VERSION 5.8 ;
BUSBITCHARS "[]" ;
DIVIDERCHAR "/" ;
UNITS
    DATABASE MICRONS 1000 ;
END UNITS

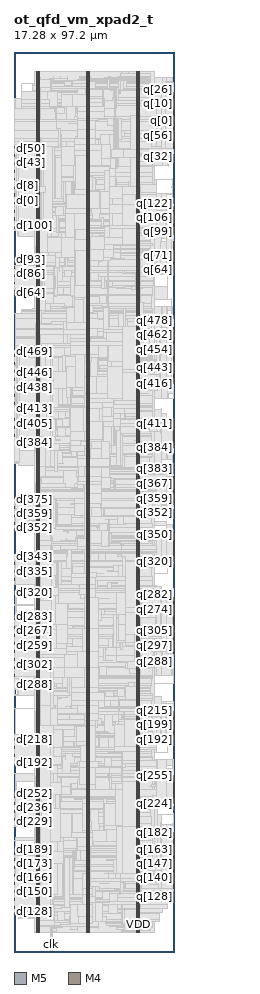
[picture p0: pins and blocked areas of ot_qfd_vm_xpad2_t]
MACRO ot_qfd_vm_xpad2_t
  FOREIGN ot_qfd_vm_xpad2_t 0 0 ;
  CLASS BLOCK ;
  SIZE 17.28 BY 97.2 ;
  PIN clk
    DIRECTION INPUT ;
    USE SIGNAL ;
    PORT
      LAYER M5 ;
        RECT  3.984 0 4.008 0.084 ;
    END
  END clk
  PIN d[0]
    DIRECTION INPUT ;
    USE SIGNAL ;
    PORT
      LAYER M4 ;
        RECT  0 81.168 0.084 81.192 ;
    END
  END d[0]
  PIN d[100]
    DIRECTION INPUT ;
    USE SIGNAL ;
    PORT
      LAYER M4 ;
        RECT  0 78.48 0.084 78.504 ;
    END
  END d[100]
  PIN d[101]
    DIRECTION INPUT ;
    USE SIGNAL ;
    PORT
      LAYER M4 ;
        RECT  0 78.576 0.084 78.6 ;
    END
  END d[101]
  PIN d[102]
    DIRECTION INPUT ;
    USE SIGNAL ;
    PORT
      LAYER M4 ;
        RECT  0 78.672 0.084 78.696 ;
    END
  END d[102]
  PIN d[103]
    DIRECTION INPUT ;
    USE SIGNAL ;
    PORT
      LAYER M4 ;
        RECT  0 78.768 0.084 78.792 ;
    END
  END d[103]
  PIN d[104]
    DIRECTION INPUT ;
    USE SIGNAL ;
    PORT
      LAYER M4 ;
        RECT  0 78.864 0.084 78.888 ;
    END
  END d[104]
  PIN d[105]
    DIRECTION INPUT ;
    USE SIGNAL ;
    PORT
      LAYER M4 ;
        RECT  0 78.96 0.084 78.984 ;
    END
  END d[105]
  PIN d[106]
    DIRECTION INPUT ;
    USE SIGNAL ;
    PORT
      LAYER M4 ;
        RECT  0 79.056 0.084 79.08 ;
    END
  END d[106]
  PIN d[107]
    DIRECTION INPUT ;
    USE SIGNAL ;
    PORT
      LAYER M4 ;
        RECT  0 79.152 0.084 79.176 ;
    END
  END d[107]
  PIN d[108]
    DIRECTION INPUT ;
    USE SIGNAL ;
    PORT
      LAYER M4 ;
        RECT  0 79.248 0.084 79.272 ;
    END
  END d[108]
  PIN d[109]
    DIRECTION INPUT ;
    USE SIGNAL ;
    PORT
      LAYER M4 ;
        RECT  0 79.344 0.084 79.368 ;
    END
  END d[109]
  PIN d[10]
    DIRECTION INPUT ;
    USE SIGNAL ;
    PORT
      LAYER M4 ;
        RECT  0 82.128 0.084 82.152 ;
    END
  END d[10]
  PIN d[110]
    DIRECTION INPUT ;
    USE SIGNAL ;
    PORT
      LAYER M4 ;
        RECT  0 79.44 0.084 79.464 ;
    END
  END d[110]
  PIN d[111]
    DIRECTION INPUT ;
    USE SIGNAL ;
    PORT
      LAYER M4 ;
        RECT  0 79.536 0.084 79.56 ;
    END
  END d[111]
  PIN d[112]
    DIRECTION INPUT ;
    USE SIGNAL ;
    PORT
      LAYER M4 ;
        RECT  0 79.632 0.084 79.656 ;
    END
  END d[112]
  PIN d[113]
    DIRECTION INPUT ;
    USE SIGNAL ;
    PORT
      LAYER M4 ;
        RECT  0 79.728 0.084 79.752 ;
    END
  END d[113]
  PIN d[114]
    DIRECTION INPUT ;
    USE SIGNAL ;
    PORT
      LAYER M4 ;
        RECT  0 79.824 0.084 79.848 ;
    END
  END d[114]
  PIN d[115]
    DIRECTION INPUT ;
    USE SIGNAL ;
    PORT
      LAYER M4 ;
        RECT  0 79.92 0.084 79.944 ;
    END
  END d[115]
  PIN d[116]
    DIRECTION INPUT ;
    USE SIGNAL ;
    PORT
      LAYER M4 ;
        RECT  0 80.016 0.084 80.04 ;
    END
  END d[116]
  PIN d[117]
    DIRECTION INPUT ;
    USE SIGNAL ;
    PORT
      LAYER M4 ;
        RECT  0 80.112 0.084 80.136 ;
    END
  END d[117]
  PIN d[118]
    DIRECTION INPUT ;
    USE SIGNAL ;
    PORT
      LAYER M4 ;
        RECT  0 80.208 0.084 80.232 ;
    END
  END d[118]
  PIN d[119]
    DIRECTION INPUT ;
    USE SIGNAL ;
    PORT
      LAYER M4 ;
        RECT  0 80.304 0.084 80.328 ;
    END
  END d[119]
  PIN d[11]
    DIRECTION INPUT ;
    USE SIGNAL ;
    PORT
      LAYER M4 ;
        RECT  0 82.224 0.084 82.248 ;
    END
  END d[11]
  PIN d[120]
    DIRECTION INPUT ;
    USE SIGNAL ;
    PORT
      LAYER M4 ;
        RECT  0 80.4 0.084 80.424 ;
    END
  END d[120]
  PIN d[121]
    DIRECTION INPUT ;
    USE SIGNAL ;
    PORT
      LAYER M4 ;
        RECT  0 80.496 0.084 80.52 ;
    END
  END d[121]
  PIN d[122]
    DIRECTION INPUT ;
    USE SIGNAL ;
    PORT
      LAYER M4 ;
        RECT  0 80.592 0.084 80.616 ;
    END
  END d[122]
  PIN d[123]
    DIRECTION INPUT ;
    USE SIGNAL ;
    PORT
      LAYER M4 ;
        RECT  0 80.688 0.084 80.712 ;
    END
  END d[123]
  PIN d[124]
    DIRECTION INPUT ;
    USE SIGNAL ;
    PORT
      LAYER M4 ;
        RECT  0 80.784 0.084 80.808 ;
    END
  END d[124]
  PIN d[125]
    DIRECTION INPUT ;
    USE SIGNAL ;
    PORT
      LAYER M4 ;
        RECT  0 80.88 0.084 80.904 ;
    END
  END d[125]
  PIN d[126]
    DIRECTION INPUT ;
    USE SIGNAL ;
    PORT
      LAYER M4 ;
        RECT  0 80.976 0.084 81 ;
    END
  END d[126]
  PIN d[127]
    DIRECTION INPUT ;
    USE SIGNAL ;
    PORT
      LAYER M4 ;
        RECT  0 81.072 0.084 81.096 ;
    END
  END d[127]
  PIN d[128]
    DIRECTION INPUT ;
    USE SIGNAL ;
    PORT
      LAYER M4 ;
        RECT  0 4.368 0.084 4.392 ;
    END
  END d[128]
  PIN d[129]
    DIRECTION INPUT ;
    USE SIGNAL ;
    PORT
      LAYER M4 ;
        RECT  0 4.464 0.084 4.488 ;
    END
  END d[129]
  PIN d[12]
    DIRECTION INPUT ;
    USE SIGNAL ;
    PORT
      LAYER M4 ;
        RECT  0 82.32 0.084 82.344 ;
    END
  END d[12]
  PIN d[130]
    DIRECTION INPUT ;
    USE SIGNAL ;
    PORT
      LAYER M4 ;
        RECT  0 4.56 0.084 4.584 ;
    END
  END d[130]
  PIN d[131]
    DIRECTION INPUT ;
    USE SIGNAL ;
    PORT
      LAYER M4 ;
        RECT  0 4.656 0.084 4.68 ;
    END
  END d[131]
  PIN d[132]
    DIRECTION INPUT ;
    USE SIGNAL ;
    PORT
      LAYER M4 ;
        RECT  0 4.752 0.084 4.776 ;
    END
  END d[132]
  PIN d[133]
    DIRECTION INPUT ;
    USE SIGNAL ;
    PORT
      LAYER M4 ;
        RECT  0 4.848 0.084 4.872 ;
    END
  END d[133]
  PIN d[134]
    DIRECTION INPUT ;
    USE SIGNAL ;
    PORT
      LAYER M4 ;
        RECT  0 4.944 0.084 4.968 ;
    END
  END d[134]
  PIN d[135]
    DIRECTION INPUT ;
    USE SIGNAL ;
    PORT
      LAYER M4 ;
        RECT  0 5.04 0.084 5.064 ;
    END
  END d[135]
  PIN d[136]
    DIRECTION INPUT ;
    USE SIGNAL ;
    PORT
      LAYER M4 ;
        RECT  0 5.136 0.084 5.16 ;
    END
  END d[136]
  PIN d[137]
    DIRECTION INPUT ;
    USE SIGNAL ;
    PORT
      LAYER M4 ;
        RECT  0 5.232 0.084 5.256 ;
    END
  END d[137]
  PIN d[138]
    DIRECTION INPUT ;
    USE SIGNAL ;
    PORT
      LAYER M4 ;
        RECT  0 5.328 0.084 5.352 ;
    END
  END d[138]
  PIN d[139]
    DIRECTION INPUT ;
    USE SIGNAL ;
    PORT
      LAYER M4 ;
        RECT  0 5.424 0.084 5.448 ;
    END
  END d[139]
  PIN d[13]
    DIRECTION INPUT ;
    USE SIGNAL ;
    PORT
      LAYER M4 ;
        RECT  0 82.416 0.084 82.44 ;
    END
  END d[13]
  PIN d[140]
    DIRECTION INPUT ;
    USE SIGNAL ;
    PORT
      LAYER M4 ;
        RECT  0 5.52 0.084 5.544 ;
    END
  END d[140]
  PIN d[141]
    DIRECTION INPUT ;
    USE SIGNAL ;
    PORT
      LAYER M4 ;
        RECT  0 5.616 0.084 5.64 ;
    END
  END d[141]
  PIN d[142]
    DIRECTION INPUT ;
    USE SIGNAL ;
    PORT
      LAYER M4 ;
        RECT  0 5.712 0.084 5.736 ;
    END
  END d[142]
  PIN d[143]
    DIRECTION INPUT ;
    USE SIGNAL ;
    PORT
      LAYER M4 ;
        RECT  0 5.808 0.084 5.832 ;
    END
  END d[143]
  PIN d[144]
    DIRECTION INPUT ;
    USE SIGNAL ;
    PORT
      LAYER M4 ;
        RECT  0 5.904 0.084 5.928 ;
    END
  END d[144]
  PIN d[145]
    DIRECTION INPUT ;
    USE SIGNAL ;
    PORT
      LAYER M4 ;
        RECT  0 6 0.084 6.024 ;
    END
  END d[145]
  PIN d[146]
    DIRECTION INPUT ;
    USE SIGNAL ;
    PORT
      LAYER M4 ;
        RECT  0 6.096 0.084 6.12 ;
    END
  END d[146]
  PIN d[147]
    DIRECTION INPUT ;
    USE SIGNAL ;
    PORT
      LAYER M4 ;
        RECT  0 6.192 0.084 6.216 ;
    END
  END d[147]
  PIN d[148]
    DIRECTION INPUT ;
    USE SIGNAL ;
    PORT
      LAYER M4 ;
        RECT  0 6.288 0.084 6.312 ;
    END
  END d[148]
  PIN d[149]
    DIRECTION INPUT ;
    USE SIGNAL ;
    PORT
      LAYER M4 ;
        RECT  0 6.384 0.084 6.408 ;
    END
  END d[149]
  PIN d[14]
    DIRECTION INPUT ;
    USE SIGNAL ;
    PORT
      LAYER M4 ;
        RECT  0 82.512 0.084 82.536 ;
    END
  END d[14]
  PIN d[150]
    DIRECTION INPUT ;
    USE SIGNAL ;
    PORT
      LAYER M4 ;
        RECT  0 6.48 0.084 6.504 ;
    END
  END d[150]
  PIN d[151]
    DIRECTION INPUT ;
    USE SIGNAL ;
    PORT
      LAYER M4 ;
        RECT  0 6.576 0.084 6.6 ;
    END
  END d[151]
  PIN d[152]
    DIRECTION INPUT ;
    USE SIGNAL ;
    PORT
      LAYER M4 ;
        RECT  0 6.672 0.084 6.696 ;
    END
  END d[152]
  PIN d[153]
    DIRECTION INPUT ;
    USE SIGNAL ;
    PORT
      LAYER M4 ;
        RECT  0 6.768 0.084 6.792 ;
    END
  END d[153]
  PIN d[154]
    DIRECTION INPUT ;
    USE SIGNAL ;
    PORT
      LAYER M4 ;
        RECT  0 6.864 0.084 6.888 ;
    END
  END d[154]
  PIN d[155]
    DIRECTION INPUT ;
    USE SIGNAL ;
    PORT
      LAYER M4 ;
        RECT  0 6.96 0.084 6.984 ;
    END
  END d[155]
  PIN d[156]
    DIRECTION INPUT ;
    USE SIGNAL ;
    PORT
      LAYER M4 ;
        RECT  0 7.056 0.084 7.08 ;
    END
  END d[156]
  PIN d[157]
    DIRECTION INPUT ;
    USE SIGNAL ;
    PORT
      LAYER M4 ;
        RECT  0 7.152 0.084 7.176 ;
    END
  END d[157]
  PIN d[158]
    DIRECTION INPUT ;
    USE SIGNAL ;
    PORT
      LAYER M4 ;
        RECT  0 7.248 0.084 7.272 ;
    END
  END d[158]
  PIN d[159]
    DIRECTION INPUT ;
    USE SIGNAL ;
    PORT
      LAYER M4 ;
        RECT  0 7.344 0.084 7.368 ;
    END
  END d[159]
  PIN d[15]
    DIRECTION INPUT ;
    USE SIGNAL ;
    PORT
      LAYER M4 ;
        RECT  0 82.608 0.084 82.632 ;
    END
  END d[15]
  PIN d[160]
    DIRECTION INPUT ;
    USE SIGNAL ;
    PORT
      LAYER M4 ;
        RECT  0 7.44 0.084 7.464 ;
    END
  END d[160]
  PIN d[161]
    DIRECTION INPUT ;
    USE SIGNAL ;
    PORT
      LAYER M4 ;
        RECT  0 7.536 0.084 7.56 ;
    END
  END d[161]
  PIN d[162]
    DIRECTION INPUT ;
    USE SIGNAL ;
    PORT
      LAYER M4 ;
        RECT  0 7.632 0.084 7.656 ;
    END
  END d[162]
  PIN d[163]
    DIRECTION INPUT ;
    USE SIGNAL ;
    PORT
      LAYER M4 ;
        RECT  0 7.728 0.084 7.752 ;
    END
  END d[163]
  PIN d[164]
    DIRECTION INPUT ;
    USE SIGNAL ;
    PORT
      LAYER M4 ;
        RECT  0 7.824 0.084 7.848 ;
    END
  END d[164]
  PIN d[165]
    DIRECTION INPUT ;
    USE SIGNAL ;
    PORT
      LAYER M4 ;
        RECT  0 7.92 0.084 7.944 ;
    END
  END d[165]
  PIN d[166]
    DIRECTION INPUT ;
    USE SIGNAL ;
    PORT
      LAYER M4 ;
        RECT  0 8.016 0.084 8.04 ;
    END
  END d[166]
  PIN d[167]
    DIRECTION INPUT ;
    USE SIGNAL ;
    PORT
      LAYER M4 ;
        RECT  0 8.112 0.084 8.136 ;
    END
  END d[167]
  PIN d[168]
    DIRECTION INPUT ;
    USE SIGNAL ;
    PORT
      LAYER M4 ;
        RECT  0 8.208 0.084 8.232 ;
    END
  END d[168]
  PIN d[169]
    DIRECTION INPUT ;
    USE SIGNAL ;
    PORT
      LAYER M4 ;
        RECT  0 8.304 0.084 8.328 ;
    END
  END d[169]
  PIN d[16]
    DIRECTION INPUT ;
    USE SIGNAL ;
    PORT
      LAYER M4 ;
        RECT  0 82.704 0.084 82.728 ;
    END
  END d[16]
  PIN d[170]
    DIRECTION INPUT ;
    USE SIGNAL ;
    PORT
      LAYER M4 ;
        RECT  0 8.4 0.084 8.424 ;
    END
  END d[170]
  PIN d[171]
    DIRECTION INPUT ;
    USE SIGNAL ;
    PORT
      LAYER M4 ;
        RECT  0 8.496 0.084 8.52 ;
    END
  END d[171]
  PIN d[172]
    DIRECTION INPUT ;
    USE SIGNAL ;
    PORT
      LAYER M4 ;
        RECT  0 8.592 0.084 8.616 ;
    END
  END d[172]
  PIN d[173]
    DIRECTION INPUT ;
    USE SIGNAL ;
    PORT
      LAYER M4 ;
        RECT  0 8.688 0.084 8.712 ;
    END
  END d[173]
  PIN d[174]
    DIRECTION INPUT ;
    USE SIGNAL ;
    PORT
      LAYER M4 ;
        RECT  0 8.784 0.084 8.808 ;
    END
  END d[174]
  PIN d[175]
    DIRECTION INPUT ;
    USE SIGNAL ;
    PORT
      LAYER M4 ;
        RECT  0 8.88 0.084 8.904 ;
    END
  END d[175]
  PIN d[176]
    DIRECTION INPUT ;
    USE SIGNAL ;
    PORT
      LAYER M4 ;
        RECT  0 8.976 0.084 9 ;
    END
  END d[176]
  PIN d[177]
    DIRECTION INPUT ;
    USE SIGNAL ;
    PORT
      LAYER M4 ;
        RECT  0 9.072 0.084 9.096 ;
    END
  END d[177]
  PIN d[178]
    DIRECTION INPUT ;
    USE SIGNAL ;
    PORT
      LAYER M4 ;
        RECT  0 9.168 0.084 9.192 ;
    END
  END d[178]
  PIN d[179]
    DIRECTION INPUT ;
    USE SIGNAL ;
    PORT
      LAYER M4 ;
        RECT  0 9.264 0.084 9.288 ;
    END
  END d[179]
  PIN d[17]
    DIRECTION INPUT ;
    USE SIGNAL ;
    PORT
      LAYER M4 ;
        RECT  0 82.8 0.084 82.824 ;
    END
  END d[17]
  PIN d[180]
    DIRECTION INPUT ;
    USE SIGNAL ;
    PORT
      LAYER M4 ;
        RECT  0 9.36 0.084 9.384 ;
    END
  END d[180]
  PIN d[181]
    DIRECTION INPUT ;
    USE SIGNAL ;
    PORT
      LAYER M4 ;
        RECT  0 9.456 0.084 9.48 ;
    END
  END d[181]
  PIN d[182]
    DIRECTION INPUT ;
    USE SIGNAL ;
    PORT
      LAYER M4 ;
        RECT  0 9.552 0.084 9.576 ;
    END
  END d[182]
  PIN d[183]
    DIRECTION INPUT ;
    USE SIGNAL ;
    PORT
      LAYER M4 ;
        RECT  0 9.648 0.084 9.672 ;
    END
  END d[183]
  PIN d[184]
    DIRECTION INPUT ;
    USE SIGNAL ;
    PORT
      LAYER M4 ;
        RECT  0 9.744 0.084 9.768 ;
    END
  END d[184]
  PIN d[185]
    DIRECTION INPUT ;
    USE SIGNAL ;
    PORT
      LAYER M4 ;
        RECT  0 9.84 0.084 9.864 ;
    END
  END d[185]
  PIN d[186]
    DIRECTION INPUT ;
    USE SIGNAL ;
    PORT
      LAYER M4 ;
        RECT  0 9.936 0.084 9.96 ;
    END
  END d[186]
  PIN d[187]
    DIRECTION INPUT ;
    USE SIGNAL ;
    PORT
      LAYER M4 ;
        RECT  0 10.032 0.084 10.056 ;
    END
  END d[187]
  PIN d[188]
    DIRECTION INPUT ;
    USE SIGNAL ;
    PORT
      LAYER M4 ;
        RECT  0 10.128 0.084 10.152 ;
    END
  END d[188]
  PIN d[189]
    DIRECTION INPUT ;
    USE SIGNAL ;
    PORT
      LAYER M4 ;
        RECT  0 10.224 0.084 10.248 ;
    END
  END d[189]
  PIN d[18]
    DIRECTION INPUT ;
    USE SIGNAL ;
    PORT
      LAYER M4 ;
        RECT  0 82.896 0.084 82.92 ;
    END
  END d[18]
  PIN d[190]
    DIRECTION INPUT ;
    USE SIGNAL ;
    PORT
      LAYER M4 ;
        RECT  0 10.32 0.084 10.344 ;
    END
  END d[190]
  PIN d[191]
    DIRECTION INPUT ;
    USE SIGNAL ;
    PORT
      LAYER M4 ;
        RECT  0 10.416 0.084 10.44 ;
    END
  END d[191]
  PIN d[192]
    DIRECTION INPUT ;
    USE SIGNAL ;
    PORT
      LAYER M4 ;
        RECT  0 20.496 0.084 20.52 ;
    END
  END d[192]
  PIN d[193]
    DIRECTION INPUT ;
    USE SIGNAL ;
    PORT
      LAYER M4 ;
        RECT  0 20.592 0.084 20.616 ;
    END
  END d[193]
  PIN d[194]
    DIRECTION INPUT ;
    USE SIGNAL ;
    PORT
      LAYER M4 ;
        RECT  0 20.688 0.084 20.712 ;
    END
  END d[194]
  PIN d[195]
    DIRECTION INPUT ;
    USE SIGNAL ;
    PORT
      LAYER M4 ;
        RECT  0 20.784 0.084 20.808 ;
    END
  END d[195]
  PIN d[196]
    DIRECTION INPUT ;
    USE SIGNAL ;
    PORT
      LAYER M4 ;
        RECT  0 20.88 0.084 20.904 ;
    END
  END d[196]
  PIN d[197]
    DIRECTION INPUT ;
    USE SIGNAL ;
    PORT
      LAYER M4 ;
        RECT  0 20.976 0.084 21 ;
    END
  END d[197]
  PIN d[198]
    DIRECTION INPUT ;
    USE SIGNAL ;
    PORT
      LAYER M4 ;
        RECT  0 21.072 0.084 21.096 ;
    END
  END d[198]
  PIN d[199]
    DIRECTION INPUT ;
    USE SIGNAL ;
    PORT
      LAYER M4 ;
        RECT  0 21.168 0.084 21.192 ;
    END
  END d[199]
  PIN d[19]
    DIRECTION INPUT ;
    USE SIGNAL ;
    PORT
      LAYER M4 ;
        RECT  0 82.992 0.084 83.016 ;
    END
  END d[19]
  PIN d[1]
    DIRECTION INPUT ;
    USE SIGNAL ;
    PORT
      LAYER M4 ;
        RECT  0 81.264 0.084 81.288 ;
    END
  END d[1]
  PIN d[200]
    DIRECTION INPUT ;
    USE SIGNAL ;
    PORT
      LAYER M4 ;
        RECT  0 21.264 0.084 21.288 ;
    END
  END d[200]
  PIN d[201]
    DIRECTION INPUT ;
    USE SIGNAL ;
    PORT
      LAYER M4 ;
        RECT  0 21.36 0.084 21.384 ;
    END
  END d[201]
  PIN d[202]
    DIRECTION INPUT ;
    USE SIGNAL ;
    PORT
      LAYER M4 ;
        RECT  0 21.456 0.084 21.48 ;
    END
  END d[202]
  PIN d[203]
    DIRECTION INPUT ;
    USE SIGNAL ;
    PORT
      LAYER M4 ;
        RECT  0 21.552 0.084 21.576 ;
    END
  END d[203]
  PIN d[204]
    DIRECTION INPUT ;
    USE SIGNAL ;
    PORT
      LAYER M4 ;
        RECT  0 21.648 0.084 21.672 ;
    END
  END d[204]
  PIN d[205]
    DIRECTION INPUT ;
    USE SIGNAL ;
    PORT
      LAYER M4 ;
        RECT  0 21.744 0.084 21.768 ;
    END
  END d[205]
  PIN d[206]
    DIRECTION INPUT ;
    USE SIGNAL ;
    PORT
      LAYER M4 ;
        RECT  0 21.84 0.084 21.864 ;
    END
  END d[206]
  PIN d[207]
    DIRECTION INPUT ;
    USE SIGNAL ;
    PORT
      LAYER M4 ;
        RECT  0 21.936 0.084 21.96 ;
    END
  END d[207]
  PIN d[208]
    DIRECTION INPUT ;
    USE SIGNAL ;
    PORT
      LAYER M4 ;
        RECT  0 22.032 0.084 22.056 ;
    END
  END d[208]
  PIN d[209]
    DIRECTION INPUT ;
    USE SIGNAL ;
    PORT
      LAYER M4 ;
        RECT  0 22.128 0.084 22.152 ;
    END
  END d[209]
  PIN d[20]
    DIRECTION INPUT ;
    USE SIGNAL ;
    PORT
      LAYER M4 ;
        RECT  0 83.088 0.084 83.112 ;
    END
  END d[20]
  PIN d[210]
    DIRECTION INPUT ;
    USE SIGNAL ;
    PORT
      LAYER M4 ;
        RECT  0 22.224 0.084 22.248 ;
    END
  END d[210]
  PIN d[211]
    DIRECTION INPUT ;
    USE SIGNAL ;
    PORT
      LAYER M4 ;
        RECT  0 22.32 0.084 22.344 ;
    END
  END d[211]
  PIN d[212]
    DIRECTION INPUT ;
    USE SIGNAL ;
    PORT
      LAYER M4 ;
        RECT  0 22.416 0.084 22.44 ;
    END
  END d[212]
  PIN d[213]
    DIRECTION INPUT ;
    USE SIGNAL ;
    PORT
      LAYER M4 ;
        RECT  0 22.512 0.084 22.536 ;
    END
  END d[213]
  PIN d[214]
    DIRECTION INPUT ;
    USE SIGNAL ;
    PORT
      LAYER M4 ;
        RECT  0 22.608 0.084 22.632 ;
    END
  END d[214]
  PIN d[215]
    DIRECTION INPUT ;
    USE SIGNAL ;
    PORT
      LAYER M4 ;
        RECT  0 22.704 0.084 22.728 ;
    END
  END d[215]
  PIN d[216]
    DIRECTION INPUT ;
    USE SIGNAL ;
    PORT
      LAYER M4 ;
        RECT  0 22.8 0.084 22.824 ;
    END
  END d[216]
  PIN d[217]
    DIRECTION INPUT ;
    USE SIGNAL ;
    PORT
      LAYER M4 ;
        RECT  0 22.896 0.084 22.92 ;
    END
  END d[217]
  PIN d[218]
    DIRECTION INPUT ;
    USE SIGNAL ;
    PORT
      LAYER M4 ;
        RECT  0 22.992 0.084 23.016 ;
    END
  END d[218]
  PIN d[219]
    DIRECTION INPUT ;
    USE SIGNAL ;
    PORT
      LAYER M4 ;
        RECT  0 23.088 0.084 23.112 ;
    END
  END d[219]
  PIN d[21]
    DIRECTION INPUT ;
    USE SIGNAL ;
    PORT
      LAYER M4 ;
        RECT  0 83.184 0.084 83.208 ;
    END
  END d[21]
  PIN d[220]
    DIRECTION INPUT ;
    USE SIGNAL ;
    PORT
      LAYER M4 ;
        RECT  0 23.184 0.084 23.208 ;
    END
  END d[220]
  PIN d[221]
    DIRECTION INPUT ;
    USE SIGNAL ;
    PORT
      LAYER M4 ;
        RECT  0 23.28 0.084 23.304 ;
    END
  END d[221]
  PIN d[222]
    DIRECTION INPUT ;
    USE SIGNAL ;
    PORT
      LAYER M4 ;
        RECT  0 23.376 0.084 23.4 ;
    END
  END d[222]
  PIN d[223]
    DIRECTION INPUT ;
    USE SIGNAL ;
    PORT
      LAYER M4 ;
        RECT  0 23.472 0.084 23.496 ;
    END
  END d[223]
  PIN d[224]
    DIRECTION INPUT ;
    USE SIGNAL ;
    PORT
      LAYER M4 ;
        RECT  0 13.584 0.084 13.608 ;
    END
  END d[224]
  PIN d[225]
    DIRECTION INPUT ;
    USE SIGNAL ;
    PORT
      LAYER M4 ;
        RECT  0 13.68 0.084 13.704 ;
    END
  END d[225]
  PIN d[226]
    DIRECTION INPUT ;
    USE SIGNAL ;
    PORT
      LAYER M4 ;
        RECT  0 13.776 0.084 13.8 ;
    END
  END d[226]
  PIN d[227]
    DIRECTION INPUT ;
    USE SIGNAL ;
    PORT
      LAYER M4 ;
        RECT  0 13.872 0.084 13.896 ;
    END
  END d[227]
  PIN d[228]
    DIRECTION INPUT ;
    USE SIGNAL ;
    PORT
      LAYER M4 ;
        RECT  0 13.968 0.084 13.992 ;
    END
  END d[228]
  PIN d[229]
    DIRECTION INPUT ;
    USE SIGNAL ;
    PORT
      LAYER M4 ;
        RECT  0 14.064 0.084 14.088 ;
    END
  END d[229]
  PIN d[22]
    DIRECTION INPUT ;
    USE SIGNAL ;
    PORT
      LAYER M4 ;
        RECT  0 83.28 0.084 83.304 ;
    END
  END d[22]
  PIN d[230]
    DIRECTION INPUT ;
    USE SIGNAL ;
    PORT
      LAYER M4 ;
        RECT  0 14.16 0.084 14.184 ;
    END
  END d[230]
  PIN d[231]
    DIRECTION INPUT ;
    USE SIGNAL ;
    PORT
      LAYER M4 ;
        RECT  0 14.256 0.084 14.28 ;
    END
  END d[231]
  PIN d[232]
    DIRECTION INPUT ;
    USE SIGNAL ;
    PORT
      LAYER M4 ;
        RECT  0 14.352 0.084 14.376 ;
    END
  END d[232]
  PIN d[233]
    DIRECTION INPUT ;
    USE SIGNAL ;
    PORT
      LAYER M4 ;
        RECT  0 14.448 0.084 14.472 ;
    END
  END d[233]
  PIN d[234]
    DIRECTION INPUT ;
    USE SIGNAL ;
    PORT
      LAYER M4 ;
        RECT  0 14.544 0.084 14.568 ;
    END
  END d[234]
  PIN d[235]
    DIRECTION INPUT ;
    USE SIGNAL ;
    PORT
      LAYER M4 ;
        RECT  0 14.64 0.084 14.664 ;
    END
  END d[235]
  PIN d[236]
    DIRECTION INPUT ;
    USE SIGNAL ;
    PORT
      LAYER M4 ;
        RECT  0 14.736 0.084 14.76 ;
    END
  END d[236]
  PIN d[237]
    DIRECTION INPUT ;
    USE SIGNAL ;
    PORT
      LAYER M4 ;
        RECT  0 14.832 0.084 14.856 ;
    END
  END d[237]
  PIN d[238]
    DIRECTION INPUT ;
    USE SIGNAL ;
    PORT
      LAYER M4 ;
        RECT  0 14.928 0.084 14.952 ;
    END
  END d[238]
  PIN d[239]
    DIRECTION INPUT ;
    USE SIGNAL ;
    PORT
      LAYER M4 ;
        RECT  0 15.024 0.084 15.048 ;
    END
  END d[239]
  PIN d[23]
    DIRECTION INPUT ;
    USE SIGNAL ;
    PORT
      LAYER M4 ;
        RECT  0 83.376 0.084 83.4 ;
    END
  END d[23]
  PIN d[240]
    DIRECTION INPUT ;
    USE SIGNAL ;
    PORT
      LAYER M4 ;
        RECT  0 15.12 0.084 15.144 ;
    END
  END d[240]
  PIN d[241]
    DIRECTION INPUT ;
    USE SIGNAL ;
    PORT
      LAYER M4 ;
        RECT  0 15.216 0.084 15.24 ;
    END
  END d[241]
  PIN d[242]
    DIRECTION INPUT ;
    USE SIGNAL ;
    PORT
      LAYER M4 ;
        RECT  0 15.312 0.084 15.336 ;
    END
  END d[242]
  PIN d[243]
    DIRECTION INPUT ;
    USE SIGNAL ;
    PORT
      LAYER M4 ;
        RECT  0 15.408 0.084 15.432 ;
    END
  END d[243]
  PIN d[244]
    DIRECTION INPUT ;
    USE SIGNAL ;
    PORT
      LAYER M4 ;
        RECT  0 15.504 0.084 15.528 ;
    END
  END d[244]
  PIN d[245]
    DIRECTION INPUT ;
    USE SIGNAL ;
    PORT
      LAYER M4 ;
        RECT  0 15.6 0.084 15.624 ;
    END
  END d[245]
  PIN d[246]
    DIRECTION INPUT ;
    USE SIGNAL ;
    PORT
      LAYER M4 ;
        RECT  0 15.696 0.084 15.72 ;
    END
  END d[246]
  PIN d[247]
    DIRECTION INPUT ;
    USE SIGNAL ;
    PORT
      LAYER M4 ;
        RECT  0 15.792 0.084 15.816 ;
    END
  END d[247]
  PIN d[248]
    DIRECTION INPUT ;
    USE SIGNAL ;
    PORT
      LAYER M4 ;
        RECT  0 15.888 0.084 15.912 ;
    END
  END d[248]
  PIN d[249]
    DIRECTION INPUT ;
    USE SIGNAL ;
    PORT
      LAYER M4 ;
        RECT  0 15.984 0.084 16.008 ;
    END
  END d[249]
  PIN d[24]
    DIRECTION INPUT ;
    USE SIGNAL ;
    PORT
      LAYER M4 ;
        RECT  0 83.472 0.084 83.496 ;
    END
  END d[24]
  PIN d[250]
    DIRECTION INPUT ;
    USE SIGNAL ;
    PORT
      LAYER M4 ;
        RECT  0 16.08 0.084 16.104 ;
    END
  END d[250]
  PIN d[251]
    DIRECTION INPUT ;
    USE SIGNAL ;
    PORT
      LAYER M4 ;
        RECT  0 16.176 0.084 16.2 ;
    END
  END d[251]
  PIN d[252]
    DIRECTION INPUT ;
    USE SIGNAL ;
    PORT
      LAYER M4 ;
        RECT  0 16.272 0.084 16.296 ;
    END
  END d[252]
  PIN d[253]
    DIRECTION INPUT ;
    USE SIGNAL ;
    PORT
      LAYER M4 ;
        RECT  0 16.368 0.084 16.392 ;
    END
  END d[253]
  PIN d[254]
    DIRECTION INPUT ;
    USE SIGNAL ;
    PORT
      LAYER M4 ;
        RECT  0 16.464 0.084 16.488 ;
    END
  END d[254]
  PIN d[255]
    DIRECTION INPUT ;
    USE SIGNAL ;
    PORT
      LAYER M4 ;
        RECT  0 16.56 0.084 16.584 ;
    END
  END d[255]
  PIN d[256]
    DIRECTION INPUT ;
    USE SIGNAL ;
    PORT
      LAYER M4 ;
        RECT  0 32.784 0.084 32.808 ;
    END
  END d[256]
  PIN d[257]
    DIRECTION INPUT ;
    USE SIGNAL ;
    PORT
      LAYER M4 ;
        RECT  0 32.88 0.084 32.904 ;
    END
  END d[257]
  PIN d[258]
    DIRECTION INPUT ;
    USE SIGNAL ;
    PORT
      LAYER M4 ;
        RECT  0 32.976 0.084 33 ;
    END
  END d[258]
  PIN d[259]
    DIRECTION INPUT ;
    USE SIGNAL ;
    PORT
      LAYER M4 ;
        RECT  0 33.072 0.084 33.096 ;
    END
  END d[259]
  PIN d[25]
    DIRECTION INPUT ;
    USE SIGNAL ;
    PORT
      LAYER M4 ;
        RECT  0 83.568 0.084 83.592 ;
    END
  END d[25]
  PIN d[260]
    DIRECTION INPUT ;
    USE SIGNAL ;
    PORT
      LAYER M4 ;
        RECT  0 33.168 0.084 33.192 ;
    END
  END d[260]
  PIN d[261]
    DIRECTION INPUT ;
    USE SIGNAL ;
    PORT
      LAYER M4 ;
        RECT  0 33.264 0.084 33.288 ;
    END
  END d[261]
  PIN d[262]
    DIRECTION INPUT ;
    USE SIGNAL ;
    PORT
      LAYER M4 ;
        RECT  0 33.36 0.084 33.384 ;
    END
  END d[262]
  PIN d[263]
    DIRECTION INPUT ;
    USE SIGNAL ;
    PORT
      LAYER M4 ;
        RECT  0 33.456 0.084 33.48 ;
    END
  END d[263]
  PIN d[264]
    DIRECTION INPUT ;
    USE SIGNAL ;
    PORT
      LAYER M4 ;
        RECT  0 33.552 0.084 33.576 ;
    END
  END d[264]
  PIN d[265]
    DIRECTION INPUT ;
    USE SIGNAL ;
    PORT
      LAYER M4 ;
        RECT  0 33.648 0.084 33.672 ;
    END
  END d[265]
  PIN d[266]
    DIRECTION INPUT ;
    USE SIGNAL ;
    PORT
      LAYER M4 ;
        RECT  0 33.744 0.084 33.768 ;
    END
  END d[266]
  PIN d[267]
    DIRECTION INPUT ;
    USE SIGNAL ;
    PORT
      LAYER M4 ;
        RECT  0 33.84 0.084 33.864 ;
    END
  END d[267]
  PIN d[268]
    DIRECTION INPUT ;
    USE SIGNAL ;
    PORT
      LAYER M4 ;
        RECT  0 33.936 0.084 33.96 ;
    END
  END d[268]
  PIN d[269]
    DIRECTION INPUT ;
    USE SIGNAL ;
    PORT
      LAYER M4 ;
        RECT  0 34.032 0.084 34.056 ;
    END
  END d[269]
  PIN d[26]
    DIRECTION INPUT ;
    USE SIGNAL ;
    PORT
      LAYER M4 ;
        RECT  0 83.664 0.084 83.688 ;
    END
  END d[26]
  PIN d[270]
    DIRECTION INPUT ;
    USE SIGNAL ;
    PORT
      LAYER M4 ;
        RECT  0 34.128 0.084 34.152 ;
    END
  END d[270]
  PIN d[271]
    DIRECTION INPUT ;
    USE SIGNAL ;
    PORT
      LAYER M4 ;
        RECT  0 34.224 0.084 34.248 ;
    END
  END d[271]
  PIN d[272]
    DIRECTION INPUT ;
    USE SIGNAL ;
    PORT
      LAYER M4 ;
        RECT  0 34.32 0.084 34.344 ;
    END
  END d[272]
  PIN d[273]
    DIRECTION INPUT ;
    USE SIGNAL ;
    PORT
      LAYER M4 ;
        RECT  0 34.416 0.084 34.44 ;
    END
  END d[273]
  PIN d[274]
    DIRECTION INPUT ;
    USE SIGNAL ;
    PORT
      LAYER M4 ;
        RECT  0 34.512 0.084 34.536 ;
    END
  END d[274]
  PIN d[275]
    DIRECTION INPUT ;
    USE SIGNAL ;
    PORT
      LAYER M4 ;
        RECT  0 34.608 0.084 34.632 ;
    END
  END d[275]
  PIN d[276]
    DIRECTION INPUT ;
    USE SIGNAL ;
    PORT
      LAYER M4 ;
        RECT  0 34.704 0.084 34.728 ;
    END
  END d[276]
  PIN d[277]
    DIRECTION INPUT ;
    USE SIGNAL ;
    PORT
      LAYER M4 ;
        RECT  0 34.8 0.084 34.824 ;
    END
  END d[277]
  PIN d[278]
    DIRECTION INPUT ;
    USE SIGNAL ;
    PORT
      LAYER M4 ;
        RECT  0 34.896 0.084 34.92 ;
    END
  END d[278]
  PIN d[279]
    DIRECTION INPUT ;
    USE SIGNAL ;
    PORT
      LAYER M4 ;
        RECT  0 34.992 0.084 35.016 ;
    END
  END d[279]
  PIN d[27]
    DIRECTION INPUT ;
    USE SIGNAL ;
    PORT
      LAYER M4 ;
        RECT  0 83.76 0.084 83.784 ;
    END
  END d[27]
  PIN d[280]
    DIRECTION INPUT ;
    USE SIGNAL ;
    PORT
      LAYER M4 ;
        RECT  0 35.088 0.084 35.112 ;
    END
  END d[280]
  PIN d[281]
    DIRECTION INPUT ;
    USE SIGNAL ;
    PORT
      LAYER M4 ;
        RECT  0 35.184 0.084 35.208 ;
    END
  END d[281]
  PIN d[282]
    DIRECTION INPUT ;
    USE SIGNAL ;
    PORT
      LAYER M4 ;
        RECT  0 35.28 0.084 35.304 ;
    END
  END d[282]
  PIN d[283]
    DIRECTION INPUT ;
    USE SIGNAL ;
    PORT
      LAYER M4 ;
        RECT  0 35.376 0.084 35.4 ;
    END
  END d[283]
  PIN d[284]
    DIRECTION INPUT ;
    USE SIGNAL ;
    PORT
      LAYER M4 ;
        RECT  0 35.472 0.084 35.496 ;
    END
  END d[284]
  PIN d[285]
    DIRECTION INPUT ;
    USE SIGNAL ;
    PORT
      LAYER M4 ;
        RECT  0 35.568 0.084 35.592 ;
    END
  END d[285]
  PIN d[286]
    DIRECTION INPUT ;
    USE SIGNAL ;
    PORT
      LAYER M4 ;
        RECT  0 35.664 0.084 35.688 ;
    END
  END d[286]
  PIN d[287]
    DIRECTION INPUT ;
    USE SIGNAL ;
    PORT
      LAYER M4 ;
        RECT  0 35.76 0.084 35.784 ;
    END
  END d[287]
  PIN d[288]
    DIRECTION INPUT ;
    USE SIGNAL ;
    PORT
      LAYER M4 ;
        RECT  0 29.712 0.084 29.736 ;
    END
  END d[288]
  PIN d[289]
    DIRECTION INPUT ;
    USE SIGNAL ;
    PORT
      LAYER M4 ;
        RECT  0 29.808 0.084 29.832 ;
    END
  END d[289]
  PIN d[28]
    DIRECTION INPUT ;
    USE SIGNAL ;
    PORT
      LAYER M4 ;
        RECT  0 83.856 0.084 83.88 ;
    END
  END d[28]
  PIN d[290]
    DIRECTION INPUT ;
    USE SIGNAL ;
    PORT
      LAYER M4 ;
        RECT  0 29.904 0.084 29.928 ;
    END
  END d[290]
  PIN d[291]
    DIRECTION INPUT ;
    USE SIGNAL ;
    PORT
      LAYER M4 ;
        RECT  0 30 0.084 30.024 ;
    END
  END d[291]
  PIN d[292]
    DIRECTION INPUT ;
    USE SIGNAL ;
    PORT
      LAYER M4 ;
        RECT  0 30.096 0.084 30.12 ;
    END
  END d[292]
  PIN d[293]
    DIRECTION INPUT ;
    USE SIGNAL ;
    PORT
      LAYER M4 ;
        RECT  0 30.192 0.084 30.216 ;
    END
  END d[293]
  PIN d[294]
    DIRECTION INPUT ;
    USE SIGNAL ;
    PORT
      LAYER M4 ;
        RECT  0 30.288 0.084 30.312 ;
    END
  END d[294]
  PIN d[295]
    DIRECTION INPUT ;
    USE SIGNAL ;
    PORT
      LAYER M4 ;
        RECT  0 30.384 0.084 30.408 ;
    END
  END d[295]
  PIN d[296]
    DIRECTION INPUT ;
    USE SIGNAL ;
    PORT
      LAYER M4 ;
        RECT  0 30.48 0.084 30.504 ;
    END
  END d[296]
  PIN d[297]
    DIRECTION INPUT ;
    USE SIGNAL ;
    PORT
      LAYER M4 ;
        RECT  0 30.576 0.084 30.6 ;
    END
  END d[297]
  PIN d[298]
    DIRECTION INPUT ;
    USE SIGNAL ;
    PORT
      LAYER M4 ;
        RECT  0 30.672 0.084 30.696 ;
    END
  END d[298]
  PIN d[299]
    DIRECTION INPUT ;
    USE SIGNAL ;
    PORT
      LAYER M4 ;
        RECT  0 30.768 0.084 30.792 ;
    END
  END d[299]
  PIN d[29]
    DIRECTION INPUT ;
    USE SIGNAL ;
    PORT
      LAYER M4 ;
        RECT  0 83.952 0.084 83.976 ;
    END
  END d[29]
  PIN d[2]
    DIRECTION INPUT ;
    USE SIGNAL ;
    PORT
      LAYER M4 ;
        RECT  0 81.36 0.084 81.384 ;
    END
  END d[2]
  PIN d[300]
    DIRECTION INPUT ;
    USE SIGNAL ;
    PORT
      LAYER M4 ;
        RECT  0 30.864 0.084 30.888 ;
    END
  END d[300]
  PIN d[301]
    DIRECTION INPUT ;
    USE SIGNAL ;
    PORT
      LAYER M4 ;
        RECT  0 30.96 0.084 30.984 ;
    END
  END d[301]
  PIN d[302]
    DIRECTION INPUT ;
    USE SIGNAL ;
    PORT
      LAYER M4 ;
        RECT  0 31.056 0.084 31.08 ;
    END
  END d[302]
  PIN d[303]
    DIRECTION INPUT ;
    USE SIGNAL ;
    PORT
      LAYER M4 ;
        RECT  0 31.152 0.084 31.176 ;
    END
  END d[303]
  PIN d[304]
    DIRECTION INPUT ;
    USE SIGNAL ;
    PORT
      LAYER M4 ;
        RECT  0 31.248 0.084 31.272 ;
    END
  END d[304]
  PIN d[305]
    DIRECTION INPUT ;
    USE SIGNAL ;
    PORT
      LAYER M4 ;
        RECT  0 31.344 0.084 31.368 ;
    END
  END d[305]
  PIN d[306]
    DIRECTION INPUT ;
    USE SIGNAL ;
    PORT
      LAYER M4 ;
        RECT  0 31.44 0.084 31.464 ;
    END
  END d[306]
  PIN d[307]
    DIRECTION INPUT ;
    USE SIGNAL ;
    PORT
      LAYER M4 ;
        RECT  0 31.536 0.084 31.56 ;
    END
  END d[307]
  PIN d[308]
    DIRECTION INPUT ;
    USE SIGNAL ;
    PORT
      LAYER M4 ;
        RECT  0 31.632 0.084 31.656 ;
    END
  END d[308]
  PIN d[309]
    DIRECTION INPUT ;
    USE SIGNAL ;
    PORT
      LAYER M4 ;
        RECT  0 31.728 0.084 31.752 ;
    END
  END d[309]
  PIN d[30]
    DIRECTION INPUT ;
    USE SIGNAL ;
    PORT
      LAYER M4 ;
        RECT  0 84.048 0.084 84.072 ;
    END
  END d[30]
  PIN d[310]
    DIRECTION INPUT ;
    USE SIGNAL ;
    PORT
      LAYER M4 ;
        RECT  0 31.824 0.084 31.848 ;
    END
  END d[310]
  PIN d[311]
    DIRECTION INPUT ;
    USE SIGNAL ;
    PORT
      LAYER M4 ;
        RECT  0 31.92 0.084 31.944 ;
    END
  END d[311]
  PIN d[312]
    DIRECTION INPUT ;
    USE SIGNAL ;
    PORT
      LAYER M4 ;
        RECT  0 32.016 0.084 32.04 ;
    END
  END d[312]
  PIN d[313]
    DIRECTION INPUT ;
    USE SIGNAL ;
    PORT
      LAYER M4 ;
        RECT  0 32.112 0.084 32.136 ;
    END
  END d[313]
  PIN d[314]
    DIRECTION INPUT ;
    USE SIGNAL ;
    PORT
      LAYER M4 ;
        RECT  0 32.208 0.084 32.232 ;
    END
  END d[314]
  PIN d[315]
    DIRECTION INPUT ;
    USE SIGNAL ;
    PORT
      LAYER M4 ;
        RECT  0 32.304 0.084 32.328 ;
    END
  END d[315]
  PIN d[316]
    DIRECTION INPUT ;
    USE SIGNAL ;
    PORT
      LAYER M4 ;
        RECT  0 32.4 0.084 32.424 ;
    END
  END d[316]
  PIN d[317]
    DIRECTION INPUT ;
    USE SIGNAL ;
    PORT
      LAYER M4 ;
        RECT  0 32.496 0.084 32.52 ;
    END
  END d[317]
  PIN d[318]
    DIRECTION INPUT ;
    USE SIGNAL ;
    PORT
      LAYER M4 ;
        RECT  0 32.592 0.084 32.616 ;
    END
  END d[318]
  PIN d[319]
    DIRECTION INPUT ;
    USE SIGNAL ;
    PORT
      LAYER M4 ;
        RECT  0 32.688 0.084 32.712 ;
    END
  END d[319]
  PIN d[31]
    DIRECTION INPUT ;
    USE SIGNAL ;
    PORT
      LAYER M4 ;
        RECT  0 84.144 0.084 84.168 ;
    END
  END d[31]
  PIN d[320]
    DIRECTION INPUT ;
    USE SIGNAL ;
    PORT
      LAYER M4 ;
        RECT  0 39.696 0.084 39.72 ;
    END
  END d[320]
  PIN d[321]
    DIRECTION INPUT ;
    USE SIGNAL ;
    PORT
      LAYER M4 ;
        RECT  0 39.792 0.084 39.816 ;
    END
  END d[321]
  PIN d[322]
    DIRECTION INPUT ;
    USE SIGNAL ;
    PORT
      LAYER M4 ;
        RECT  0 39.888 0.084 39.912 ;
    END
  END d[322]
  PIN d[323]
    DIRECTION INPUT ;
    USE SIGNAL ;
    PORT
      LAYER M4 ;
        RECT  0 39.984 0.084 40.008 ;
    END
  END d[323]
  PIN d[324]
    DIRECTION INPUT ;
    USE SIGNAL ;
    PORT
      LAYER M4 ;
        RECT  0 40.08 0.084 40.104 ;
    END
  END d[324]
  PIN d[325]
    DIRECTION INPUT ;
    USE SIGNAL ;
    PORT
      LAYER M4 ;
        RECT  0 40.176 0.084 40.2 ;
    END
  END d[325]
  PIN d[326]
    DIRECTION INPUT ;
    USE SIGNAL ;
    PORT
      LAYER M4 ;
        RECT  0 40.272 0.084 40.296 ;
    END
  END d[326]
  PIN d[327]
    DIRECTION INPUT ;
    USE SIGNAL ;
    PORT
      LAYER M4 ;
        RECT  0 40.368 0.084 40.392 ;
    END
  END d[327]
  PIN d[328]
    DIRECTION INPUT ;
    USE SIGNAL ;
    PORT
      LAYER M4 ;
        RECT  0 40.464 0.084 40.488 ;
    END
  END d[328]
  PIN d[329]
    DIRECTION INPUT ;
    USE SIGNAL ;
    PORT
      LAYER M4 ;
        RECT  0 40.56 0.084 40.584 ;
    END
  END d[329]
  PIN d[32]
    DIRECTION INPUT ;
    USE SIGNAL ;
    PORT
      LAYER M4 ;
        RECT  0 84.24 0.084 84.264 ;
    END
  END d[32]
  PIN d[330]
    DIRECTION INPUT ;
    USE SIGNAL ;
    PORT
      LAYER M4 ;
        RECT  0 40.656 0.084 40.68 ;
    END
  END d[330]
  PIN d[331]
    DIRECTION INPUT ;
    USE SIGNAL ;
    PORT
      LAYER M4 ;
        RECT  0 40.752 0.084 40.776 ;
    END
  END d[331]
  PIN d[332]
    DIRECTION INPUT ;
    USE SIGNAL ;
    PORT
      LAYER M4 ;
        RECT  0 40.848 0.084 40.872 ;
    END
  END d[332]
  PIN d[333]
    DIRECTION INPUT ;
    USE SIGNAL ;
    PORT
      LAYER M4 ;
        RECT  0 40.944 0.084 40.968 ;
    END
  END d[333]
  PIN d[334]
    DIRECTION INPUT ;
    USE SIGNAL ;
    PORT
      LAYER M4 ;
        RECT  0 41.04 0.084 41.064 ;
    END
  END d[334]
  PIN d[335]
    DIRECTION INPUT ;
    USE SIGNAL ;
    PORT
      LAYER M4 ;
        RECT  0 41.136 0.084 41.16 ;
    END
  END d[335]
  PIN d[336]
    DIRECTION INPUT ;
    USE SIGNAL ;
    PORT
      LAYER M4 ;
        RECT  0 41.232 0.084 41.256 ;
    END
  END d[336]
  PIN d[337]
    DIRECTION INPUT ;
    USE SIGNAL ;
    PORT
      LAYER M4 ;
        RECT  0 41.328 0.084 41.352 ;
    END
  END d[337]
  PIN d[338]
    DIRECTION INPUT ;
    USE SIGNAL ;
    PORT
      LAYER M4 ;
        RECT  0 41.424 0.084 41.448 ;
    END
  END d[338]
  PIN d[339]
    DIRECTION INPUT ;
    USE SIGNAL ;
    PORT
      LAYER M4 ;
        RECT  0 41.52 0.084 41.544 ;
    END
  END d[339]
  PIN d[33]
    DIRECTION INPUT ;
    USE SIGNAL ;
    PORT
      LAYER M4 ;
        RECT  0 84.336 0.084 84.36 ;
    END
  END d[33]
  PIN d[340]
    DIRECTION INPUT ;
    USE SIGNAL ;
    PORT
      LAYER M4 ;
        RECT  0 41.616 0.084 41.64 ;
    END
  END d[340]
  PIN d[341]
    DIRECTION INPUT ;
    USE SIGNAL ;
    PORT
      LAYER M4 ;
        RECT  0 41.712 0.084 41.736 ;
    END
  END d[341]
  PIN d[342]
    DIRECTION INPUT ;
    USE SIGNAL ;
    PORT
      LAYER M4 ;
        RECT  0 41.808 0.084 41.832 ;
    END
  END d[342]
  PIN d[343]
    DIRECTION INPUT ;
    USE SIGNAL ;
    PORT
      LAYER M4 ;
        RECT  0 41.904 0.084 41.928 ;
    END
  END d[343]
  PIN d[344]
    DIRECTION INPUT ;
    USE SIGNAL ;
    PORT
      LAYER M4 ;
        RECT  0 42 0.084 42.024 ;
    END
  END d[344]
  PIN d[345]
    DIRECTION INPUT ;
    USE SIGNAL ;
    PORT
      LAYER M4 ;
        RECT  0 42.096 0.084 42.12 ;
    END
  END d[345]
  PIN d[346]
    DIRECTION INPUT ;
    USE SIGNAL ;
    PORT
      LAYER M4 ;
        RECT  0 42.192 0.084 42.216 ;
    END
  END d[346]
  PIN d[347]
    DIRECTION INPUT ;
    USE SIGNAL ;
    PORT
      LAYER M4 ;
        RECT  0 42.288 0.084 42.312 ;
    END
  END d[347]
  PIN d[348]
    DIRECTION INPUT ;
    USE SIGNAL ;
    PORT
      LAYER M4 ;
        RECT  0 42.384 0.084 42.408 ;
    END
  END d[348]
  PIN d[349]
    DIRECTION INPUT ;
    USE SIGNAL ;
    PORT
      LAYER M4 ;
        RECT  0 42.48 0.084 42.504 ;
    END
  END d[349]
  PIN d[34]
    DIRECTION INPUT ;
    USE SIGNAL ;
    PORT
      LAYER M4 ;
        RECT  0 84.432 0.084 84.456 ;
    END
  END d[34]
  PIN d[350]
    DIRECTION INPUT ;
    USE SIGNAL ;
    PORT
      LAYER M4 ;
        RECT  0 42.576 0.084 42.6 ;
    END
  END d[350]
  PIN d[351]
    DIRECTION INPUT ;
    USE SIGNAL ;
    PORT
      LAYER M4 ;
        RECT  0 42.672 0.084 42.696 ;
    END
  END d[351]
  PIN d[352]
    DIRECTION INPUT ;
    USE SIGNAL ;
    PORT
      LAYER M4 ;
        RECT  0 45.84 0.084 45.864 ;
    END
  END d[352]
  PIN d[353]
    DIRECTION INPUT ;
    USE SIGNAL ;
    PORT
      LAYER M4 ;
        RECT  0 45.936 0.084 45.96 ;
    END
  END d[353]
  PIN d[354]
    DIRECTION INPUT ;
    USE SIGNAL ;
    PORT
      LAYER M4 ;
        RECT  0 46.032 0.084 46.056 ;
    END
  END d[354]
  PIN d[355]
    DIRECTION INPUT ;
    USE SIGNAL ;
    PORT
      LAYER M4 ;
        RECT  0 46.128 0.084 46.152 ;
    END
  END d[355]
  PIN d[356]
    DIRECTION INPUT ;
    USE SIGNAL ;
    PORT
      LAYER M4 ;
        RECT  0 46.224 0.084 46.248 ;
    END
  END d[356]
  PIN d[357]
    DIRECTION INPUT ;
    USE SIGNAL ;
    PORT
      LAYER M4 ;
        RECT  0 46.32 0.084 46.344 ;
    END
  END d[357]
  PIN d[358]
    DIRECTION INPUT ;
    USE SIGNAL ;
    PORT
      LAYER M4 ;
        RECT  0 46.416 0.084 46.44 ;
    END
  END d[358]
  PIN d[359]
    DIRECTION INPUT ;
    USE SIGNAL ;
    PORT
      LAYER M4 ;
        RECT  0 46.512 0.084 46.536 ;
    END
  END d[359]
  PIN d[35]
    DIRECTION INPUT ;
    USE SIGNAL ;
    PORT
      LAYER M4 ;
        RECT  0 84.528 0.084 84.552 ;
    END
  END d[35]
  PIN d[360]
    DIRECTION INPUT ;
    USE SIGNAL ;
    PORT
      LAYER M4 ;
        RECT  0 46.608 0.084 46.632 ;
    END
  END d[360]
  PIN d[361]
    DIRECTION INPUT ;
    USE SIGNAL ;
    PORT
      LAYER M4 ;
        RECT  0 46.704 0.084 46.728 ;
    END
  END d[361]
  PIN d[362]
    DIRECTION INPUT ;
    USE SIGNAL ;
    PORT
      LAYER M4 ;
        RECT  0 46.8 0.084 46.824 ;
    END
  END d[362]
  PIN d[363]
    DIRECTION INPUT ;
    USE SIGNAL ;
    PORT
      LAYER M4 ;
        RECT  0 46.896 0.084 46.92 ;
    END
  END d[363]
  PIN d[364]
    DIRECTION INPUT ;
    USE SIGNAL ;
    PORT
      LAYER M4 ;
        RECT  0 46.992 0.084 47.016 ;
    END
  END d[364]
  PIN d[365]
    DIRECTION INPUT ;
    USE SIGNAL ;
    PORT
      LAYER M4 ;
        RECT  0 47.088 0.084 47.112 ;
    END
  END d[365]
  PIN d[366]
    DIRECTION INPUT ;
    USE SIGNAL ;
    PORT
      LAYER M4 ;
        RECT  0 47.184 0.084 47.208 ;
    END
  END d[366]
  PIN d[367]
    DIRECTION INPUT ;
    USE SIGNAL ;
    PORT
      LAYER M4 ;
        RECT  0 47.28 0.084 47.304 ;
    END
  END d[367]
  PIN d[368]
    DIRECTION INPUT ;
    USE SIGNAL ;
    PORT
      LAYER M4 ;
        RECT  0 47.376 0.084 47.4 ;
    END
  END d[368]
  PIN d[369]
    DIRECTION INPUT ;
    USE SIGNAL ;
    PORT
      LAYER M4 ;
        RECT  0 47.472 0.084 47.496 ;
    END
  END d[369]
  PIN d[36]
    DIRECTION INPUT ;
    USE SIGNAL ;
    PORT
      LAYER M4 ;
        RECT  0 84.624 0.084 84.648 ;
    END
  END d[36]
  PIN d[370]
    DIRECTION INPUT ;
    USE SIGNAL ;
    PORT
      LAYER M4 ;
        RECT  0 47.568 0.084 47.592 ;
    END
  END d[370]
  PIN d[371]
    DIRECTION INPUT ;
    USE SIGNAL ;
    PORT
      LAYER M4 ;
        RECT  0 47.664 0.084 47.688 ;
    END
  END d[371]
  PIN d[372]
    DIRECTION INPUT ;
    USE SIGNAL ;
    PORT
      LAYER M4 ;
        RECT  0 47.76 0.084 47.784 ;
    END
  END d[372]
  PIN d[373]
    DIRECTION INPUT ;
    USE SIGNAL ;
    PORT
      LAYER M4 ;
        RECT  0 47.856 0.084 47.88 ;
    END
  END d[373]
  PIN d[374]
    DIRECTION INPUT ;
    USE SIGNAL ;
    PORT
      LAYER M4 ;
        RECT  0 47.952 0.084 47.976 ;
    END
  END d[374]
  PIN d[375]
    DIRECTION INPUT ;
    USE SIGNAL ;
    PORT
      LAYER M4 ;
        RECT  0 48.048 0.084 48.072 ;
    END
  END d[375]
  PIN d[376]
    DIRECTION INPUT ;
    USE SIGNAL ;
    PORT
      LAYER M4 ;
        RECT  0 48.144 0.084 48.168 ;
    END
  END d[376]
  PIN d[377]
    DIRECTION INPUT ;
    USE SIGNAL ;
    PORT
      LAYER M4 ;
        RECT  0 48.24 0.084 48.264 ;
    END
  END d[377]
  PIN d[378]
    DIRECTION INPUT ;
    USE SIGNAL ;
    PORT
      LAYER M4 ;
        RECT  0 48.336 0.084 48.36 ;
    END
  END d[378]
  PIN d[379]
    DIRECTION INPUT ;
    USE SIGNAL ;
    PORT
      LAYER M4 ;
        RECT  0 48.432 0.084 48.456 ;
    END
  END d[379]
  PIN d[37]
    DIRECTION INPUT ;
    USE SIGNAL ;
    PORT
      LAYER M4 ;
        RECT  0 84.72 0.084 84.744 ;
    END
  END d[37]
  PIN d[380]
    DIRECTION INPUT ;
    USE SIGNAL ;
    PORT
      LAYER M4 ;
        RECT  0 48.528 0.084 48.552 ;
    END
  END d[380]
  PIN d[381]
    DIRECTION INPUT ;
    USE SIGNAL ;
    PORT
      LAYER M4 ;
        RECT  0 48.624 0.084 48.648 ;
    END
  END d[381]
  PIN d[382]
    DIRECTION INPUT ;
    USE SIGNAL ;
    PORT
      LAYER M4 ;
        RECT  0 48.72 0.084 48.744 ;
    END
  END d[382]
  PIN d[383]
    DIRECTION INPUT ;
    USE SIGNAL ;
    PORT
      LAYER M4 ;
        RECT  0 48.816 0.084 48.84 ;
    END
  END d[383]
  PIN d[384]
    DIRECTION INPUT ;
    USE SIGNAL ;
    PORT
      LAYER M4 ;
        RECT  0 55.056 0.084 55.08 ;
    END
  END d[384]
  PIN d[385]
    DIRECTION INPUT ;
    USE SIGNAL ;
    PORT
      LAYER M4 ;
        RECT  0 55.152 0.084 55.176 ;
    END
  END d[385]
  PIN d[386]
    DIRECTION INPUT ;
    USE SIGNAL ;
    PORT
      LAYER M4 ;
        RECT  0 55.248 0.084 55.272 ;
    END
  END d[386]
  PIN d[387]
    DIRECTION INPUT ;
    USE SIGNAL ;
    PORT
      LAYER M4 ;
        RECT  0 55.344 0.084 55.368 ;
    END
  END d[387]
  PIN d[388]
    DIRECTION INPUT ;
    USE SIGNAL ;
    PORT
      LAYER M4 ;
        RECT  0 55.44 0.084 55.464 ;
    END
  END d[388]
  PIN d[389]
    DIRECTION INPUT ;
    USE SIGNAL ;
    PORT
      LAYER M4 ;
        RECT  0 55.536 0.084 55.56 ;
    END
  END d[389]
  PIN d[38]
    DIRECTION INPUT ;
    USE SIGNAL ;
    PORT
      LAYER M4 ;
        RECT  0 84.816 0.084 84.84 ;
    END
  END d[38]
  PIN d[390]
    DIRECTION INPUT ;
    USE SIGNAL ;
    PORT
      LAYER M4 ;
        RECT  0 55.632 0.084 55.656 ;
    END
  END d[390]
  PIN d[391]
    DIRECTION INPUT ;
    USE SIGNAL ;
    PORT
      LAYER M4 ;
        RECT  0 55.728 0.084 55.752 ;
    END
  END d[391]
  PIN d[392]
    DIRECTION INPUT ;
    USE SIGNAL ;
    PORT
      LAYER M4 ;
        RECT  0 55.824 0.084 55.848 ;
    END
  END d[392]
  PIN d[393]
    DIRECTION INPUT ;
    USE SIGNAL ;
    PORT
      LAYER M4 ;
        RECT  0 55.92 0.084 55.944 ;
    END
  END d[393]
  PIN d[394]
    DIRECTION INPUT ;
    USE SIGNAL ;
    PORT
      LAYER M4 ;
        RECT  0 56.016 0.084 56.04 ;
    END
  END d[394]
  PIN d[395]
    DIRECTION INPUT ;
    USE SIGNAL ;
    PORT
      LAYER M4 ;
        RECT  0 56.112 0.084 56.136 ;
    END
  END d[395]
  PIN d[396]
    DIRECTION INPUT ;
    USE SIGNAL ;
    PORT
      LAYER M4 ;
        RECT  0 56.208 0.084 56.232 ;
    END
  END d[396]
  PIN d[397]
    DIRECTION INPUT ;
    USE SIGNAL ;
    PORT
      LAYER M4 ;
        RECT  0 56.304 0.084 56.328 ;
    END
  END d[397]
  PIN d[398]
    DIRECTION INPUT ;
    USE SIGNAL ;
    PORT
      LAYER M4 ;
        RECT  0 56.4 0.084 56.424 ;
    END
  END d[398]
  PIN d[399]
    DIRECTION INPUT ;
    USE SIGNAL ;
    PORT
      LAYER M4 ;
        RECT  0 56.496 0.084 56.52 ;
    END
  END d[399]
  PIN d[39]
    DIRECTION INPUT ;
    USE SIGNAL ;
    PORT
      LAYER M4 ;
        RECT  0 84.912 0.084 84.936 ;
    END
  END d[39]
  PIN d[3]
    DIRECTION INPUT ;
    USE SIGNAL ;
    PORT
      LAYER M4 ;
        RECT  0 81.456 0.084 81.48 ;
    END
  END d[3]
  PIN d[400]
    DIRECTION INPUT ;
    USE SIGNAL ;
    PORT
      LAYER M4 ;
        RECT  0 56.592 0.084 56.616 ;
    END
  END d[400]
  PIN d[401]
    DIRECTION INPUT ;
    USE SIGNAL ;
    PORT
      LAYER M4 ;
        RECT  0 56.688 0.084 56.712 ;
    END
  END d[401]
  PIN d[402]
    DIRECTION INPUT ;
    USE SIGNAL ;
    PORT
      LAYER M4 ;
        RECT  0 56.784 0.084 56.808 ;
    END
  END d[402]
  PIN d[403]
    DIRECTION INPUT ;
    USE SIGNAL ;
    PORT
      LAYER M4 ;
        RECT  0 56.88 0.084 56.904 ;
    END
  END d[403]
  PIN d[404]
    DIRECTION INPUT ;
    USE SIGNAL ;
    PORT
      LAYER M4 ;
        RECT  0 56.976 0.084 57 ;
    END
  END d[404]
  PIN d[405]
    DIRECTION INPUT ;
    USE SIGNAL ;
    PORT
      LAYER M4 ;
        RECT  0 57.072 0.084 57.096 ;
    END
  END d[405]
  PIN d[406]
    DIRECTION INPUT ;
    USE SIGNAL ;
    PORT
      LAYER M4 ;
        RECT  0 57.168 0.084 57.192 ;
    END
  END d[406]
  PIN d[407]
    DIRECTION INPUT ;
    USE SIGNAL ;
    PORT
      LAYER M4 ;
        RECT  0 57.264 0.084 57.288 ;
    END
  END d[407]
  PIN d[408]
    DIRECTION INPUT ;
    USE SIGNAL ;
    PORT
      LAYER M4 ;
        RECT  0 57.36 0.084 57.384 ;
    END
  END d[408]
  PIN d[409]
    DIRECTION INPUT ;
    USE SIGNAL ;
    PORT
      LAYER M4 ;
        RECT  0 57.456 0.084 57.48 ;
    END
  END d[409]
  PIN d[40]
    DIRECTION INPUT ;
    USE SIGNAL ;
    PORT
      LAYER M4 ;
        RECT  0 85.008 0.084 85.032 ;
    END
  END d[40]
  PIN d[410]
    DIRECTION INPUT ;
    USE SIGNAL ;
    PORT
      LAYER M4 ;
        RECT  0 57.552 0.084 57.576 ;
    END
  END d[410]
  PIN d[411]
    DIRECTION INPUT ;
    USE SIGNAL ;
    PORT
      LAYER M4 ;
        RECT  0 57.648 0.084 57.672 ;
    END
  END d[411]
  PIN d[412]
    DIRECTION INPUT ;
    USE SIGNAL ;
    PORT
      LAYER M4 ;
        RECT  0 57.744 0.084 57.768 ;
    END
  END d[412]
  PIN d[413]
    DIRECTION INPUT ;
    USE SIGNAL ;
    PORT
      LAYER M4 ;
        RECT  0 57.84 0.084 57.864 ;
    END
  END d[413]
  PIN d[414]
    DIRECTION INPUT ;
    USE SIGNAL ;
    PORT
      LAYER M4 ;
        RECT  0 57.936 0.084 57.96 ;
    END
  END d[414]
  PIN d[415]
    DIRECTION INPUT ;
    USE SIGNAL ;
    PORT
      LAYER M4 ;
        RECT  0 58.032 0.084 58.056 ;
    END
  END d[415]
  PIN d[416]
    DIRECTION INPUT ;
    USE SIGNAL ;
    PORT
      LAYER M4 ;
        RECT  0 58.896 0.084 58.92 ;
    END
  END d[416]
  PIN d[417]
    DIRECTION INPUT ;
    USE SIGNAL ;
    PORT
      LAYER M4 ;
        RECT  0 58.992 0.084 59.016 ;
    END
  END d[417]
  PIN d[418]
    DIRECTION INPUT ;
    USE SIGNAL ;
    PORT
      LAYER M4 ;
        RECT  0 59.088 0.084 59.112 ;
    END
  END d[418]
  PIN d[419]
    DIRECTION INPUT ;
    USE SIGNAL ;
    PORT
      LAYER M4 ;
        RECT  0 59.184 0.084 59.208 ;
    END
  END d[419]
  PIN d[41]
    DIRECTION INPUT ;
    USE SIGNAL ;
    PORT
      LAYER M4 ;
        RECT  0 85.104 0.084 85.128 ;
    END
  END d[41]
  PIN d[420]
    DIRECTION INPUT ;
    USE SIGNAL ;
    PORT
      LAYER M4 ;
        RECT  0 59.28 0.084 59.304 ;
    END
  END d[420]
  PIN d[421]
    DIRECTION INPUT ;
    USE SIGNAL ;
    PORT
      LAYER M4 ;
        RECT  0 59.376 0.084 59.4 ;
    END
  END d[421]
  PIN d[422]
    DIRECTION INPUT ;
    USE SIGNAL ;
    PORT
      LAYER M4 ;
        RECT  0 59.472 0.084 59.496 ;
    END
  END d[422]
  PIN d[423]
    DIRECTION INPUT ;
    USE SIGNAL ;
    PORT
      LAYER M4 ;
        RECT  0 59.568 0.084 59.592 ;
    END
  END d[423]
  PIN d[424]
    DIRECTION INPUT ;
    USE SIGNAL ;
    PORT
      LAYER M4 ;
        RECT  0 59.664 0.084 59.688 ;
    END
  END d[424]
  PIN d[425]
    DIRECTION INPUT ;
    USE SIGNAL ;
    PORT
      LAYER M4 ;
        RECT  0 59.76 0.084 59.784 ;
    END
  END d[425]
  PIN d[426]
    DIRECTION INPUT ;
    USE SIGNAL ;
    PORT
      LAYER M4 ;
        RECT  0 59.856 0.084 59.88 ;
    END
  END d[426]
  PIN d[427]
    DIRECTION INPUT ;
    USE SIGNAL ;
    PORT
      LAYER M4 ;
        RECT  0 59.952 0.084 59.976 ;
    END
  END d[427]
  PIN d[428]
    DIRECTION INPUT ;
    USE SIGNAL ;
    PORT
      LAYER M4 ;
        RECT  0 60.048 0.084 60.072 ;
    END
  END d[428]
  PIN d[429]
    DIRECTION INPUT ;
    USE SIGNAL ;
    PORT
      LAYER M4 ;
        RECT  0 60.144 0.084 60.168 ;
    END
  END d[429]
  PIN d[42]
    DIRECTION INPUT ;
    USE SIGNAL ;
    PORT
      LAYER M4 ;
        RECT  0 85.2 0.084 85.224 ;
    END
  END d[42]
  PIN d[430]
    DIRECTION INPUT ;
    USE SIGNAL ;
    PORT
      LAYER M4 ;
        RECT  0 60.24 0.084 60.264 ;
    END
  END d[430]
  PIN d[431]
    DIRECTION INPUT ;
    USE SIGNAL ;
    PORT
      LAYER M4 ;
        RECT  0 60.336 0.084 60.36 ;
    END
  END d[431]
  PIN d[432]
    DIRECTION INPUT ;
    USE SIGNAL ;
    PORT
      LAYER M4 ;
        RECT  0 60.432 0.084 60.456 ;
    END
  END d[432]
  PIN d[433]
    DIRECTION INPUT ;
    USE SIGNAL ;
    PORT
      LAYER M4 ;
        RECT  0 60.528 0.084 60.552 ;
    END
  END d[433]
  PIN d[434]
    DIRECTION INPUT ;
    USE SIGNAL ;
    PORT
      LAYER M4 ;
        RECT  0 60.624 0.084 60.648 ;
    END
  END d[434]
  PIN d[435]
    DIRECTION INPUT ;
    USE SIGNAL ;
    PORT
      LAYER M4 ;
        RECT  0 60.72 0.084 60.744 ;
    END
  END d[435]
  PIN d[436]
    DIRECTION INPUT ;
    USE SIGNAL ;
    PORT
      LAYER M4 ;
        RECT  0 60.816 0.084 60.84 ;
    END
  END d[436]
  PIN d[437]
    DIRECTION INPUT ;
    USE SIGNAL ;
    PORT
      LAYER M4 ;
        RECT  0 60.912 0.084 60.936 ;
    END
  END d[437]
  PIN d[438]
    DIRECTION INPUT ;
    USE SIGNAL ;
    PORT
      LAYER M4 ;
        RECT  0 61.008 0.084 61.032 ;
    END
  END d[438]
  PIN d[439]
    DIRECTION INPUT ;
    USE SIGNAL ;
    PORT
      LAYER M4 ;
        RECT  0 61.104 0.084 61.128 ;
    END
  END d[439]
  PIN d[43]
    DIRECTION INPUT ;
    USE SIGNAL ;
    PORT
      LAYER M4 ;
        RECT  0 85.296 0.084 85.32 ;
    END
  END d[43]
  PIN d[440]
    DIRECTION INPUT ;
    USE SIGNAL ;
    PORT
      LAYER M4 ;
        RECT  0 61.2 0.084 61.224 ;
    END
  END d[440]
  PIN d[441]
    DIRECTION INPUT ;
    USE SIGNAL ;
    PORT
      LAYER M4 ;
        RECT  0 61.296 0.084 61.32 ;
    END
  END d[441]
  PIN d[442]
    DIRECTION INPUT ;
    USE SIGNAL ;
    PORT
      LAYER M4 ;
        RECT  0 61.392 0.084 61.416 ;
    END
  END d[442]
  PIN d[443]
    DIRECTION INPUT ;
    USE SIGNAL ;
    PORT
      LAYER M4 ;
        RECT  0 61.488 0.084 61.512 ;
    END
  END d[443]
  PIN d[444]
    DIRECTION INPUT ;
    USE SIGNAL ;
    PORT
      LAYER M4 ;
        RECT  0 61.584 0.084 61.608 ;
    END
  END d[444]
  PIN d[445]
    DIRECTION INPUT ;
    USE SIGNAL ;
    PORT
      LAYER M4 ;
        RECT  0 61.68 0.084 61.704 ;
    END
  END d[445]
  PIN d[446]
    DIRECTION INPUT ;
    USE SIGNAL ;
    PORT
      LAYER M4 ;
        RECT  0 61.776 0.084 61.8 ;
    END
  END d[446]
  PIN d[447]
    DIRECTION INPUT ;
    USE SIGNAL ;
    PORT
      LAYER M4 ;
        RECT  0 61.872 0.084 61.896 ;
    END
  END d[447]
  PIN d[448]
    DIRECTION INPUT ;
    USE SIGNAL ;
    PORT
      LAYER M4 ;
        RECT  0 61.968 0.084 61.992 ;
    END
  END d[448]
  PIN d[449]
    DIRECTION INPUT ;
    USE SIGNAL ;
    PORT
      LAYER M4 ;
        RECT  0 62.064 0.084 62.088 ;
    END
  END d[449]
  PIN d[44]
    DIRECTION INPUT ;
    USE SIGNAL ;
    PORT
      LAYER M4 ;
        RECT  0 85.392 0.084 85.416 ;
    END
  END d[44]
  PIN d[450]
    DIRECTION INPUT ;
    USE SIGNAL ;
    PORT
      LAYER M4 ;
        RECT  0 62.16 0.084 62.184 ;
    END
  END d[450]
  PIN d[451]
    DIRECTION INPUT ;
    USE SIGNAL ;
    PORT
      LAYER M4 ;
        RECT  0 62.256 0.084 62.28 ;
    END
  END d[451]
  PIN d[452]
    DIRECTION INPUT ;
    USE SIGNAL ;
    PORT
      LAYER M4 ;
        RECT  0 62.352 0.084 62.376 ;
    END
  END d[452]
  PIN d[453]
    DIRECTION INPUT ;
    USE SIGNAL ;
    PORT
      LAYER M4 ;
        RECT  0 62.448 0.084 62.472 ;
    END
  END d[453]
  PIN d[454]
    DIRECTION INPUT ;
    USE SIGNAL ;
    PORT
      LAYER M4 ;
        RECT  0 62.544 0.084 62.568 ;
    END
  END d[454]
  PIN d[455]
    DIRECTION INPUT ;
    USE SIGNAL ;
    PORT
      LAYER M4 ;
        RECT  0 62.64 0.084 62.664 ;
    END
  END d[455]
  PIN d[456]
    DIRECTION INPUT ;
    USE SIGNAL ;
    PORT
      LAYER M4 ;
        RECT  0 62.736 0.084 62.76 ;
    END
  END d[456]
  PIN d[457]
    DIRECTION INPUT ;
    USE SIGNAL ;
    PORT
      LAYER M4 ;
        RECT  0 62.832 0.084 62.856 ;
    END
  END d[457]
  PIN d[458]
    DIRECTION INPUT ;
    USE SIGNAL ;
    PORT
      LAYER M4 ;
        RECT  0 62.928 0.084 62.952 ;
    END
  END d[458]
  PIN d[459]
    DIRECTION INPUT ;
    USE SIGNAL ;
    PORT
      LAYER M4 ;
        RECT  0 63.024 0.084 63.048 ;
    END
  END d[459]
  PIN d[45]
    DIRECTION INPUT ;
    USE SIGNAL ;
    PORT
      LAYER M4 ;
        RECT  0 85.488 0.084 85.512 ;
    END
  END d[45]
  PIN d[460]
    DIRECTION INPUT ;
    USE SIGNAL ;
    PORT
      LAYER M4 ;
        RECT  0 63.12 0.084 63.144 ;
    END
  END d[460]
  PIN d[461]
    DIRECTION INPUT ;
    USE SIGNAL ;
    PORT
      LAYER M4 ;
        RECT  0 63.216 0.084 63.24 ;
    END
  END d[461]
  PIN d[462]
    DIRECTION INPUT ;
    USE SIGNAL ;
    PORT
      LAYER M4 ;
        RECT  0 63.312 0.084 63.336 ;
    END
  END d[462]
  PIN d[463]
    DIRECTION INPUT ;
    USE SIGNAL ;
    PORT
      LAYER M4 ;
        RECT  0 63.408 0.084 63.432 ;
    END
  END d[463]
  PIN d[464]
    DIRECTION INPUT ;
    USE SIGNAL ;
    PORT
      LAYER M4 ;
        RECT  0 63.504 0.084 63.528 ;
    END
  END d[464]
  PIN d[465]
    DIRECTION INPUT ;
    USE SIGNAL ;
    PORT
      LAYER M4 ;
        RECT  0 63.6 0.084 63.624 ;
    END
  END d[465]
  PIN d[466]
    DIRECTION INPUT ;
    USE SIGNAL ;
    PORT
      LAYER M4 ;
        RECT  0 63.696 0.084 63.72 ;
    END
  END d[466]
  PIN d[467]
    DIRECTION INPUT ;
    USE SIGNAL ;
    PORT
      LAYER M4 ;
        RECT  0 63.792 0.084 63.816 ;
    END
  END d[467]
  PIN d[468]
    DIRECTION INPUT ;
    USE SIGNAL ;
    PORT
      LAYER M4 ;
        RECT  0 63.888 0.084 63.912 ;
    END
  END d[468]
  PIN d[469]
    DIRECTION INPUT ;
    USE SIGNAL ;
    PORT
      LAYER M4 ;
        RECT  0 63.984 0.084 64.008 ;
    END
  END d[469]
  PIN d[46]
    DIRECTION INPUT ;
    USE SIGNAL ;
    PORT
      LAYER M4 ;
        RECT  0 85.584 0.084 85.608 ;
    END
  END d[46]
  PIN d[470]
    DIRECTION INPUT ;
    USE SIGNAL ;
    PORT
      LAYER M4 ;
        RECT  0 64.08 0.084 64.104 ;
    END
  END d[470]
  PIN d[471]
    DIRECTION INPUT ;
    USE SIGNAL ;
    PORT
      LAYER M4 ;
        RECT  0 64.176 0.084 64.2 ;
    END
  END d[471]
  PIN d[472]
    DIRECTION INPUT ;
    USE SIGNAL ;
    PORT
      LAYER M4 ;
        RECT  0 64.272 0.084 64.296 ;
    END
  END d[472]
  PIN d[473]
    DIRECTION INPUT ;
    USE SIGNAL ;
    PORT
      LAYER M4 ;
        RECT  0 64.368 0.084 64.392 ;
    END
  END d[473]
  PIN d[474]
    DIRECTION INPUT ;
    USE SIGNAL ;
    PORT
      LAYER M4 ;
        RECT  0 64.464 0.084 64.488 ;
    END
  END d[474]
  PIN d[475]
    DIRECTION INPUT ;
    USE SIGNAL ;
    PORT
      LAYER M4 ;
        RECT  0 64.56 0.084 64.584 ;
    END
  END d[475]
  PIN d[476]
    DIRECTION INPUT ;
    USE SIGNAL ;
    PORT
      LAYER M4 ;
        RECT  0 64.656 0.084 64.68 ;
    END
  END d[476]
  PIN d[477]
    DIRECTION INPUT ;
    USE SIGNAL ;
    PORT
      LAYER M4 ;
        RECT  0 64.752 0.084 64.776 ;
    END
  END d[477]
  PIN d[478]
    DIRECTION INPUT ;
    USE SIGNAL ;
    PORT
      LAYER M4 ;
        RECT  0 64.848 0.084 64.872 ;
    END
  END d[478]
  PIN d[479]
    DIRECTION INPUT ;
    USE SIGNAL ;
    PORT
      LAYER M4 ;
        RECT  0 64.944 0.084 64.968 ;
    END
  END d[479]
  PIN d[47]
    DIRECTION INPUT ;
    USE SIGNAL ;
    PORT
      LAYER M4 ;
        RECT  0 85.68 0.084 85.704 ;
    END
  END d[47]
  PIN d[48]
    DIRECTION INPUT ;
    USE SIGNAL ;
    PORT
      LAYER M4 ;
        RECT  0 85.776 0.084 85.8 ;
    END
  END d[48]
  PIN d[49]
    DIRECTION INPUT ;
    USE SIGNAL ;
    PORT
      LAYER M4 ;
        RECT  0 85.872 0.084 85.896 ;
    END
  END d[49]
  PIN d[4]
    DIRECTION INPUT ;
    USE SIGNAL ;
    PORT
      LAYER M4 ;
        RECT  0 81.552 0.084 81.576 ;
    END
  END d[4]
  PIN d[50]
    DIRECTION INPUT ;
    USE SIGNAL ;
    PORT
      LAYER M4 ;
        RECT  0 85.968 0.084 85.992 ;
    END
  END d[50]
  PIN d[51]
    DIRECTION INPUT ;
    USE SIGNAL ;
    PORT
      LAYER M4 ;
        RECT  0 86.064 0.084 86.088 ;
    END
  END d[51]
  PIN d[52]
    DIRECTION INPUT ;
    USE SIGNAL ;
    PORT
      LAYER M4 ;
        RECT  0 86.16 0.084 86.184 ;
    END
  END d[52]
  PIN d[53]
    DIRECTION INPUT ;
    USE SIGNAL ;
    PORT
      LAYER M4 ;
        RECT  0 86.256 0.084 86.28 ;
    END
  END d[53]
  PIN d[54]
    DIRECTION INPUT ;
    USE SIGNAL ;
    PORT
      LAYER M4 ;
        RECT  0 86.352 0.084 86.376 ;
    END
  END d[54]
  PIN d[55]
    DIRECTION INPUT ;
    USE SIGNAL ;
    PORT
      LAYER M4 ;
        RECT  0 86.448 0.084 86.472 ;
    END
  END d[55]
  PIN d[56]
    DIRECTION INPUT ;
    USE SIGNAL ;
    PORT
      LAYER M4 ;
        RECT  0 86.544 0.084 86.568 ;
    END
  END d[56]
  PIN d[57]
    DIRECTION INPUT ;
    USE SIGNAL ;
    PORT
      LAYER M4 ;
        RECT  0 86.64 0.084 86.664 ;
    END
  END d[57]
  PIN d[58]
    DIRECTION INPUT ;
    USE SIGNAL ;
    PORT
      LAYER M4 ;
        RECT  0 86.736 0.084 86.76 ;
    END
  END d[58]
  PIN d[59]
    DIRECTION INPUT ;
    USE SIGNAL ;
    PORT
      LAYER M4 ;
        RECT  0 86.832 0.084 86.856 ;
    END
  END d[59]
  PIN d[5]
    DIRECTION INPUT ;
    USE SIGNAL ;
    PORT
      LAYER M4 ;
        RECT  0 81.648 0.084 81.672 ;
    END
  END d[5]
  PIN d[60]
    DIRECTION INPUT ;
    USE SIGNAL ;
    PORT
      LAYER M4 ;
        RECT  0 86.928 0.084 86.952 ;
    END
  END d[60]
  PIN d[61]
    DIRECTION INPUT ;
    USE SIGNAL ;
    PORT
      LAYER M4 ;
        RECT  0 87.024 0.084 87.048 ;
    END
  END d[61]
  PIN d[62]
    DIRECTION INPUT ;
    USE SIGNAL ;
    PORT
      LAYER M4 ;
        RECT  0 87.12 0.084 87.144 ;
    END
  END d[62]
  PIN d[63]
    DIRECTION INPUT ;
    USE SIGNAL ;
    PORT
      LAYER M4 ;
        RECT  0 87.216 0.084 87.24 ;
    END
  END d[63]
  PIN d[64]
    DIRECTION INPUT ;
    USE SIGNAL ;
    PORT
      LAYER M4 ;
        RECT  0 71.184 0.084 71.208 ;
    END
  END d[64]
  PIN d[65]
    DIRECTION INPUT ;
    USE SIGNAL ;
    PORT
      LAYER M4 ;
        RECT  0 71.28 0.084 71.304 ;
    END
  END d[65]
  PIN d[66]
    DIRECTION INPUT ;
    USE SIGNAL ;
    PORT
      LAYER M4 ;
        RECT  0 71.376 0.084 71.4 ;
    END
  END d[66]
  PIN d[67]
    DIRECTION INPUT ;
    USE SIGNAL ;
    PORT
      LAYER M4 ;
        RECT  0 71.472 0.084 71.496 ;
    END
  END d[67]
  PIN d[68]
    DIRECTION INPUT ;
    USE SIGNAL ;
    PORT
      LAYER M4 ;
        RECT  0 71.568 0.084 71.592 ;
    END
  END d[68]
  PIN d[69]
    DIRECTION INPUT ;
    USE SIGNAL ;
    PORT
      LAYER M4 ;
        RECT  0 71.664 0.084 71.688 ;
    END
  END d[69]
  PIN d[6]
    DIRECTION INPUT ;
    USE SIGNAL ;
    PORT
      LAYER M4 ;
        RECT  0 81.744 0.084 81.768 ;
    END
  END d[6]
  PIN d[70]
    DIRECTION INPUT ;
    USE SIGNAL ;
    PORT
      LAYER M4 ;
        RECT  0 71.76 0.084 71.784 ;
    END
  END d[70]
  PIN d[71]
    DIRECTION INPUT ;
    USE SIGNAL ;
    PORT
      LAYER M4 ;
        RECT  0 71.856 0.084 71.88 ;
    END
  END d[71]
  PIN d[72]
    DIRECTION INPUT ;
    USE SIGNAL ;
    PORT
      LAYER M4 ;
        RECT  0 71.952 0.084 71.976 ;
    END
  END d[72]
  PIN d[73]
    DIRECTION INPUT ;
    USE SIGNAL ;
    PORT
      LAYER M4 ;
        RECT  0 72.048 0.084 72.072 ;
    END
  END d[73]
  PIN d[74]
    DIRECTION INPUT ;
    USE SIGNAL ;
    PORT
      LAYER M4 ;
        RECT  0 72.144 0.084 72.168 ;
    END
  END d[74]
  PIN d[75]
    DIRECTION INPUT ;
    USE SIGNAL ;
    PORT
      LAYER M4 ;
        RECT  0 72.24 0.084 72.264 ;
    END
  END d[75]
  PIN d[76]
    DIRECTION INPUT ;
    USE SIGNAL ;
    PORT
      LAYER M4 ;
        RECT  0 72.336 0.084 72.36 ;
    END
  END d[76]
  PIN d[77]
    DIRECTION INPUT ;
    USE SIGNAL ;
    PORT
      LAYER M4 ;
        RECT  0 72.432 0.084 72.456 ;
    END
  END d[77]
  PIN d[78]
    DIRECTION INPUT ;
    USE SIGNAL ;
    PORT
      LAYER M4 ;
        RECT  0 72.528 0.084 72.552 ;
    END
  END d[78]
  PIN d[79]
    DIRECTION INPUT ;
    USE SIGNAL ;
    PORT
      LAYER M4 ;
        RECT  0 72.624 0.084 72.648 ;
    END
  END d[79]
  PIN d[7]
    DIRECTION INPUT ;
    USE SIGNAL ;
    PORT
      LAYER M4 ;
        RECT  0 81.84 0.084 81.864 ;
    END
  END d[7]
  PIN d[80]
    DIRECTION INPUT ;
    USE SIGNAL ;
    PORT
      LAYER M4 ;
        RECT  0 72.72 0.084 72.744 ;
    END
  END d[80]
  PIN d[81]
    DIRECTION INPUT ;
    USE SIGNAL ;
    PORT
      LAYER M4 ;
        RECT  0 72.816 0.084 72.84 ;
    END
  END d[81]
  PIN d[82]
    DIRECTION INPUT ;
    USE SIGNAL ;
    PORT
      LAYER M4 ;
        RECT  0 72.912 0.084 72.936 ;
    END
  END d[82]
  PIN d[83]
    DIRECTION INPUT ;
    USE SIGNAL ;
    PORT
      LAYER M4 ;
        RECT  0 73.008 0.084 73.032 ;
    END
  END d[83]
  PIN d[84]
    DIRECTION INPUT ;
    USE SIGNAL ;
    PORT
      LAYER M4 ;
        RECT  0 73.104 0.084 73.128 ;
    END
  END d[84]
  PIN d[85]
    DIRECTION INPUT ;
    USE SIGNAL ;
    PORT
      LAYER M4 ;
        RECT  0 73.2 0.084 73.224 ;
    END
  END d[85]
  PIN d[86]
    DIRECTION INPUT ;
    USE SIGNAL ;
    PORT
      LAYER M4 ;
        RECT  0 73.296 0.084 73.32 ;
    END
  END d[86]
  PIN d[87]
    DIRECTION INPUT ;
    USE SIGNAL ;
    PORT
      LAYER M4 ;
        RECT  0 73.392 0.084 73.416 ;
    END
  END d[87]
  PIN d[88]
    DIRECTION INPUT ;
    USE SIGNAL ;
    PORT
      LAYER M4 ;
        RECT  0 73.488 0.084 73.512 ;
    END
  END d[88]
  PIN d[89]
    DIRECTION INPUT ;
    USE SIGNAL ;
    PORT
      LAYER M4 ;
        RECT  0 73.584 0.084 73.608 ;
    END
  END d[89]
  PIN d[8]
    DIRECTION INPUT ;
    USE SIGNAL ;
    PORT
      LAYER M4 ;
        RECT  0 81.936 0.084 81.96 ;
    END
  END d[8]
  PIN d[90]
    DIRECTION INPUT ;
    USE SIGNAL ;
    PORT
      LAYER M4 ;
        RECT  0 73.68 0.084 73.704 ;
    END
  END d[90]
  PIN d[91]
    DIRECTION INPUT ;
    USE SIGNAL ;
    PORT
      LAYER M4 ;
        RECT  0 73.776 0.084 73.8 ;
    END
  END d[91]
  PIN d[92]
    DIRECTION INPUT ;
    USE SIGNAL ;
    PORT
      LAYER M4 ;
        RECT  0 73.872 0.084 73.896 ;
    END
  END d[92]
  PIN d[93]
    DIRECTION INPUT ;
    USE SIGNAL ;
    PORT
      LAYER M4 ;
        RECT  0 73.968 0.084 73.992 ;
    END
  END d[93]
  PIN d[94]
    DIRECTION INPUT ;
    USE SIGNAL ;
    PORT
      LAYER M4 ;
        RECT  0 74.064 0.084 74.088 ;
    END
  END d[94]
  PIN d[95]
    DIRECTION INPUT ;
    USE SIGNAL ;
    PORT
      LAYER M4 ;
        RECT  0 74.16 0.084 74.184 ;
    END
  END d[95]
  PIN d[96]
    DIRECTION INPUT ;
    USE SIGNAL ;
    PORT
      LAYER M4 ;
        RECT  0 78.096 0.084 78.12 ;
    END
  END d[96]
  PIN d[97]
    DIRECTION INPUT ;
    USE SIGNAL ;
    PORT
      LAYER M4 ;
        RECT  0 78.192 0.084 78.216 ;
    END
  END d[97]
  PIN d[98]
    DIRECTION INPUT ;
    USE SIGNAL ;
    PORT
      LAYER M4 ;
        RECT  0 78.288 0.084 78.312 ;
    END
  END d[98]
  PIN d[99]
    DIRECTION INPUT ;
    USE SIGNAL ;
    PORT
      LAYER M4 ;
        RECT  0 78.384 0.084 78.408 ;
    END
  END d[99]
  PIN d[9]
    DIRECTION INPUT ;
    USE SIGNAL ;
    PORT
      LAYER M4 ;
        RECT  0 82.032 0.084 82.056 ;
    END
  END d[9]
  PIN me_e
    DIRECTION INPUT ;
    USE SIGNAL ;
    PORT
      LAYER M5 ;
        RECT  4.08 0 4.104 0.084 ;
    END
  END me_e
  PIN q[0]
    DIRECTION OUTPUT ;
    USE SIGNAL ;
    PORT
      LAYER M4 ;
        RECT  17.196 89.808 17.28 89.832 ;
    END
  END q[0]
  PIN q[100]
    DIRECTION OUTPUT ;
    USE SIGNAL ;
    PORT
      LAYER M4 ;
        RECT  17.196 77.904 17.28 77.928 ;
    END
  END q[100]
  PIN q[101]
    DIRECTION OUTPUT ;
    USE SIGNAL ;
    PORT
      LAYER M4 ;
        RECT  17.196 78 17.28 78.024 ;
    END
  END q[101]
  PIN q[102]
    DIRECTION OUTPUT ;
    USE SIGNAL ;
    PORT
      LAYER M4 ;
        RECT  17.196 78.096 17.28 78.12 ;
    END
  END q[102]
  PIN q[103]
    DIRECTION OUTPUT ;
    USE SIGNAL ;
    PORT
      LAYER M4 ;
        RECT  17.196 78.192 17.28 78.216 ;
    END
  END q[103]
  PIN q[104]
    DIRECTION OUTPUT ;
    USE SIGNAL ;
    PORT
      LAYER M4 ;
        RECT  17.196 78.288 17.28 78.312 ;
    END
  END q[104]
  PIN q[105]
    DIRECTION OUTPUT ;
    USE SIGNAL ;
    PORT
      LAYER M4 ;
        RECT  17.196 78.384 17.28 78.408 ;
    END
  END q[105]
  PIN q[106]
    DIRECTION OUTPUT ;
    USE SIGNAL ;
    PORT
      LAYER M4 ;
        RECT  17.196 78.48 17.28 78.504 ;
    END
  END q[106]
  PIN q[107]
    DIRECTION OUTPUT ;
    USE SIGNAL ;
    PORT
      LAYER M4 ;
        RECT  17.196 78.576 17.28 78.6 ;
    END
  END q[107]
  PIN q[108]
    DIRECTION OUTPUT ;
    USE SIGNAL ;
    PORT
      LAYER M4 ;
        RECT  17.196 78.672 17.28 78.696 ;
    END
  END q[108]
  PIN q[109]
    DIRECTION OUTPUT ;
    USE SIGNAL ;
    PORT
      LAYER M4 ;
        RECT  17.196 78.768 17.28 78.792 ;
    END
  END q[109]
  PIN q[10]
    DIRECTION OUTPUT ;
    USE SIGNAL ;
    PORT
      LAYER M4 ;
        RECT  17.196 90.768 17.28 90.792 ;
    END
  END q[10]
  PIN q[110]
    DIRECTION OUTPUT ;
    USE SIGNAL ;
    PORT
      LAYER M4 ;
        RECT  17.196 78.864 17.28 78.888 ;
    END
  END q[110]
  PIN q[111]
    DIRECTION OUTPUT ;
    USE SIGNAL ;
    PORT
      LAYER M4 ;
        RECT  17.196 78.96 17.28 78.984 ;
    END
  END q[111]
  PIN q[112]
    DIRECTION OUTPUT ;
    USE SIGNAL ;
    PORT
      LAYER M4 ;
        RECT  17.196 79.056 17.28 79.08 ;
    END
  END q[112]
  PIN q[113]
    DIRECTION OUTPUT ;
    USE SIGNAL ;
    PORT
      LAYER M4 ;
        RECT  17.196 79.152 17.28 79.176 ;
    END
  END q[113]
  PIN q[114]
    DIRECTION OUTPUT ;
    USE SIGNAL ;
    PORT
      LAYER M4 ;
        RECT  17.196 79.248 17.28 79.272 ;
    END
  END q[114]
  PIN q[115]
    DIRECTION OUTPUT ;
    USE SIGNAL ;
    PORT
      LAYER M4 ;
        RECT  17.196 79.344 17.28 79.368 ;
    END
  END q[115]
  PIN q[116]
    DIRECTION OUTPUT ;
    USE SIGNAL ;
    PORT
      LAYER M4 ;
        RECT  17.196 79.44 17.28 79.464 ;
    END
  END q[116]
  PIN q[117]
    DIRECTION OUTPUT ;
    USE SIGNAL ;
    PORT
      LAYER M4 ;
        RECT  17.196 79.536 17.28 79.56 ;
    END
  END q[117]
  PIN q[118]
    DIRECTION OUTPUT ;
    USE SIGNAL ;
    PORT
      LAYER M4 ;
        RECT  17.196 79.632 17.28 79.656 ;
    END
  END q[118]
  PIN q[119]
    DIRECTION OUTPUT ;
    USE SIGNAL ;
    PORT
      LAYER M4 ;
        RECT  17.196 79.728 17.28 79.752 ;
    END
  END q[119]
  PIN q[11]
    DIRECTION OUTPUT ;
    USE SIGNAL ;
    PORT
      LAYER M4 ;
        RECT  17.196 90.864 17.28 90.888 ;
    END
  END q[11]
  PIN q[120]
    DIRECTION OUTPUT ;
    USE SIGNAL ;
    PORT
      LAYER M4 ;
        RECT  17.196 79.824 17.28 79.848 ;
    END
  END q[120]
  PIN q[121]
    DIRECTION OUTPUT ;
    USE SIGNAL ;
    PORT
      LAYER M4 ;
        RECT  17.196 79.92 17.28 79.944 ;
    END
  END q[121]
  PIN q[122]
    DIRECTION OUTPUT ;
    USE SIGNAL ;
    PORT
      LAYER M4 ;
        RECT  17.196 80.016 17.28 80.04 ;
    END
  END q[122]
  PIN q[123]
    DIRECTION OUTPUT ;
    USE SIGNAL ;
    PORT
      LAYER M4 ;
        RECT  17.196 80.112 17.28 80.136 ;
    END
  END q[123]
  PIN q[124]
    DIRECTION OUTPUT ;
    USE SIGNAL ;
    PORT
      LAYER M4 ;
        RECT  17.196 80.208 17.28 80.232 ;
    END
  END q[124]
  PIN q[125]
    DIRECTION OUTPUT ;
    USE SIGNAL ;
    PORT
      LAYER M4 ;
        RECT  17.196 80.304 17.28 80.328 ;
    END
  END q[125]
  PIN q[126]
    DIRECTION OUTPUT ;
    USE SIGNAL ;
    PORT
      LAYER M4 ;
        RECT  17.196 80.4 17.28 80.424 ;
    END
  END q[126]
  PIN q[127]
    DIRECTION OUTPUT ;
    USE SIGNAL ;
    PORT
      LAYER M4 ;
        RECT  17.196 80.496 17.28 80.52 ;
    END
  END q[127]
  PIN q[128]
    DIRECTION OUTPUT ;
    USE SIGNAL ;
    PORT
      LAYER M4 ;
        RECT  17.196 6.864 17.28 6.888 ;
    END
  END q[128]
  PIN q[129]
    DIRECTION OUTPUT ;
    USE SIGNAL ;
    PORT
      LAYER M4 ;
        RECT  17.196 6.96 17.28 6.984 ;
    END
  END q[129]
  PIN q[12]
    DIRECTION OUTPUT ;
    USE SIGNAL ;
    PORT
      LAYER M4 ;
        RECT  17.196 90.96 17.28 90.984 ;
    END
  END q[12]
  PIN q[130]
    DIRECTION OUTPUT ;
    USE SIGNAL ;
    PORT
      LAYER M4 ;
        RECT  17.196 7.056 17.28 7.08 ;
    END
  END q[130]
  PIN q[131]
    DIRECTION OUTPUT ;
    USE SIGNAL ;
    PORT
      LAYER M4 ;
        RECT  17.196 7.152 17.28 7.176 ;
    END
  END q[131]
  PIN q[132]
    DIRECTION OUTPUT ;
    USE SIGNAL ;
    PORT
      LAYER M4 ;
        RECT  17.196 7.248 17.28 7.272 ;
    END
  END q[132]
  PIN q[133]
    DIRECTION OUTPUT ;
    USE SIGNAL ;
    PORT
      LAYER M4 ;
        RECT  17.196 7.344 17.28 7.368 ;
    END
  END q[133]
  PIN q[134]
    DIRECTION OUTPUT ;
    USE SIGNAL ;
    PORT
      LAYER M4 ;
        RECT  17.196 7.44 17.28 7.464 ;
    END
  END q[134]
  PIN q[135]
    DIRECTION OUTPUT ;
    USE SIGNAL ;
    PORT
      LAYER M4 ;
        RECT  17.196 7.536 17.28 7.56 ;
    END
  END q[135]
  PIN q[136]
    DIRECTION OUTPUT ;
    USE SIGNAL ;
    PORT
      LAYER M4 ;
        RECT  17.196 7.632 17.28 7.656 ;
    END
  END q[136]
  PIN q[137]
    DIRECTION OUTPUT ;
    USE SIGNAL ;
    PORT
      LAYER M4 ;
        RECT  17.196 7.728 17.28 7.752 ;
    END
  END q[137]
  PIN q[138]
    DIRECTION OUTPUT ;
    USE SIGNAL ;
    PORT
      LAYER M4 ;
        RECT  17.196 7.824 17.28 7.848 ;
    END
  END q[138]
  PIN q[139]
    DIRECTION OUTPUT ;
    USE SIGNAL ;
    PORT
      LAYER M4 ;
        RECT  17.196 7.92 17.28 7.944 ;
    END
  END q[139]
  PIN q[13]
    DIRECTION OUTPUT ;
    USE SIGNAL ;
    PORT
      LAYER M4 ;
        RECT  17.196 91.056 17.28 91.08 ;
    END
  END q[13]
  PIN q[140]
    DIRECTION OUTPUT ;
    USE SIGNAL ;
    PORT
      LAYER M4 ;
        RECT  17.196 8.016 17.28 8.04 ;
    END
  END q[140]
  PIN q[141]
    DIRECTION OUTPUT ;
    USE SIGNAL ;
    PORT
      LAYER M4 ;
        RECT  17.196 8.112 17.28 8.136 ;
    END
  END q[141]
  PIN q[142]
    DIRECTION OUTPUT ;
    USE SIGNAL ;
    PORT
      LAYER M4 ;
        RECT  17.196 8.208 17.28 8.232 ;
    END
  END q[142]
  PIN q[143]
    DIRECTION OUTPUT ;
    USE SIGNAL ;
    PORT
      LAYER M4 ;
        RECT  17.196 8.304 17.28 8.328 ;
    END
  END q[143]
  PIN q[144]
    DIRECTION OUTPUT ;
    USE SIGNAL ;
    PORT
      LAYER M4 ;
        RECT  17.196 8.4 17.28 8.424 ;
    END
  END q[144]
  PIN q[145]
    DIRECTION OUTPUT ;
    USE SIGNAL ;
    PORT
      LAYER M4 ;
        RECT  17.196 8.496 17.28 8.52 ;
    END
  END q[145]
  PIN q[146]
    DIRECTION OUTPUT ;
    USE SIGNAL ;
    PORT
      LAYER M4 ;
        RECT  17.196 8.592 17.28 8.616 ;
    END
  END q[146]
  PIN q[147]
    DIRECTION OUTPUT ;
    USE SIGNAL ;
    PORT
      LAYER M4 ;
        RECT  17.196 8.688 17.28 8.712 ;
    END
  END q[147]
  PIN q[148]
    DIRECTION OUTPUT ;
    USE SIGNAL ;
    PORT
      LAYER M4 ;
        RECT  17.196 8.784 17.28 8.808 ;
    END
  END q[148]
  PIN q[149]
    DIRECTION OUTPUT ;
    USE SIGNAL ;
    PORT
      LAYER M4 ;
        RECT  17.196 8.88 17.28 8.904 ;
    END
  END q[149]
  PIN q[14]
    DIRECTION OUTPUT ;
    USE SIGNAL ;
    PORT
      LAYER M4 ;
        RECT  17.196 91.152 17.28 91.176 ;
    END
  END q[14]
  PIN q[150]
    DIRECTION OUTPUT ;
    USE SIGNAL ;
    PORT
      LAYER M4 ;
        RECT  17.196 8.976 17.28 9 ;
    END
  END q[150]
  PIN q[151]
    DIRECTION OUTPUT ;
    USE SIGNAL ;
    PORT
      LAYER M4 ;
        RECT  17.196 9.072 17.28 9.096 ;
    END
  END q[151]
  PIN q[152]
    DIRECTION OUTPUT ;
    USE SIGNAL ;
    PORT
      LAYER M4 ;
        RECT  17.196 9.168 17.28 9.192 ;
    END
  END q[152]
  PIN q[153]
    DIRECTION OUTPUT ;
    USE SIGNAL ;
    PORT
      LAYER M4 ;
        RECT  17.196 9.264 17.28 9.288 ;
    END
  END q[153]
  PIN q[154]
    DIRECTION OUTPUT ;
    USE SIGNAL ;
    PORT
      LAYER M4 ;
        RECT  17.196 9.36 17.28 9.384 ;
    END
  END q[154]
  PIN q[155]
    DIRECTION OUTPUT ;
    USE SIGNAL ;
    PORT
      LAYER M4 ;
        RECT  17.196 9.456 17.28 9.48 ;
    END
  END q[155]
  PIN q[156]
    DIRECTION OUTPUT ;
    USE SIGNAL ;
    PORT
      LAYER M4 ;
        RECT  17.196 9.552 17.28 9.576 ;
    END
  END q[156]
  PIN q[157]
    DIRECTION OUTPUT ;
    USE SIGNAL ;
    PORT
      LAYER M4 ;
        RECT  17.196 9.648 17.28 9.672 ;
    END
  END q[157]
  PIN q[158]
    DIRECTION OUTPUT ;
    USE SIGNAL ;
    PORT
      LAYER M4 ;
        RECT  17.196 9.744 17.28 9.768 ;
    END
  END q[158]
  PIN q[159]
    DIRECTION OUTPUT ;
    USE SIGNAL ;
    PORT
      LAYER M4 ;
        RECT  17.196 9.84 17.28 9.864 ;
    END
  END q[159]
  PIN q[15]
    DIRECTION OUTPUT ;
    USE SIGNAL ;
    PORT
      LAYER M4 ;
        RECT  17.196 91.248 17.28 91.272 ;
    END
  END q[15]
  PIN q[160]
    DIRECTION OUTPUT ;
    USE SIGNAL ;
    PORT
      LAYER M4 ;
        RECT  17.196 9.936 17.28 9.96 ;
    END
  END q[160]
  PIN q[161]
    DIRECTION OUTPUT ;
    USE SIGNAL ;
    PORT
      LAYER M4 ;
        RECT  17.196 10.032 17.28 10.056 ;
    END
  END q[161]
  PIN q[162]
    DIRECTION OUTPUT ;
    USE SIGNAL ;
    PORT
      LAYER M4 ;
        RECT  17.196 10.128 17.28 10.152 ;
    END
  END q[162]
  PIN q[163]
    DIRECTION OUTPUT ;
    USE SIGNAL ;
    PORT
      LAYER M4 ;
        RECT  17.196 10.224 17.28 10.248 ;
    END
  END q[163]
  PIN q[164]
    DIRECTION OUTPUT ;
    USE SIGNAL ;
    PORT
      LAYER M4 ;
        RECT  17.196 10.32 17.28 10.344 ;
    END
  END q[164]
  PIN q[165]
    DIRECTION OUTPUT ;
    USE SIGNAL ;
    PORT
      LAYER M4 ;
        RECT  17.196 10.416 17.28 10.44 ;
    END
  END q[165]
  PIN q[166]
    DIRECTION OUTPUT ;
    USE SIGNAL ;
    PORT
      LAYER M4 ;
        RECT  17.196 10.512 17.28 10.536 ;
    END
  END q[166]
  PIN q[167]
    DIRECTION OUTPUT ;
    USE SIGNAL ;
    PORT
      LAYER M4 ;
        RECT  17.196 10.608 17.28 10.632 ;
    END
  END q[167]
  PIN q[168]
    DIRECTION OUTPUT ;
    USE SIGNAL ;
    PORT
      LAYER M4 ;
        RECT  17.196 10.704 17.28 10.728 ;
    END
  END q[168]
  PIN q[169]
    DIRECTION OUTPUT ;
    USE SIGNAL ;
    PORT
      LAYER M4 ;
        RECT  17.196 10.8 17.28 10.824 ;
    END
  END q[169]
  PIN q[16]
    DIRECTION OUTPUT ;
    USE SIGNAL ;
    PORT
      LAYER M4 ;
        RECT  17.196 91.344 17.28 91.368 ;
    END
  END q[16]
  PIN q[170]
    DIRECTION OUTPUT ;
    USE SIGNAL ;
    PORT
      LAYER M4 ;
        RECT  17.196 10.896 17.28 10.92 ;
    END
  END q[170]
  PIN q[171]
    DIRECTION OUTPUT ;
    USE SIGNAL ;
    PORT
      LAYER M4 ;
        RECT  17.196 10.992 17.28 11.016 ;
    END
  END q[171]
  PIN q[172]
    DIRECTION OUTPUT ;
    USE SIGNAL ;
    PORT
      LAYER M4 ;
        RECT  17.196 11.088 17.28 11.112 ;
    END
  END q[172]
  PIN q[173]
    DIRECTION OUTPUT ;
    USE SIGNAL ;
    PORT
      LAYER M4 ;
        RECT  17.196 11.184 17.28 11.208 ;
    END
  END q[173]
  PIN q[174]
    DIRECTION OUTPUT ;
    USE SIGNAL ;
    PORT
      LAYER M4 ;
        RECT  17.196 11.28 17.28 11.304 ;
    END
  END q[174]
  PIN q[175]
    DIRECTION OUTPUT ;
    USE SIGNAL ;
    PORT
      LAYER M4 ;
        RECT  17.196 11.376 17.28 11.4 ;
    END
  END q[175]
  PIN q[176]
    DIRECTION OUTPUT ;
    USE SIGNAL ;
    PORT
      LAYER M4 ;
        RECT  17.196 11.472 17.28 11.496 ;
    END
  END q[176]
  PIN q[177]
    DIRECTION OUTPUT ;
    USE SIGNAL ;
    PORT
      LAYER M4 ;
        RECT  17.196 11.568 17.28 11.592 ;
    END
  END q[177]
  PIN q[178]
    DIRECTION OUTPUT ;
    USE SIGNAL ;
    PORT
      LAYER M4 ;
        RECT  17.196 11.664 17.28 11.688 ;
    END
  END q[178]
  PIN q[179]
    DIRECTION OUTPUT ;
    USE SIGNAL ;
    PORT
      LAYER M4 ;
        RECT  17.196 11.76 17.28 11.784 ;
    END
  END q[179]
  PIN q[17]
    DIRECTION OUTPUT ;
    USE SIGNAL ;
    PORT
      LAYER M4 ;
        RECT  17.196 91.44 17.28 91.464 ;
    END
  END q[17]
  PIN q[180]
    DIRECTION OUTPUT ;
    USE SIGNAL ;
    PORT
      LAYER M4 ;
        RECT  17.196 11.856 17.28 11.88 ;
    END
  END q[180]
  PIN q[181]
    DIRECTION OUTPUT ;
    USE SIGNAL ;
    PORT
      LAYER M4 ;
        RECT  17.196 11.952 17.28 11.976 ;
    END
  END q[181]
  PIN q[182]
    DIRECTION OUTPUT ;
    USE SIGNAL ;
    PORT
      LAYER M4 ;
        RECT  17.196 12.048 17.28 12.072 ;
    END
  END q[182]
  PIN q[183]
    DIRECTION OUTPUT ;
    USE SIGNAL ;
    PORT
      LAYER M4 ;
        RECT  17.196 12.144 17.28 12.168 ;
    END
  END q[183]
  PIN q[184]
    DIRECTION OUTPUT ;
    USE SIGNAL ;
    PORT
      LAYER M4 ;
        RECT  17.196 12.24 17.28 12.264 ;
    END
  END q[184]
  PIN q[185]
    DIRECTION OUTPUT ;
    USE SIGNAL ;
    PORT
      LAYER M4 ;
        RECT  17.196 12.336 17.28 12.36 ;
    END
  END q[185]
  PIN q[186]
    DIRECTION OUTPUT ;
    USE SIGNAL ;
    PORT
      LAYER M4 ;
        RECT  17.196 12.432 17.28 12.456 ;
    END
  END q[186]
  PIN q[187]
    DIRECTION OUTPUT ;
    USE SIGNAL ;
    PORT
      LAYER M4 ;
        RECT  17.196 12.528 17.28 12.552 ;
    END
  END q[187]
  PIN q[188]
    DIRECTION OUTPUT ;
    USE SIGNAL ;
    PORT
      LAYER M4 ;
        RECT  17.196 12.624 17.28 12.648 ;
    END
  END q[188]
  PIN q[189]
    DIRECTION OUTPUT ;
    USE SIGNAL ;
    PORT
      LAYER M4 ;
        RECT  17.196 12.72 17.28 12.744 ;
    END
  END q[189]
  PIN q[18]
    DIRECTION OUTPUT ;
    USE SIGNAL ;
    PORT
      LAYER M4 ;
        RECT  17.196 91.536 17.28 91.56 ;
    END
  END q[18]
  PIN q[190]
    DIRECTION OUTPUT ;
    USE SIGNAL ;
    PORT
      LAYER M4 ;
        RECT  17.196 12.816 17.28 12.84 ;
    END
  END q[190]
  PIN q[191]
    DIRECTION OUTPUT ;
    USE SIGNAL ;
    PORT
      LAYER M4 ;
        RECT  17.196 12.912 17.28 12.936 ;
    END
  END q[191]
  PIN q[192]
    DIRECTION OUTPUT ;
    USE SIGNAL ;
    PORT
      LAYER M4 ;
        RECT  17.196 22.992 17.28 23.016 ;
    END
  END q[192]
  PIN q[193]
    DIRECTION OUTPUT ;
    USE SIGNAL ;
    PORT
      LAYER M4 ;
        RECT  17.196 23.088 17.28 23.112 ;
    END
  END q[193]
  PIN q[194]
    DIRECTION OUTPUT ;
    USE SIGNAL ;
    PORT
      LAYER M4 ;
        RECT  17.196 23.184 17.28 23.208 ;
    END
  END q[194]
  PIN q[195]
    DIRECTION OUTPUT ;
    USE SIGNAL ;
    PORT
      LAYER M4 ;
        RECT  17.196 23.28 17.28 23.304 ;
    END
  END q[195]
  PIN q[196]
    DIRECTION OUTPUT ;
    USE SIGNAL ;
    PORT
      LAYER M4 ;
        RECT  17.196 23.376 17.28 23.4 ;
    END
  END q[196]
  PIN q[197]
    DIRECTION OUTPUT ;
    USE SIGNAL ;
    PORT
      LAYER M4 ;
        RECT  17.196 23.472 17.28 23.496 ;
    END
  END q[197]
  PIN q[198]
    DIRECTION OUTPUT ;
    USE SIGNAL ;
    PORT
      LAYER M4 ;
        RECT  17.196 23.568 17.28 23.592 ;
    END
  END q[198]
  PIN q[199]
    DIRECTION OUTPUT ;
    USE SIGNAL ;
    PORT
      LAYER M4 ;
        RECT  17.196 23.664 17.28 23.688 ;
    END
  END q[199]
  PIN q[19]
    DIRECTION OUTPUT ;
    USE SIGNAL ;
    PORT
      LAYER M4 ;
        RECT  17.196 91.632 17.28 91.656 ;
    END
  END q[19]
  PIN q[1]
    DIRECTION OUTPUT ;
    USE SIGNAL ;
    PORT
      LAYER M4 ;
        RECT  17.196 89.904 17.28 89.928 ;
    END
  END q[1]
  PIN q[200]
    DIRECTION OUTPUT ;
    USE SIGNAL ;
    PORT
      LAYER M4 ;
        RECT  17.196 23.76 17.28 23.784 ;
    END
  END q[200]
  PIN q[201]
    DIRECTION OUTPUT ;
    USE SIGNAL ;
    PORT
      LAYER M4 ;
        RECT  17.196 23.856 17.28 23.88 ;
    END
  END q[201]
  PIN q[202]
    DIRECTION OUTPUT ;
    USE SIGNAL ;
    PORT
      LAYER M4 ;
        RECT  17.196 23.952 17.28 23.976 ;
    END
  END q[202]
  PIN q[203]
    DIRECTION OUTPUT ;
    USE SIGNAL ;
    PORT
      LAYER M4 ;
        RECT  17.196 24.048 17.28 24.072 ;
    END
  END q[203]
  PIN q[204]
    DIRECTION OUTPUT ;
    USE SIGNAL ;
    PORT
      LAYER M4 ;
        RECT  17.196 24.144 17.28 24.168 ;
    END
  END q[204]
  PIN q[205]
    DIRECTION OUTPUT ;
    USE SIGNAL ;
    PORT
      LAYER M4 ;
        RECT  17.196 24.24 17.28 24.264 ;
    END
  END q[205]
  PIN q[206]
    DIRECTION OUTPUT ;
    USE SIGNAL ;
    PORT
      LAYER M4 ;
        RECT  17.196 24.336 17.28 24.36 ;
    END
  END q[206]
  PIN q[207]
    DIRECTION OUTPUT ;
    USE SIGNAL ;
    PORT
      LAYER M4 ;
        RECT  17.196 24.432 17.28 24.456 ;
    END
  END q[207]
  PIN q[208]
    DIRECTION OUTPUT ;
    USE SIGNAL ;
    PORT
      LAYER M4 ;
        RECT  17.196 24.528 17.28 24.552 ;
    END
  END q[208]
  PIN q[209]
    DIRECTION OUTPUT ;
    USE SIGNAL ;
    PORT
      LAYER M4 ;
        RECT  17.196 24.624 17.28 24.648 ;
    END
  END q[209]
  PIN q[20]
    DIRECTION OUTPUT ;
    USE SIGNAL ;
    PORT
      LAYER M4 ;
        RECT  17.196 91.728 17.28 91.752 ;
    END
  END q[20]
  PIN q[210]
    DIRECTION OUTPUT ;
    USE SIGNAL ;
    PORT
      LAYER M4 ;
        RECT  17.196 24.72 17.28 24.744 ;
    END
  END q[210]
  PIN q[211]
    DIRECTION OUTPUT ;
    USE SIGNAL ;
    PORT
      LAYER M4 ;
        RECT  17.196 24.816 17.28 24.84 ;
    END
  END q[211]
  PIN q[212]
    DIRECTION OUTPUT ;
    USE SIGNAL ;
    PORT
      LAYER M4 ;
        RECT  17.196 24.912 17.28 24.936 ;
    END
  END q[212]
  PIN q[213]
    DIRECTION OUTPUT ;
    USE SIGNAL ;
    PORT
      LAYER M4 ;
        RECT  17.196 25.008 17.28 25.032 ;
    END
  END q[213]
  PIN q[214]
    DIRECTION OUTPUT ;
    USE SIGNAL ;
    PORT
      LAYER M4 ;
        RECT  17.196 25.104 17.28 25.128 ;
    END
  END q[214]
  PIN q[215]
    DIRECTION OUTPUT ;
    USE SIGNAL ;
    PORT
      LAYER M4 ;
        RECT  17.196 25.2 17.28 25.224 ;
    END
  END q[215]
  PIN q[216]
    DIRECTION OUTPUT ;
    USE SIGNAL ;
    PORT
      LAYER M4 ;
        RECT  17.196 25.296 17.28 25.32 ;
    END
  END q[216]
  PIN q[217]
    DIRECTION OUTPUT ;
    USE SIGNAL ;
    PORT
      LAYER M4 ;
        RECT  17.196 25.392 17.28 25.416 ;
    END
  END q[217]
  PIN q[218]
    DIRECTION OUTPUT ;
    USE SIGNAL ;
    PORT
      LAYER M4 ;
        RECT  17.196 25.488 17.28 25.512 ;
    END
  END q[218]
  PIN q[219]
    DIRECTION OUTPUT ;
    USE SIGNAL ;
    PORT
      LAYER M4 ;
        RECT  17.196 25.584 17.28 25.608 ;
    END
  END q[219]
  PIN q[21]
    DIRECTION OUTPUT ;
    USE SIGNAL ;
    PORT
      LAYER M4 ;
        RECT  17.196 91.824 17.28 91.848 ;
    END
  END q[21]
  PIN q[220]
    DIRECTION OUTPUT ;
    USE SIGNAL ;
    PORT
      LAYER M4 ;
        RECT  17.196 25.68 17.28 25.704 ;
    END
  END q[220]
  PIN q[221]
    DIRECTION OUTPUT ;
    USE SIGNAL ;
    PORT
      LAYER M4 ;
        RECT  17.196 25.776 17.28 25.8 ;
    END
  END q[221]
  PIN q[222]
    DIRECTION OUTPUT ;
    USE SIGNAL ;
    PORT
      LAYER M4 ;
        RECT  17.196 25.872 17.28 25.896 ;
    END
  END q[222]
  PIN q[223]
    DIRECTION OUTPUT ;
    USE SIGNAL ;
    PORT
      LAYER M4 ;
        RECT  17.196 25.968 17.28 25.992 ;
    END
  END q[223]
  PIN q[224]
    DIRECTION OUTPUT ;
    USE SIGNAL ;
    PORT
      LAYER M4 ;
        RECT  17.196 16.08 17.28 16.104 ;
    END
  END q[224]
  PIN q[225]
    DIRECTION OUTPUT ;
    USE SIGNAL ;
    PORT
      LAYER M4 ;
        RECT  17.196 16.176 17.28 16.2 ;
    END
  END q[225]
  PIN q[226]
    DIRECTION OUTPUT ;
    USE SIGNAL ;
    PORT
      LAYER M4 ;
        RECT  17.196 16.272 17.28 16.296 ;
    END
  END q[226]
  PIN q[227]
    DIRECTION OUTPUT ;
    USE SIGNAL ;
    PORT
      LAYER M4 ;
        RECT  17.196 16.368 17.28 16.392 ;
    END
  END q[227]
  PIN q[228]
    DIRECTION OUTPUT ;
    USE SIGNAL ;
    PORT
      LAYER M4 ;
        RECT  17.196 16.464 17.28 16.488 ;
    END
  END q[228]
  PIN q[229]
    DIRECTION OUTPUT ;
    USE SIGNAL ;
    PORT
      LAYER M4 ;
        RECT  17.196 16.56 17.28 16.584 ;
    END
  END q[229]
  PIN q[22]
    DIRECTION OUTPUT ;
    USE SIGNAL ;
    PORT
      LAYER M4 ;
        RECT  17.196 91.92 17.28 91.944 ;
    END
  END q[22]
  PIN q[230]
    DIRECTION OUTPUT ;
    USE SIGNAL ;
    PORT
      LAYER M4 ;
        RECT  17.196 16.656 17.28 16.68 ;
    END
  END q[230]
  PIN q[231]
    DIRECTION OUTPUT ;
    USE SIGNAL ;
    PORT
      LAYER M4 ;
        RECT  17.196 16.752 17.28 16.776 ;
    END
  END q[231]
  PIN q[232]
    DIRECTION OUTPUT ;
    USE SIGNAL ;
    PORT
      LAYER M4 ;
        RECT  17.196 16.848 17.28 16.872 ;
    END
  END q[232]
  PIN q[233]
    DIRECTION OUTPUT ;
    USE SIGNAL ;
    PORT
      LAYER M4 ;
        RECT  17.196 16.944 17.28 16.968 ;
    END
  END q[233]
  PIN q[234]
    DIRECTION OUTPUT ;
    USE SIGNAL ;
    PORT
      LAYER M4 ;
        RECT  17.196 17.04 17.28 17.064 ;
    END
  END q[234]
  PIN q[235]
    DIRECTION OUTPUT ;
    USE SIGNAL ;
    PORT
      LAYER M4 ;
        RECT  17.196 17.136 17.28 17.16 ;
    END
  END q[235]
  PIN q[236]
    DIRECTION OUTPUT ;
    USE SIGNAL ;
    PORT
      LAYER M4 ;
        RECT  17.196 17.232 17.28 17.256 ;
    END
  END q[236]
  PIN q[237]
    DIRECTION OUTPUT ;
    USE SIGNAL ;
    PORT
      LAYER M4 ;
        RECT  17.196 17.328 17.28 17.352 ;
    END
  END q[237]
  PIN q[238]
    DIRECTION OUTPUT ;
    USE SIGNAL ;
    PORT
      LAYER M4 ;
        RECT  17.196 17.424 17.28 17.448 ;
    END
  END q[238]
  PIN q[239]
    DIRECTION OUTPUT ;
    USE SIGNAL ;
    PORT
      LAYER M4 ;
        RECT  17.196 17.52 17.28 17.544 ;
    END
  END q[239]
  PIN q[23]
    DIRECTION OUTPUT ;
    USE SIGNAL ;
    PORT
      LAYER M4 ;
        RECT  17.196 92.016 17.28 92.04 ;
    END
  END q[23]
  PIN q[240]
    DIRECTION OUTPUT ;
    USE SIGNAL ;
    PORT
      LAYER M4 ;
        RECT  17.196 17.616 17.28 17.64 ;
    END
  END q[240]
  PIN q[241]
    DIRECTION OUTPUT ;
    USE SIGNAL ;
    PORT
      LAYER M4 ;
        RECT  17.196 17.712 17.28 17.736 ;
    END
  END q[241]
  PIN q[242]
    DIRECTION OUTPUT ;
    USE SIGNAL ;
    PORT
      LAYER M4 ;
        RECT  17.196 17.808 17.28 17.832 ;
    END
  END q[242]
  PIN q[243]
    DIRECTION OUTPUT ;
    USE SIGNAL ;
    PORT
      LAYER M4 ;
        RECT  17.196 17.904 17.28 17.928 ;
    END
  END q[243]
  PIN q[244]
    DIRECTION OUTPUT ;
    USE SIGNAL ;
    PORT
      LAYER M4 ;
        RECT  17.196 18 17.28 18.024 ;
    END
  END q[244]
  PIN q[245]
    DIRECTION OUTPUT ;
    USE SIGNAL ;
    PORT
      LAYER M4 ;
        RECT  17.196 18.096 17.28 18.12 ;
    END
  END q[245]
  PIN q[246]
    DIRECTION OUTPUT ;
    USE SIGNAL ;
    PORT
      LAYER M4 ;
        RECT  17.196 18.192 17.28 18.216 ;
    END
  END q[246]
  PIN q[247]
    DIRECTION OUTPUT ;
    USE SIGNAL ;
    PORT
      LAYER M4 ;
        RECT  17.196 18.288 17.28 18.312 ;
    END
  END q[247]
  PIN q[248]
    DIRECTION OUTPUT ;
    USE SIGNAL ;
    PORT
      LAYER M4 ;
        RECT  17.196 18.384 17.28 18.408 ;
    END
  END q[248]
  PIN q[249]
    DIRECTION OUTPUT ;
    USE SIGNAL ;
    PORT
      LAYER M4 ;
        RECT  17.196 18.48 17.28 18.504 ;
    END
  END q[249]
  PIN q[24]
    DIRECTION OUTPUT ;
    USE SIGNAL ;
    PORT
      LAYER M4 ;
        RECT  17.196 92.112 17.28 92.136 ;
    END
  END q[24]
  PIN q[250]
    DIRECTION OUTPUT ;
    USE SIGNAL ;
    PORT
      LAYER M4 ;
        RECT  17.196 18.576 17.28 18.6 ;
    END
  END q[250]
  PIN q[251]
    DIRECTION OUTPUT ;
    USE SIGNAL ;
    PORT
      LAYER M4 ;
        RECT  17.196 18.672 17.28 18.696 ;
    END
  END q[251]
  PIN q[252]
    DIRECTION OUTPUT ;
    USE SIGNAL ;
    PORT
      LAYER M4 ;
        RECT  17.196 18.768 17.28 18.792 ;
    END
  END q[252]
  PIN q[253]
    DIRECTION OUTPUT ;
    USE SIGNAL ;
    PORT
      LAYER M4 ;
        RECT  17.196 18.864 17.28 18.888 ;
    END
  END q[253]
  PIN q[254]
    DIRECTION OUTPUT ;
    USE SIGNAL ;
    PORT
      LAYER M4 ;
        RECT  17.196 18.96 17.28 18.984 ;
    END
  END q[254]
  PIN q[255]
    DIRECTION OUTPUT ;
    USE SIGNAL ;
    PORT
      LAYER M4 ;
        RECT  17.196 19.056 17.28 19.08 ;
    END
  END q[255]
  PIN q[256]
    DIRECTION OUTPUT ;
    USE SIGNAL ;
    PORT
      LAYER M4 ;
        RECT  17.196 35.28 17.28 35.304 ;
    END
  END q[256]
  PIN q[257]
    DIRECTION OUTPUT ;
    USE SIGNAL ;
    PORT
      LAYER M4 ;
        RECT  17.196 35.376 17.28 35.4 ;
    END
  END q[257]
  PIN q[258]
    DIRECTION OUTPUT ;
    USE SIGNAL ;
    PORT
      LAYER M4 ;
        RECT  17.196 35.472 17.28 35.496 ;
    END
  END q[258]
  PIN q[259]
    DIRECTION OUTPUT ;
    USE SIGNAL ;
    PORT
      LAYER M4 ;
        RECT  17.196 35.568 17.28 35.592 ;
    END
  END q[259]
  PIN q[25]
    DIRECTION OUTPUT ;
    USE SIGNAL ;
    PORT
      LAYER M4 ;
        RECT  17.196 92.208 17.28 92.232 ;
    END
  END q[25]
  PIN q[260]
    DIRECTION OUTPUT ;
    USE SIGNAL ;
    PORT
      LAYER M4 ;
        RECT  17.196 35.664 17.28 35.688 ;
    END
  END q[260]
  PIN q[261]
    DIRECTION OUTPUT ;
    USE SIGNAL ;
    PORT
      LAYER M4 ;
        RECT  17.196 35.76 17.28 35.784 ;
    END
  END q[261]
  PIN q[262]
    DIRECTION OUTPUT ;
    USE SIGNAL ;
    PORT
      LAYER M4 ;
        RECT  17.196 35.856 17.28 35.88 ;
    END
  END q[262]
  PIN q[263]
    DIRECTION OUTPUT ;
    USE SIGNAL ;
    PORT
      LAYER M4 ;
        RECT  17.196 35.952 17.28 35.976 ;
    END
  END q[263]
  PIN q[264]
    DIRECTION OUTPUT ;
    USE SIGNAL ;
    PORT
      LAYER M4 ;
        RECT  17.196 36.048 17.28 36.072 ;
    END
  END q[264]
  PIN q[265]
    DIRECTION OUTPUT ;
    USE SIGNAL ;
    PORT
      LAYER M4 ;
        RECT  17.196 36.144 17.28 36.168 ;
    END
  END q[265]
  PIN q[266]
    DIRECTION OUTPUT ;
    USE SIGNAL ;
    PORT
      LAYER M4 ;
        RECT  17.196 36.24 17.28 36.264 ;
    END
  END q[266]
  PIN q[267]
    DIRECTION OUTPUT ;
    USE SIGNAL ;
    PORT
      LAYER M4 ;
        RECT  17.196 36.336 17.28 36.36 ;
    END
  END q[267]
  PIN q[268]
    DIRECTION OUTPUT ;
    USE SIGNAL ;
    PORT
      LAYER M4 ;
        RECT  17.196 36.432 17.28 36.456 ;
    END
  END q[268]
  PIN q[269]
    DIRECTION OUTPUT ;
    USE SIGNAL ;
    PORT
      LAYER M4 ;
        RECT  17.196 36.528 17.28 36.552 ;
    END
  END q[269]
  PIN q[26]
    DIRECTION OUTPUT ;
    USE SIGNAL ;
    PORT
      LAYER M4 ;
        RECT  17.196 92.304 17.28 92.328 ;
    END
  END q[26]
  PIN q[270]
    DIRECTION OUTPUT ;
    USE SIGNAL ;
    PORT
      LAYER M4 ;
        RECT  17.196 36.624 17.28 36.648 ;
    END
  END q[270]
  PIN q[271]
    DIRECTION OUTPUT ;
    USE SIGNAL ;
    PORT
      LAYER M4 ;
        RECT  17.196 36.72 17.28 36.744 ;
    END
  END q[271]
  PIN q[272]
    DIRECTION OUTPUT ;
    USE SIGNAL ;
    PORT
      LAYER M4 ;
        RECT  17.196 36.816 17.28 36.84 ;
    END
  END q[272]
  PIN q[273]
    DIRECTION OUTPUT ;
    USE SIGNAL ;
    PORT
      LAYER M4 ;
        RECT  17.196 36.912 17.28 36.936 ;
    END
  END q[273]
  PIN q[274]
    DIRECTION OUTPUT ;
    USE SIGNAL ;
    PORT
      LAYER M4 ;
        RECT  17.196 37.008 17.28 37.032 ;
    END
  END q[274]
  PIN q[275]
    DIRECTION OUTPUT ;
    USE SIGNAL ;
    PORT
      LAYER M4 ;
        RECT  17.196 37.104 17.28 37.128 ;
    END
  END q[275]
  PIN q[276]
    DIRECTION OUTPUT ;
    USE SIGNAL ;
    PORT
      LAYER M4 ;
        RECT  17.196 37.2 17.28 37.224 ;
    END
  END q[276]
  PIN q[277]
    DIRECTION OUTPUT ;
    USE SIGNAL ;
    PORT
      LAYER M4 ;
        RECT  17.196 37.296 17.28 37.32 ;
    END
  END q[277]
  PIN q[278]
    DIRECTION OUTPUT ;
    USE SIGNAL ;
    PORT
      LAYER M4 ;
        RECT  17.196 37.392 17.28 37.416 ;
    END
  END q[278]
  PIN q[279]
    DIRECTION OUTPUT ;
    USE SIGNAL ;
    PORT
      LAYER M4 ;
        RECT  17.196 37.488 17.28 37.512 ;
    END
  END q[279]
  PIN q[27]
    DIRECTION OUTPUT ;
    USE SIGNAL ;
    PORT
      LAYER M4 ;
        RECT  17.196 92.4 17.28 92.424 ;
    END
  END q[27]
  PIN q[280]
    DIRECTION OUTPUT ;
    USE SIGNAL ;
    PORT
      LAYER M4 ;
        RECT  17.196 37.584 17.28 37.608 ;
    END
  END q[280]
  PIN q[281]
    DIRECTION OUTPUT ;
    USE SIGNAL ;
    PORT
      LAYER M4 ;
        RECT  17.196 37.68 17.28 37.704 ;
    END
  END q[281]
  PIN q[282]
    DIRECTION OUTPUT ;
    USE SIGNAL ;
    PORT
      LAYER M4 ;
        RECT  17.196 37.776 17.28 37.8 ;
    END
  END q[282]
  PIN q[283]
    DIRECTION OUTPUT ;
    USE SIGNAL ;
    PORT
      LAYER M4 ;
        RECT  17.196 37.872 17.28 37.896 ;
    END
  END q[283]
  PIN q[284]
    DIRECTION OUTPUT ;
    USE SIGNAL ;
    PORT
      LAYER M4 ;
        RECT  17.196 37.968 17.28 37.992 ;
    END
  END q[284]
  PIN q[285]
    DIRECTION OUTPUT ;
    USE SIGNAL ;
    PORT
      LAYER M4 ;
        RECT  17.196 38.064 17.28 38.088 ;
    END
  END q[285]
  PIN q[286]
    DIRECTION OUTPUT ;
    USE SIGNAL ;
    PORT
      LAYER M4 ;
        RECT  17.196 38.16 17.28 38.184 ;
    END
  END q[286]
  PIN q[287]
    DIRECTION OUTPUT ;
    USE SIGNAL ;
    PORT
      LAYER M4 ;
        RECT  17.196 38.256 17.28 38.28 ;
    END
  END q[287]
  PIN q[288]
    DIRECTION OUTPUT ;
    USE SIGNAL ;
    PORT
      LAYER M4 ;
        RECT  17.196 32.208 17.28 32.232 ;
    END
  END q[288]
  PIN q[289]
    DIRECTION OUTPUT ;
    USE SIGNAL ;
    PORT
      LAYER M4 ;
        RECT  17.196 32.304 17.28 32.328 ;
    END
  END q[289]
  PIN q[28]
    DIRECTION OUTPUT ;
    USE SIGNAL ;
    PORT
      LAYER M4 ;
        RECT  17.196 92.496 17.28 92.52 ;
    END
  END q[28]
  PIN q[290]
    DIRECTION OUTPUT ;
    USE SIGNAL ;
    PORT
      LAYER M4 ;
        RECT  17.196 32.4 17.28 32.424 ;
    END
  END q[290]
  PIN q[291]
    DIRECTION OUTPUT ;
    USE SIGNAL ;
    PORT
      LAYER M4 ;
        RECT  17.196 32.496 17.28 32.52 ;
    END
  END q[291]
  PIN q[292]
    DIRECTION OUTPUT ;
    USE SIGNAL ;
    PORT
      LAYER M4 ;
        RECT  17.196 32.592 17.28 32.616 ;
    END
  END q[292]
  PIN q[293]
    DIRECTION OUTPUT ;
    USE SIGNAL ;
    PORT
      LAYER M4 ;
        RECT  17.196 32.688 17.28 32.712 ;
    END
  END q[293]
  PIN q[294]
    DIRECTION OUTPUT ;
    USE SIGNAL ;
    PORT
      LAYER M4 ;
        RECT  17.196 32.784 17.28 32.808 ;
    END
  END q[294]
  PIN q[295]
    DIRECTION OUTPUT ;
    USE SIGNAL ;
    PORT
      LAYER M4 ;
        RECT  17.196 32.88 17.28 32.904 ;
    END
  END q[295]
  PIN q[296]
    DIRECTION OUTPUT ;
    USE SIGNAL ;
    PORT
      LAYER M4 ;
        RECT  17.196 32.976 17.28 33 ;
    END
  END q[296]
  PIN q[297]
    DIRECTION OUTPUT ;
    USE SIGNAL ;
    PORT
      LAYER M4 ;
        RECT  17.196 33.072 17.28 33.096 ;
    END
  END q[297]
  PIN q[298]
    DIRECTION OUTPUT ;
    USE SIGNAL ;
    PORT
      LAYER M4 ;
        RECT  17.196 33.168 17.28 33.192 ;
    END
  END q[298]
  PIN q[299]
    DIRECTION OUTPUT ;
    USE SIGNAL ;
    PORT
      LAYER M4 ;
        RECT  17.196 33.264 17.28 33.288 ;
    END
  END q[299]
  PIN q[29]
    DIRECTION OUTPUT ;
    USE SIGNAL ;
    PORT
      LAYER M4 ;
        RECT  17.196 92.592 17.28 92.616 ;
    END
  END q[29]
  PIN q[2]
    DIRECTION OUTPUT ;
    USE SIGNAL ;
    PORT
      LAYER M4 ;
        RECT  17.196 90 17.28 90.024 ;
    END
  END q[2]
  PIN q[300]
    DIRECTION OUTPUT ;
    USE SIGNAL ;
    PORT
      LAYER M4 ;
        RECT  17.196 33.36 17.28 33.384 ;
    END
  END q[300]
  PIN q[301]
    DIRECTION OUTPUT ;
    USE SIGNAL ;
    PORT
      LAYER M4 ;
        RECT  17.196 33.456 17.28 33.48 ;
    END
  END q[301]
  PIN q[302]
    DIRECTION OUTPUT ;
    USE SIGNAL ;
    PORT
      LAYER M4 ;
        RECT  17.196 33.552 17.28 33.576 ;
    END
  END q[302]
  PIN q[303]
    DIRECTION OUTPUT ;
    USE SIGNAL ;
    PORT
      LAYER M4 ;
        RECT  17.196 33.648 17.28 33.672 ;
    END
  END q[303]
  PIN q[304]
    DIRECTION OUTPUT ;
    USE SIGNAL ;
    PORT
      LAYER M4 ;
        RECT  17.196 33.744 17.28 33.768 ;
    END
  END q[304]
  PIN q[305]
    DIRECTION OUTPUT ;
    USE SIGNAL ;
    PORT
      LAYER M4 ;
        RECT  17.196 33.84 17.28 33.864 ;
    END
  END q[305]
  PIN q[306]
    DIRECTION OUTPUT ;
    USE SIGNAL ;
    PORT
      LAYER M4 ;
        RECT  17.196 33.936 17.28 33.96 ;
    END
  END q[306]
  PIN q[307]
    DIRECTION OUTPUT ;
    USE SIGNAL ;
    PORT
      LAYER M4 ;
        RECT  17.196 34.032 17.28 34.056 ;
    END
  END q[307]
  PIN q[308]
    DIRECTION OUTPUT ;
    USE SIGNAL ;
    PORT
      LAYER M4 ;
        RECT  17.196 34.128 17.28 34.152 ;
    END
  END q[308]
  PIN q[309]
    DIRECTION OUTPUT ;
    USE SIGNAL ;
    PORT
      LAYER M4 ;
        RECT  17.196 34.224 17.28 34.248 ;
    END
  END q[309]
  PIN q[30]
    DIRECTION OUTPUT ;
    USE SIGNAL ;
    PORT
      LAYER M4 ;
        RECT  17.196 92.688 17.28 92.712 ;
    END
  END q[30]
  PIN q[310]
    DIRECTION OUTPUT ;
    USE SIGNAL ;
    PORT
      LAYER M4 ;
        RECT  17.196 34.32 17.28 34.344 ;
    END
  END q[310]
  PIN q[311]
    DIRECTION OUTPUT ;
    USE SIGNAL ;
    PORT
      LAYER M4 ;
        RECT  17.196 34.416 17.28 34.44 ;
    END
  END q[311]
  PIN q[312]
    DIRECTION OUTPUT ;
    USE SIGNAL ;
    PORT
      LAYER M4 ;
        RECT  17.196 34.512 17.28 34.536 ;
    END
  END q[312]
  PIN q[313]
    DIRECTION OUTPUT ;
    USE SIGNAL ;
    PORT
      LAYER M4 ;
        RECT  17.196 34.608 17.28 34.632 ;
    END
  END q[313]
  PIN q[314]
    DIRECTION OUTPUT ;
    USE SIGNAL ;
    PORT
      LAYER M4 ;
        RECT  17.196 34.704 17.28 34.728 ;
    END
  END q[314]
  PIN q[315]
    DIRECTION OUTPUT ;
    USE SIGNAL ;
    PORT
      LAYER M4 ;
        RECT  17.196 34.8 17.28 34.824 ;
    END
  END q[315]
  PIN q[316]
    DIRECTION OUTPUT ;
    USE SIGNAL ;
    PORT
      LAYER M4 ;
        RECT  17.196 34.896 17.28 34.92 ;
    END
  END q[316]
  PIN q[317]
    DIRECTION OUTPUT ;
    USE SIGNAL ;
    PORT
      LAYER M4 ;
        RECT  17.196 34.992 17.28 35.016 ;
    END
  END q[317]
  PIN q[318]
    DIRECTION OUTPUT ;
    USE SIGNAL ;
    PORT
      LAYER M4 ;
        RECT  17.196 35.088 17.28 35.112 ;
    END
  END q[318]
  PIN q[319]
    DIRECTION OUTPUT ;
    USE SIGNAL ;
    PORT
      LAYER M4 ;
        RECT  17.196 35.184 17.28 35.208 ;
    END
  END q[319]
  PIN q[31]
    DIRECTION OUTPUT ;
    USE SIGNAL ;
    PORT
      LAYER M4 ;
        RECT  17.196 92.784 17.28 92.808 ;
    END
  END q[31]
  PIN q[320]
    DIRECTION OUTPUT ;
    USE SIGNAL ;
    PORT
      LAYER M4 ;
        RECT  17.196 42.192 17.28 42.216 ;
    END
  END q[320]
  PIN q[321]
    DIRECTION OUTPUT ;
    USE SIGNAL ;
    PORT
      LAYER M4 ;
        RECT  17.196 42.288 17.28 42.312 ;
    END
  END q[321]
  PIN q[322]
    DIRECTION OUTPUT ;
    USE SIGNAL ;
    PORT
      LAYER M4 ;
        RECT  17.196 42.384 17.28 42.408 ;
    END
  END q[322]
  PIN q[323]
    DIRECTION OUTPUT ;
    USE SIGNAL ;
    PORT
      LAYER M4 ;
        RECT  17.196 42.48 17.28 42.504 ;
    END
  END q[323]
  PIN q[324]
    DIRECTION OUTPUT ;
    USE SIGNAL ;
    PORT
      LAYER M4 ;
        RECT  17.196 42.576 17.28 42.6 ;
    END
  END q[324]
  PIN q[325]
    DIRECTION OUTPUT ;
    USE SIGNAL ;
    PORT
      LAYER M4 ;
        RECT  17.196 42.672 17.28 42.696 ;
    END
  END q[325]
  PIN q[326]
    DIRECTION OUTPUT ;
    USE SIGNAL ;
    PORT
      LAYER M4 ;
        RECT  17.196 42.768 17.28 42.792 ;
    END
  END q[326]
  PIN q[327]
    DIRECTION OUTPUT ;
    USE SIGNAL ;
    PORT
      LAYER M4 ;
        RECT  17.196 42.864 17.28 42.888 ;
    END
  END q[327]
  PIN q[328]
    DIRECTION OUTPUT ;
    USE SIGNAL ;
    PORT
      LAYER M4 ;
        RECT  17.196 42.96 17.28 42.984 ;
    END
  END q[328]
  PIN q[329]
    DIRECTION OUTPUT ;
    USE SIGNAL ;
    PORT
      LAYER M4 ;
        RECT  17.196 43.056 17.28 43.08 ;
    END
  END q[329]
  PIN q[32]
    DIRECTION OUTPUT ;
    USE SIGNAL ;
    PORT
      LAYER M4 ;
        RECT  17.196 86.736 17.28 86.76 ;
    END
  END q[32]
  PIN q[330]
    DIRECTION OUTPUT ;
    USE SIGNAL ;
    PORT
      LAYER M4 ;
        RECT  17.196 43.152 17.28 43.176 ;
    END
  END q[330]
  PIN q[331]
    DIRECTION OUTPUT ;
    USE SIGNAL ;
    PORT
      LAYER M4 ;
        RECT  17.196 43.248 17.28 43.272 ;
    END
  END q[331]
  PIN q[332]
    DIRECTION OUTPUT ;
    USE SIGNAL ;
    PORT
      LAYER M4 ;
        RECT  17.196 43.344 17.28 43.368 ;
    END
  END q[332]
  PIN q[333]
    DIRECTION OUTPUT ;
    USE SIGNAL ;
    PORT
      LAYER M4 ;
        RECT  17.196 43.44 17.28 43.464 ;
    END
  END q[333]
  PIN q[334]
    DIRECTION OUTPUT ;
    USE SIGNAL ;
    PORT
      LAYER M4 ;
        RECT  17.196 43.536 17.28 43.56 ;
    END
  END q[334]
  PIN q[335]
    DIRECTION OUTPUT ;
    USE SIGNAL ;
    PORT
      LAYER M4 ;
        RECT  17.196 43.632 17.28 43.656 ;
    END
  END q[335]
  PIN q[336]
    DIRECTION OUTPUT ;
    USE SIGNAL ;
    PORT
      LAYER M4 ;
        RECT  17.196 43.728 17.28 43.752 ;
    END
  END q[336]
  PIN q[337]
    DIRECTION OUTPUT ;
    USE SIGNAL ;
    PORT
      LAYER M4 ;
        RECT  17.196 43.824 17.28 43.848 ;
    END
  END q[337]
  PIN q[338]
    DIRECTION OUTPUT ;
    USE SIGNAL ;
    PORT
      LAYER M4 ;
        RECT  17.196 43.92 17.28 43.944 ;
    END
  END q[338]
  PIN q[339]
    DIRECTION OUTPUT ;
    USE SIGNAL ;
    PORT
      LAYER M4 ;
        RECT  17.196 44.016 17.28 44.04 ;
    END
  END q[339]
  PIN q[33]
    DIRECTION OUTPUT ;
    USE SIGNAL ;
    PORT
      LAYER M4 ;
        RECT  17.196 86.832 17.28 86.856 ;
    END
  END q[33]
  PIN q[340]
    DIRECTION OUTPUT ;
    USE SIGNAL ;
    PORT
      LAYER M4 ;
        RECT  17.196 44.112 17.28 44.136 ;
    END
  END q[340]
  PIN q[341]
    DIRECTION OUTPUT ;
    USE SIGNAL ;
    PORT
      LAYER M4 ;
        RECT  17.196 44.208 17.28 44.232 ;
    END
  END q[341]
  PIN q[342]
    DIRECTION OUTPUT ;
    USE SIGNAL ;
    PORT
      LAYER M4 ;
        RECT  17.196 44.304 17.28 44.328 ;
    END
  END q[342]
  PIN q[343]
    DIRECTION OUTPUT ;
    USE SIGNAL ;
    PORT
      LAYER M4 ;
        RECT  17.196 44.4 17.28 44.424 ;
    END
  END q[343]
  PIN q[344]
    DIRECTION OUTPUT ;
    USE SIGNAL ;
    PORT
      LAYER M4 ;
        RECT  17.196 44.496 17.28 44.52 ;
    END
  END q[344]
  PIN q[345]
    DIRECTION OUTPUT ;
    USE SIGNAL ;
    PORT
      LAYER M4 ;
        RECT  17.196 44.592 17.28 44.616 ;
    END
  END q[345]
  PIN q[346]
    DIRECTION OUTPUT ;
    USE SIGNAL ;
    PORT
      LAYER M4 ;
        RECT  17.196 44.688 17.28 44.712 ;
    END
  END q[346]
  PIN q[347]
    DIRECTION OUTPUT ;
    USE SIGNAL ;
    PORT
      LAYER M4 ;
        RECT  17.196 44.784 17.28 44.808 ;
    END
  END q[347]
  PIN q[348]
    DIRECTION OUTPUT ;
    USE SIGNAL ;
    PORT
      LAYER M4 ;
        RECT  17.196 44.88 17.28 44.904 ;
    END
  END q[348]
  PIN q[349]
    DIRECTION OUTPUT ;
    USE SIGNAL ;
    PORT
      LAYER M4 ;
        RECT  17.196 44.976 17.28 45 ;
    END
  END q[349]
  PIN q[34]
    DIRECTION OUTPUT ;
    USE SIGNAL ;
    PORT
      LAYER M4 ;
        RECT  17.196 86.928 17.28 86.952 ;
    END
  END q[34]
  PIN q[350]
    DIRECTION OUTPUT ;
    USE SIGNAL ;
    PORT
      LAYER M4 ;
        RECT  17.196 45.072 17.28 45.096 ;
    END
  END q[350]
  PIN q[351]
    DIRECTION OUTPUT ;
    USE SIGNAL ;
    PORT
      LAYER M4 ;
        RECT  17.196 45.168 17.28 45.192 ;
    END
  END q[351]
  PIN q[352]
    DIRECTION OUTPUT ;
    USE SIGNAL ;
    PORT
      LAYER M4 ;
        RECT  17.196 48.336 17.28 48.36 ;
    END
  END q[352]
  PIN q[353]
    DIRECTION OUTPUT ;
    USE SIGNAL ;
    PORT
      LAYER M4 ;
        RECT  17.196 48.432 17.28 48.456 ;
    END
  END q[353]
  PIN q[354]
    DIRECTION OUTPUT ;
    USE SIGNAL ;
    PORT
      LAYER M4 ;
        RECT  17.196 48.528 17.28 48.552 ;
    END
  END q[354]
  PIN q[355]
    DIRECTION OUTPUT ;
    USE SIGNAL ;
    PORT
      LAYER M4 ;
        RECT  17.196 48.624 17.28 48.648 ;
    END
  END q[355]
  PIN q[356]
    DIRECTION OUTPUT ;
    USE SIGNAL ;
    PORT
      LAYER M4 ;
        RECT  17.196 48.72 17.28 48.744 ;
    END
  END q[356]
  PIN q[357]
    DIRECTION OUTPUT ;
    USE SIGNAL ;
    PORT
      LAYER M4 ;
        RECT  17.196 48.816 17.28 48.84 ;
    END
  END q[357]
  PIN q[358]
    DIRECTION OUTPUT ;
    USE SIGNAL ;
    PORT
      LAYER M4 ;
        RECT  17.196 48.912 17.28 48.936 ;
    END
  END q[358]
  PIN q[359]
    DIRECTION OUTPUT ;
    USE SIGNAL ;
    PORT
      LAYER M4 ;
        RECT  17.196 49.008 17.28 49.032 ;
    END
  END q[359]
  PIN q[35]
    DIRECTION OUTPUT ;
    USE SIGNAL ;
    PORT
      LAYER M4 ;
        RECT  17.196 87.024 17.28 87.048 ;
    END
  END q[35]
  PIN q[360]
    DIRECTION OUTPUT ;
    USE SIGNAL ;
    PORT
      LAYER M4 ;
        RECT  17.196 49.104 17.28 49.128 ;
    END
  END q[360]
  PIN q[361]
    DIRECTION OUTPUT ;
    USE SIGNAL ;
    PORT
      LAYER M4 ;
        RECT  17.196 49.2 17.28 49.224 ;
    END
  END q[361]
  PIN q[362]
    DIRECTION OUTPUT ;
    USE SIGNAL ;
    PORT
      LAYER M4 ;
        RECT  17.196 49.296 17.28 49.32 ;
    END
  END q[362]
  PIN q[363]
    DIRECTION OUTPUT ;
    USE SIGNAL ;
    PORT
      LAYER M4 ;
        RECT  17.196 49.392 17.28 49.416 ;
    END
  END q[363]
  PIN q[364]
    DIRECTION OUTPUT ;
    USE SIGNAL ;
    PORT
      LAYER M4 ;
        RECT  17.196 49.488 17.28 49.512 ;
    END
  END q[364]
  PIN q[365]
    DIRECTION OUTPUT ;
    USE SIGNAL ;
    PORT
      LAYER M4 ;
        RECT  17.196 49.584 17.28 49.608 ;
    END
  END q[365]
  PIN q[366]
    DIRECTION OUTPUT ;
    USE SIGNAL ;
    PORT
      LAYER M4 ;
        RECT  17.196 49.68 17.28 49.704 ;
    END
  END q[366]
  PIN q[367]
    DIRECTION OUTPUT ;
    USE SIGNAL ;
    PORT
      LAYER M4 ;
        RECT  17.196 49.776 17.28 49.8 ;
    END
  END q[367]
  PIN q[368]
    DIRECTION OUTPUT ;
    USE SIGNAL ;
    PORT
      LAYER M4 ;
        RECT  17.196 49.872 17.28 49.896 ;
    END
  END q[368]
  PIN q[369]
    DIRECTION OUTPUT ;
    USE SIGNAL ;
    PORT
      LAYER M4 ;
        RECT  17.196 49.968 17.28 49.992 ;
    END
  END q[369]
  PIN q[36]
    DIRECTION OUTPUT ;
    USE SIGNAL ;
    PORT
      LAYER M4 ;
        RECT  17.196 87.12 17.28 87.144 ;
    END
  END q[36]
  PIN q[370]
    DIRECTION OUTPUT ;
    USE SIGNAL ;
    PORT
      LAYER M4 ;
        RECT  17.196 50.064 17.28 50.088 ;
    END
  END q[370]
  PIN q[371]
    DIRECTION OUTPUT ;
    USE SIGNAL ;
    PORT
      LAYER M4 ;
        RECT  17.196 50.16 17.28 50.184 ;
    END
  END q[371]
  PIN q[372]
    DIRECTION OUTPUT ;
    USE SIGNAL ;
    PORT
      LAYER M4 ;
        RECT  17.196 50.256 17.28 50.28 ;
    END
  END q[372]
  PIN q[373]
    DIRECTION OUTPUT ;
    USE SIGNAL ;
    PORT
      LAYER M4 ;
        RECT  17.196 50.352 17.28 50.376 ;
    END
  END q[373]
  PIN q[374]
    DIRECTION OUTPUT ;
    USE SIGNAL ;
    PORT
      LAYER M4 ;
        RECT  17.196 50.448 17.28 50.472 ;
    END
  END q[374]
  PIN q[375]
    DIRECTION OUTPUT ;
    USE SIGNAL ;
    PORT
      LAYER M4 ;
        RECT  17.196 50.544 17.28 50.568 ;
    END
  END q[375]
  PIN q[376]
    DIRECTION OUTPUT ;
    USE SIGNAL ;
    PORT
      LAYER M4 ;
        RECT  17.196 50.64 17.28 50.664 ;
    END
  END q[376]
  PIN q[377]
    DIRECTION OUTPUT ;
    USE SIGNAL ;
    PORT
      LAYER M4 ;
        RECT  17.196 50.736 17.28 50.76 ;
    END
  END q[377]
  PIN q[378]
    DIRECTION OUTPUT ;
    USE SIGNAL ;
    PORT
      LAYER M4 ;
        RECT  17.196 50.832 17.28 50.856 ;
    END
  END q[378]
  PIN q[379]
    DIRECTION OUTPUT ;
    USE SIGNAL ;
    PORT
      LAYER M4 ;
        RECT  17.196 50.928 17.28 50.952 ;
    END
  END q[379]
  PIN q[37]
    DIRECTION OUTPUT ;
    USE SIGNAL ;
    PORT
      LAYER M4 ;
        RECT  17.196 87.216 17.28 87.24 ;
    END
  END q[37]
  PIN q[380]
    DIRECTION OUTPUT ;
    USE SIGNAL ;
    PORT
      LAYER M4 ;
        RECT  17.196 51.024 17.28 51.048 ;
    END
  END q[380]
  PIN q[381]
    DIRECTION OUTPUT ;
    USE SIGNAL ;
    PORT
      LAYER M4 ;
        RECT  17.196 51.12 17.28 51.144 ;
    END
  END q[381]
  PIN q[382]
    DIRECTION OUTPUT ;
    USE SIGNAL ;
    PORT
      LAYER M4 ;
        RECT  17.196 51.216 17.28 51.24 ;
    END
  END q[382]
  PIN q[383]
    DIRECTION OUTPUT ;
    USE SIGNAL ;
    PORT
      LAYER M4 ;
        RECT  17.196 51.312 17.28 51.336 ;
    END
  END q[383]
  PIN q[384]
    DIRECTION OUTPUT ;
    USE SIGNAL ;
    PORT
      LAYER M4 ;
        RECT  17.196 54.48 17.28 54.504 ;
    END
  END q[384]
  PIN q[385]
    DIRECTION OUTPUT ;
    USE SIGNAL ;
    PORT
      LAYER M4 ;
        RECT  17.196 54.576 17.28 54.6 ;
    END
  END q[385]
  PIN q[386]
    DIRECTION OUTPUT ;
    USE SIGNAL ;
    PORT
      LAYER M4 ;
        RECT  17.196 54.672 17.28 54.696 ;
    END
  END q[386]
  PIN q[387]
    DIRECTION OUTPUT ;
    USE SIGNAL ;
    PORT
      LAYER M4 ;
        RECT  17.196 54.768 17.28 54.792 ;
    END
  END q[387]
  PIN q[388]
    DIRECTION OUTPUT ;
    USE SIGNAL ;
    PORT
      LAYER M4 ;
        RECT  17.196 54.864 17.28 54.888 ;
    END
  END q[388]
  PIN q[389]
    DIRECTION OUTPUT ;
    USE SIGNAL ;
    PORT
      LAYER M4 ;
        RECT  17.196 54.96 17.28 54.984 ;
    END
  END q[389]
  PIN q[38]
    DIRECTION OUTPUT ;
    USE SIGNAL ;
    PORT
      LAYER M4 ;
        RECT  17.196 87.312 17.28 87.336 ;
    END
  END q[38]
  PIN q[390]
    DIRECTION OUTPUT ;
    USE SIGNAL ;
    PORT
      LAYER M4 ;
        RECT  17.196 55.056 17.28 55.08 ;
    END
  END q[390]
  PIN q[391]
    DIRECTION OUTPUT ;
    USE SIGNAL ;
    PORT
      LAYER M4 ;
        RECT  17.196 55.152 17.28 55.176 ;
    END
  END q[391]
  PIN q[392]
    DIRECTION OUTPUT ;
    USE SIGNAL ;
    PORT
      LAYER M4 ;
        RECT  17.196 55.248 17.28 55.272 ;
    END
  END q[392]
  PIN q[393]
    DIRECTION OUTPUT ;
    USE SIGNAL ;
    PORT
      LAYER M4 ;
        RECT  17.196 55.344 17.28 55.368 ;
    END
  END q[393]
  PIN q[394]
    DIRECTION OUTPUT ;
    USE SIGNAL ;
    PORT
      LAYER M4 ;
        RECT  17.196 55.44 17.28 55.464 ;
    END
  END q[394]
  PIN q[395]
    DIRECTION OUTPUT ;
    USE SIGNAL ;
    PORT
      LAYER M4 ;
        RECT  17.196 55.536 17.28 55.56 ;
    END
  END q[395]
  PIN q[396]
    DIRECTION OUTPUT ;
    USE SIGNAL ;
    PORT
      LAYER M4 ;
        RECT  17.196 55.632 17.28 55.656 ;
    END
  END q[396]
  PIN q[397]
    DIRECTION OUTPUT ;
    USE SIGNAL ;
    PORT
      LAYER M4 ;
        RECT  17.196 55.728 17.28 55.752 ;
    END
  END q[397]
  PIN q[398]
    DIRECTION OUTPUT ;
    USE SIGNAL ;
    PORT
      LAYER M4 ;
        RECT  17.196 55.824 17.28 55.848 ;
    END
  END q[398]
  PIN q[399]
    DIRECTION OUTPUT ;
    USE SIGNAL ;
    PORT
      LAYER M4 ;
        RECT  17.196 55.92 17.28 55.944 ;
    END
  END q[399]
  PIN q[39]
    DIRECTION OUTPUT ;
    USE SIGNAL ;
    PORT
      LAYER M4 ;
        RECT  17.196 87.408 17.28 87.432 ;
    END
  END q[39]
  PIN q[3]
    DIRECTION OUTPUT ;
    USE SIGNAL ;
    PORT
      LAYER M4 ;
        RECT  17.196 90.096 17.28 90.12 ;
    END
  END q[3]
  PIN q[400]
    DIRECTION OUTPUT ;
    USE SIGNAL ;
    PORT
      LAYER M4 ;
        RECT  17.196 56.016 17.28 56.04 ;
    END
  END q[400]
  PIN q[401]
    DIRECTION OUTPUT ;
    USE SIGNAL ;
    PORT
      LAYER M4 ;
        RECT  17.196 56.112 17.28 56.136 ;
    END
  END q[401]
  PIN q[402]
    DIRECTION OUTPUT ;
    USE SIGNAL ;
    PORT
      LAYER M4 ;
        RECT  17.196 56.208 17.28 56.232 ;
    END
  END q[402]
  PIN q[403]
    DIRECTION OUTPUT ;
    USE SIGNAL ;
    PORT
      LAYER M4 ;
        RECT  17.196 56.304 17.28 56.328 ;
    END
  END q[403]
  PIN q[404]
    DIRECTION OUTPUT ;
    USE SIGNAL ;
    PORT
      LAYER M4 ;
        RECT  17.196 56.4 17.28 56.424 ;
    END
  END q[404]
  PIN q[405]
    DIRECTION OUTPUT ;
    USE SIGNAL ;
    PORT
      LAYER M4 ;
        RECT  17.196 56.496 17.28 56.52 ;
    END
  END q[405]
  PIN q[406]
    DIRECTION OUTPUT ;
    USE SIGNAL ;
    PORT
      LAYER M4 ;
        RECT  17.196 56.592 17.28 56.616 ;
    END
  END q[406]
  PIN q[407]
    DIRECTION OUTPUT ;
    USE SIGNAL ;
    PORT
      LAYER M4 ;
        RECT  17.196 56.688 17.28 56.712 ;
    END
  END q[407]
  PIN q[408]
    DIRECTION OUTPUT ;
    USE SIGNAL ;
    PORT
      LAYER M4 ;
        RECT  17.196 56.784 17.28 56.808 ;
    END
  END q[408]
  PIN q[409]
    DIRECTION OUTPUT ;
    USE SIGNAL ;
    PORT
      LAYER M4 ;
        RECT  17.196 56.88 17.28 56.904 ;
    END
  END q[409]
  PIN q[40]
    DIRECTION OUTPUT ;
    USE SIGNAL ;
    PORT
      LAYER M4 ;
        RECT  17.196 87.504 17.28 87.528 ;
    END
  END q[40]
  PIN q[410]
    DIRECTION OUTPUT ;
    USE SIGNAL ;
    PORT
      LAYER M4 ;
        RECT  17.196 56.976 17.28 57 ;
    END
  END q[410]
  PIN q[411]
    DIRECTION OUTPUT ;
    USE SIGNAL ;
    PORT
      LAYER M4 ;
        RECT  17.196 57.072 17.28 57.096 ;
    END
  END q[411]
  PIN q[412]
    DIRECTION OUTPUT ;
    USE SIGNAL ;
    PORT
      LAYER M4 ;
        RECT  17.196 57.168 17.28 57.192 ;
    END
  END q[412]
  PIN q[413]
    DIRECTION OUTPUT ;
    USE SIGNAL ;
    PORT
      LAYER M4 ;
        RECT  17.196 57.264 17.28 57.288 ;
    END
  END q[413]
  PIN q[414]
    DIRECTION OUTPUT ;
    USE SIGNAL ;
    PORT
      LAYER M4 ;
        RECT  17.196 57.36 17.28 57.384 ;
    END
  END q[414]
  PIN q[415]
    DIRECTION OUTPUT ;
    USE SIGNAL ;
    PORT
      LAYER M4 ;
        RECT  17.196 57.456 17.28 57.48 ;
    END
  END q[415]
  PIN q[416]
    DIRECTION OUTPUT ;
    USE SIGNAL ;
    PORT
      LAYER M4 ;
        RECT  17.196 61.392 17.28 61.416 ;
    END
  END q[416]
  PIN q[417]
    DIRECTION OUTPUT ;
    USE SIGNAL ;
    PORT
      LAYER M4 ;
        RECT  17.196 61.488 17.28 61.512 ;
    END
  END q[417]
  PIN q[418]
    DIRECTION OUTPUT ;
    USE SIGNAL ;
    PORT
      LAYER M4 ;
        RECT  17.196 61.584 17.28 61.608 ;
    END
  END q[418]
  PIN q[419]
    DIRECTION OUTPUT ;
    USE SIGNAL ;
    PORT
      LAYER M4 ;
        RECT  17.196 61.68 17.28 61.704 ;
    END
  END q[419]
  PIN q[41]
    DIRECTION OUTPUT ;
    USE SIGNAL ;
    PORT
      LAYER M4 ;
        RECT  17.196 87.6 17.28 87.624 ;
    END
  END q[41]
  PIN q[420]
    DIRECTION OUTPUT ;
    USE SIGNAL ;
    PORT
      LAYER M4 ;
        RECT  17.196 61.776 17.28 61.8 ;
    END
  END q[420]
  PIN q[421]
    DIRECTION OUTPUT ;
    USE SIGNAL ;
    PORT
      LAYER M4 ;
        RECT  17.196 61.872 17.28 61.896 ;
    END
  END q[421]
  PIN q[422]
    DIRECTION OUTPUT ;
    USE SIGNAL ;
    PORT
      LAYER M4 ;
        RECT  17.196 61.968 17.28 61.992 ;
    END
  END q[422]
  PIN q[423]
    DIRECTION OUTPUT ;
    USE SIGNAL ;
    PORT
      LAYER M4 ;
        RECT  17.196 62.064 17.28 62.088 ;
    END
  END q[423]
  PIN q[424]
    DIRECTION OUTPUT ;
    USE SIGNAL ;
    PORT
      LAYER M4 ;
        RECT  17.196 62.16 17.28 62.184 ;
    END
  END q[424]
  PIN q[425]
    DIRECTION OUTPUT ;
    USE SIGNAL ;
    PORT
      LAYER M4 ;
        RECT  17.196 62.256 17.28 62.28 ;
    END
  END q[425]
  PIN q[426]
    DIRECTION OUTPUT ;
    USE SIGNAL ;
    PORT
      LAYER M4 ;
        RECT  17.196 62.352 17.28 62.376 ;
    END
  END q[426]
  PIN q[427]
    DIRECTION OUTPUT ;
    USE SIGNAL ;
    PORT
      LAYER M4 ;
        RECT  17.196 62.448 17.28 62.472 ;
    END
  END q[427]
  PIN q[428]
    DIRECTION OUTPUT ;
    USE SIGNAL ;
    PORT
      LAYER M4 ;
        RECT  17.196 62.544 17.28 62.568 ;
    END
  END q[428]
  PIN q[429]
    DIRECTION OUTPUT ;
    USE SIGNAL ;
    PORT
      LAYER M4 ;
        RECT  17.196 62.64 17.28 62.664 ;
    END
  END q[429]
  PIN q[42]
    DIRECTION OUTPUT ;
    USE SIGNAL ;
    PORT
      LAYER M4 ;
        RECT  17.196 87.696 17.28 87.72 ;
    END
  END q[42]
  PIN q[430]
    DIRECTION OUTPUT ;
    USE SIGNAL ;
    PORT
      LAYER M4 ;
        RECT  17.196 62.736 17.28 62.76 ;
    END
  END q[430]
  PIN q[431]
    DIRECTION OUTPUT ;
    USE SIGNAL ;
    PORT
      LAYER M4 ;
        RECT  17.196 62.832 17.28 62.856 ;
    END
  END q[431]
  PIN q[432]
    DIRECTION OUTPUT ;
    USE SIGNAL ;
    PORT
      LAYER M4 ;
        RECT  17.196 62.928 17.28 62.952 ;
    END
  END q[432]
  PIN q[433]
    DIRECTION OUTPUT ;
    USE SIGNAL ;
    PORT
      LAYER M4 ;
        RECT  17.196 63.024 17.28 63.048 ;
    END
  END q[433]
  PIN q[434]
    DIRECTION OUTPUT ;
    USE SIGNAL ;
    PORT
      LAYER M4 ;
        RECT  17.196 63.12 17.28 63.144 ;
    END
  END q[434]
  PIN q[435]
    DIRECTION OUTPUT ;
    USE SIGNAL ;
    PORT
      LAYER M4 ;
        RECT  17.196 63.216 17.28 63.24 ;
    END
  END q[435]
  PIN q[436]
    DIRECTION OUTPUT ;
    USE SIGNAL ;
    PORT
      LAYER M4 ;
        RECT  17.196 63.312 17.28 63.336 ;
    END
  END q[436]
  PIN q[437]
    DIRECTION OUTPUT ;
    USE SIGNAL ;
    PORT
      LAYER M4 ;
        RECT  17.196 63.408 17.28 63.432 ;
    END
  END q[437]
  PIN q[438]
    DIRECTION OUTPUT ;
    USE SIGNAL ;
    PORT
      LAYER M4 ;
        RECT  17.196 63.504 17.28 63.528 ;
    END
  END q[438]
  PIN q[439]
    DIRECTION OUTPUT ;
    USE SIGNAL ;
    PORT
      LAYER M4 ;
        RECT  17.196 63.6 17.28 63.624 ;
    END
  END q[439]
  PIN q[43]
    DIRECTION OUTPUT ;
    USE SIGNAL ;
    PORT
      LAYER M4 ;
        RECT  17.196 87.792 17.28 87.816 ;
    END
  END q[43]
  PIN q[440]
    DIRECTION OUTPUT ;
    USE SIGNAL ;
    PORT
      LAYER M4 ;
        RECT  17.196 63.696 17.28 63.72 ;
    END
  END q[440]
  PIN q[441]
    DIRECTION OUTPUT ;
    USE SIGNAL ;
    PORT
      LAYER M4 ;
        RECT  17.196 63.792 17.28 63.816 ;
    END
  END q[441]
  PIN q[442]
    DIRECTION OUTPUT ;
    USE SIGNAL ;
    PORT
      LAYER M4 ;
        RECT  17.196 63.888 17.28 63.912 ;
    END
  END q[442]
  PIN q[443]
    DIRECTION OUTPUT ;
    USE SIGNAL ;
    PORT
      LAYER M4 ;
        RECT  17.196 63.984 17.28 64.008 ;
    END
  END q[443]
  PIN q[444]
    DIRECTION OUTPUT ;
    USE SIGNAL ;
    PORT
      LAYER M4 ;
        RECT  17.196 64.08 17.28 64.104 ;
    END
  END q[444]
  PIN q[445]
    DIRECTION OUTPUT ;
    USE SIGNAL ;
    PORT
      LAYER M4 ;
        RECT  17.196 64.176 17.28 64.2 ;
    END
  END q[445]
  PIN q[446]
    DIRECTION OUTPUT ;
    USE SIGNAL ;
    PORT
      LAYER M4 ;
        RECT  17.196 64.272 17.28 64.296 ;
    END
  END q[446]
  PIN q[447]
    DIRECTION OUTPUT ;
    USE SIGNAL ;
    PORT
      LAYER M4 ;
        RECT  17.196 64.368 17.28 64.392 ;
    END
  END q[447]
  PIN q[448]
    DIRECTION OUTPUT ;
    USE SIGNAL ;
    PORT
      LAYER M4 ;
        RECT  17.196 64.464 17.28 64.488 ;
    END
  END q[448]
  PIN q[449]
    DIRECTION OUTPUT ;
    USE SIGNAL ;
    PORT
      LAYER M4 ;
        RECT  17.196 64.56 17.28 64.584 ;
    END
  END q[449]
  PIN q[44]
    DIRECTION OUTPUT ;
    USE SIGNAL ;
    PORT
      LAYER M4 ;
        RECT  17.196 87.888 17.28 87.912 ;
    END
  END q[44]
  PIN q[450]
    DIRECTION OUTPUT ;
    USE SIGNAL ;
    PORT
      LAYER M4 ;
        RECT  17.196 64.656 17.28 64.68 ;
    END
  END q[450]
  PIN q[451]
    DIRECTION OUTPUT ;
    USE SIGNAL ;
    PORT
      LAYER M4 ;
        RECT  17.196 64.752 17.28 64.776 ;
    END
  END q[451]
  PIN q[452]
    DIRECTION OUTPUT ;
    USE SIGNAL ;
    PORT
      LAYER M4 ;
        RECT  17.196 64.848 17.28 64.872 ;
    END
  END q[452]
  PIN q[453]
    DIRECTION OUTPUT ;
    USE SIGNAL ;
    PORT
      LAYER M4 ;
        RECT  17.196 64.944 17.28 64.968 ;
    END
  END q[453]
  PIN q[454]
    DIRECTION OUTPUT ;
    USE SIGNAL ;
    PORT
      LAYER M4 ;
        RECT  17.196 65.04 17.28 65.064 ;
    END
  END q[454]
  PIN q[455]
    DIRECTION OUTPUT ;
    USE SIGNAL ;
    PORT
      LAYER M4 ;
        RECT  17.196 65.136 17.28 65.16 ;
    END
  END q[455]
  PIN q[456]
    DIRECTION OUTPUT ;
    USE SIGNAL ;
    PORT
      LAYER M4 ;
        RECT  17.196 65.232 17.28 65.256 ;
    END
  END q[456]
  PIN q[457]
    DIRECTION OUTPUT ;
    USE SIGNAL ;
    PORT
      LAYER M4 ;
        RECT  17.196 65.328 17.28 65.352 ;
    END
  END q[457]
  PIN q[458]
    DIRECTION OUTPUT ;
    USE SIGNAL ;
    PORT
      LAYER M4 ;
        RECT  17.196 65.424 17.28 65.448 ;
    END
  END q[458]
  PIN q[459]
    DIRECTION OUTPUT ;
    USE SIGNAL ;
    PORT
      LAYER M4 ;
        RECT  17.196 65.52 17.28 65.544 ;
    END
  END q[459]
  PIN q[45]
    DIRECTION OUTPUT ;
    USE SIGNAL ;
    PORT
      LAYER M4 ;
        RECT  17.196 87.984 17.28 88.008 ;
    END
  END q[45]
  PIN q[460]
    DIRECTION OUTPUT ;
    USE SIGNAL ;
    PORT
      LAYER M4 ;
        RECT  17.196 65.616 17.28 65.64 ;
    END
  END q[460]
  PIN q[461]
    DIRECTION OUTPUT ;
    USE SIGNAL ;
    PORT
      LAYER M4 ;
        RECT  17.196 65.712 17.28 65.736 ;
    END
  END q[461]
  PIN q[462]
    DIRECTION OUTPUT ;
    USE SIGNAL ;
    PORT
      LAYER M4 ;
        RECT  17.196 65.808 17.28 65.832 ;
    END
  END q[462]
  PIN q[463]
    DIRECTION OUTPUT ;
    USE SIGNAL ;
    PORT
      LAYER M4 ;
        RECT  17.196 65.904 17.28 65.928 ;
    END
  END q[463]
  PIN q[464]
    DIRECTION OUTPUT ;
    USE SIGNAL ;
    PORT
      LAYER M4 ;
        RECT  17.196 66 17.28 66.024 ;
    END
  END q[464]
  PIN q[465]
    DIRECTION OUTPUT ;
    USE SIGNAL ;
    PORT
      LAYER M4 ;
        RECT  17.196 66.096 17.28 66.12 ;
    END
  END q[465]
  PIN q[466]
    DIRECTION OUTPUT ;
    USE SIGNAL ;
    PORT
      LAYER M4 ;
        RECT  17.196 66.192 17.28 66.216 ;
    END
  END q[466]
  PIN q[467]
    DIRECTION OUTPUT ;
    USE SIGNAL ;
    PORT
      LAYER M4 ;
        RECT  17.196 66.288 17.28 66.312 ;
    END
  END q[467]
  PIN q[468]
    DIRECTION OUTPUT ;
    USE SIGNAL ;
    PORT
      LAYER M4 ;
        RECT  17.196 66.384 17.28 66.408 ;
    END
  END q[468]
  PIN q[469]
    DIRECTION OUTPUT ;
    USE SIGNAL ;
    PORT
      LAYER M4 ;
        RECT  17.196 66.48 17.28 66.504 ;
    END
  END q[469]
  PIN q[46]
    DIRECTION OUTPUT ;
    USE SIGNAL ;
    PORT
      LAYER M4 ;
        RECT  17.196 88.08 17.28 88.104 ;
    END
  END q[46]
  PIN q[470]
    DIRECTION OUTPUT ;
    USE SIGNAL ;
    PORT
      LAYER M4 ;
        RECT  17.196 66.576 17.28 66.6 ;
    END
  END q[470]
  PIN q[471]
    DIRECTION OUTPUT ;
    USE SIGNAL ;
    PORT
      LAYER M4 ;
        RECT  17.196 66.672 17.28 66.696 ;
    END
  END q[471]
  PIN q[472]
    DIRECTION OUTPUT ;
    USE SIGNAL ;
    PORT
      LAYER M4 ;
        RECT  17.196 66.768 17.28 66.792 ;
    END
  END q[472]
  PIN q[473]
    DIRECTION OUTPUT ;
    USE SIGNAL ;
    PORT
      LAYER M4 ;
        RECT  17.196 66.864 17.28 66.888 ;
    END
  END q[473]
  PIN q[474]
    DIRECTION OUTPUT ;
    USE SIGNAL ;
    PORT
      LAYER M4 ;
        RECT  17.196 66.96 17.28 66.984 ;
    END
  END q[474]
  PIN q[475]
    DIRECTION OUTPUT ;
    USE SIGNAL ;
    PORT
      LAYER M4 ;
        RECT  17.196 67.056 17.28 67.08 ;
    END
  END q[475]
  PIN q[476]
    DIRECTION OUTPUT ;
    USE SIGNAL ;
    PORT
      LAYER M4 ;
        RECT  17.196 67.152 17.28 67.176 ;
    END
  END q[476]
  PIN q[477]
    DIRECTION OUTPUT ;
    USE SIGNAL ;
    PORT
      LAYER M4 ;
        RECT  17.196 67.248 17.28 67.272 ;
    END
  END q[477]
  PIN q[478]
    DIRECTION OUTPUT ;
    USE SIGNAL ;
    PORT
      LAYER M4 ;
        RECT  17.196 67.344 17.28 67.368 ;
    END
  END q[478]
  PIN q[479]
    DIRECTION OUTPUT ;
    USE SIGNAL ;
    PORT
      LAYER M4 ;
        RECT  17.196 67.44 17.28 67.464 ;
    END
  END q[479]
  PIN q[47]
    DIRECTION OUTPUT ;
    USE SIGNAL ;
    PORT
      LAYER M4 ;
        RECT  17.196 88.176 17.28 88.2 ;
    END
  END q[47]
  PIN q[48]
    DIRECTION OUTPUT ;
    USE SIGNAL ;
    PORT
      LAYER M4 ;
        RECT  17.196 88.272 17.28 88.296 ;
    END
  END q[48]
  PIN q[49]
    DIRECTION OUTPUT ;
    USE SIGNAL ;
    PORT
      LAYER M4 ;
        RECT  17.196 88.368 17.28 88.392 ;
    END
  END q[49]
  PIN q[4]
    DIRECTION OUTPUT ;
    USE SIGNAL ;
    PORT
      LAYER M4 ;
        RECT  17.196 90.192 17.28 90.216 ;
    END
  END q[4]
  PIN q[50]
    DIRECTION OUTPUT ;
    USE SIGNAL ;
    PORT
      LAYER M4 ;
        RECT  17.196 88.464 17.28 88.488 ;
    END
  END q[50]
  PIN q[51]
    DIRECTION OUTPUT ;
    USE SIGNAL ;
    PORT
      LAYER M4 ;
        RECT  17.196 88.56 17.28 88.584 ;
    END
  END q[51]
  PIN q[52]
    DIRECTION OUTPUT ;
    USE SIGNAL ;
    PORT
      LAYER M4 ;
        RECT  17.196 88.656 17.28 88.68 ;
    END
  END q[52]
  PIN q[53]
    DIRECTION OUTPUT ;
    USE SIGNAL ;
    PORT
      LAYER M4 ;
        RECT  17.196 88.752 17.28 88.776 ;
    END
  END q[53]
  PIN q[54]
    DIRECTION OUTPUT ;
    USE SIGNAL ;
    PORT
      LAYER M4 ;
        RECT  17.196 88.848 17.28 88.872 ;
    END
  END q[54]
  PIN q[55]
    DIRECTION OUTPUT ;
    USE SIGNAL ;
    PORT
      LAYER M4 ;
        RECT  17.196 88.944 17.28 88.968 ;
    END
  END q[55]
  PIN q[56]
    DIRECTION OUTPUT ;
    USE SIGNAL ;
    PORT
      LAYER M4 ;
        RECT  17.196 89.04 17.28 89.064 ;
    END
  END q[56]
  PIN q[57]
    DIRECTION OUTPUT ;
    USE SIGNAL ;
    PORT
      LAYER M4 ;
        RECT  17.196 89.136 17.28 89.16 ;
    END
  END q[57]
  PIN q[58]
    DIRECTION OUTPUT ;
    USE SIGNAL ;
    PORT
      LAYER M4 ;
        RECT  17.196 89.232 17.28 89.256 ;
    END
  END q[58]
  PIN q[59]
    DIRECTION OUTPUT ;
    USE SIGNAL ;
    PORT
      LAYER M4 ;
        RECT  17.196 89.328 17.28 89.352 ;
    END
  END q[59]
  PIN q[5]
    DIRECTION OUTPUT ;
    USE SIGNAL ;
    PORT
      LAYER M4 ;
        RECT  17.196 90.288 17.28 90.312 ;
    END
  END q[5]
  PIN q[60]
    DIRECTION OUTPUT ;
    USE SIGNAL ;
    PORT
      LAYER M4 ;
        RECT  17.196 89.424 17.28 89.448 ;
    END
  END q[60]
  PIN q[61]
    DIRECTION OUTPUT ;
    USE SIGNAL ;
    PORT
      LAYER M4 ;
        RECT  17.196 89.52 17.28 89.544 ;
    END
  END q[61]
  PIN q[62]
    DIRECTION OUTPUT ;
    USE SIGNAL ;
    PORT
      LAYER M4 ;
        RECT  17.196 89.616 17.28 89.64 ;
    END
  END q[62]
  PIN q[63]
    DIRECTION OUTPUT ;
    USE SIGNAL ;
    PORT
      LAYER M4 ;
        RECT  17.196 89.712 17.28 89.736 ;
    END
  END q[63]
  PIN q[64]
    DIRECTION OUTPUT ;
    USE SIGNAL ;
    PORT
      LAYER M4 ;
        RECT  17.196 73.68 17.28 73.704 ;
    END
  END q[64]
  PIN q[65]
    DIRECTION OUTPUT ;
    USE SIGNAL ;
    PORT
      LAYER M4 ;
        RECT  17.196 73.776 17.28 73.8 ;
    END
  END q[65]
  PIN q[66]
    DIRECTION OUTPUT ;
    USE SIGNAL ;
    PORT
      LAYER M4 ;
        RECT  17.196 73.872 17.28 73.896 ;
    END
  END q[66]
  PIN q[67]
    DIRECTION OUTPUT ;
    USE SIGNAL ;
    PORT
      LAYER M4 ;
        RECT  17.196 73.968 17.28 73.992 ;
    END
  END q[67]
  PIN q[68]
    DIRECTION OUTPUT ;
    USE SIGNAL ;
    PORT
      LAYER M4 ;
        RECT  17.196 74.064 17.28 74.088 ;
    END
  END q[68]
  PIN q[69]
    DIRECTION OUTPUT ;
    USE SIGNAL ;
    PORT
      LAYER M4 ;
        RECT  17.196 74.16 17.28 74.184 ;
    END
  END q[69]
  PIN q[6]
    DIRECTION OUTPUT ;
    USE SIGNAL ;
    PORT
      LAYER M4 ;
        RECT  17.196 90.384 17.28 90.408 ;
    END
  END q[6]
  PIN q[70]
    DIRECTION OUTPUT ;
    USE SIGNAL ;
    PORT
      LAYER M4 ;
        RECT  17.196 74.256 17.28 74.28 ;
    END
  END q[70]
  PIN q[71]
    DIRECTION OUTPUT ;
    USE SIGNAL ;
    PORT
      LAYER M4 ;
        RECT  17.196 74.352 17.28 74.376 ;
    END
  END q[71]
  PIN q[72]
    DIRECTION OUTPUT ;
    USE SIGNAL ;
    PORT
      LAYER M4 ;
        RECT  17.196 74.448 17.28 74.472 ;
    END
  END q[72]
  PIN q[73]
    DIRECTION OUTPUT ;
    USE SIGNAL ;
    PORT
      LAYER M4 ;
        RECT  17.196 74.544 17.28 74.568 ;
    END
  END q[73]
  PIN q[74]
    DIRECTION OUTPUT ;
    USE SIGNAL ;
    PORT
      LAYER M4 ;
        RECT  17.196 74.64 17.28 74.664 ;
    END
  END q[74]
  PIN q[75]
    DIRECTION OUTPUT ;
    USE SIGNAL ;
    PORT
      LAYER M4 ;
        RECT  17.196 74.736 17.28 74.76 ;
    END
  END q[75]
  PIN q[76]
    DIRECTION OUTPUT ;
    USE SIGNAL ;
    PORT
      LAYER M4 ;
        RECT  17.196 74.832 17.28 74.856 ;
    END
  END q[76]
  PIN q[77]
    DIRECTION OUTPUT ;
    USE SIGNAL ;
    PORT
      LAYER M4 ;
        RECT  17.196 74.928 17.28 74.952 ;
    END
  END q[77]
  PIN q[78]
    DIRECTION OUTPUT ;
    USE SIGNAL ;
    PORT
      LAYER M4 ;
        RECT  17.196 75.024 17.28 75.048 ;
    END
  END q[78]
  PIN q[79]
    DIRECTION OUTPUT ;
    USE SIGNAL ;
    PORT
      LAYER M4 ;
        RECT  17.196 75.12 17.28 75.144 ;
    END
  END q[79]
  PIN q[7]
    DIRECTION OUTPUT ;
    USE SIGNAL ;
    PORT
      LAYER M4 ;
        RECT  17.196 90.48 17.28 90.504 ;
    END
  END q[7]
  PIN q[80]
    DIRECTION OUTPUT ;
    USE SIGNAL ;
    PORT
      LAYER M4 ;
        RECT  17.196 75.216 17.28 75.24 ;
    END
  END q[80]
  PIN q[81]
    DIRECTION OUTPUT ;
    USE SIGNAL ;
    PORT
      LAYER M4 ;
        RECT  17.196 75.312 17.28 75.336 ;
    END
  END q[81]
  PIN q[82]
    DIRECTION OUTPUT ;
    USE SIGNAL ;
    PORT
      LAYER M4 ;
        RECT  17.196 75.408 17.28 75.432 ;
    END
  END q[82]
  PIN q[83]
    DIRECTION OUTPUT ;
    USE SIGNAL ;
    PORT
      LAYER M4 ;
        RECT  17.196 75.504 17.28 75.528 ;
    END
  END q[83]
  PIN q[84]
    DIRECTION OUTPUT ;
    USE SIGNAL ;
    PORT
      LAYER M4 ;
        RECT  17.196 75.6 17.28 75.624 ;
    END
  END q[84]
  PIN q[85]
    DIRECTION OUTPUT ;
    USE SIGNAL ;
    PORT
      LAYER M4 ;
        RECT  17.196 75.696 17.28 75.72 ;
    END
  END q[85]
  PIN q[86]
    DIRECTION OUTPUT ;
    USE SIGNAL ;
    PORT
      LAYER M4 ;
        RECT  17.196 75.792 17.28 75.816 ;
    END
  END q[86]
  PIN q[87]
    DIRECTION OUTPUT ;
    USE SIGNAL ;
    PORT
      LAYER M4 ;
        RECT  17.196 75.888 17.28 75.912 ;
    END
  END q[87]
  PIN q[88]
    DIRECTION OUTPUT ;
    USE SIGNAL ;
    PORT
      LAYER M4 ;
        RECT  17.196 75.984 17.28 76.008 ;
    END
  END q[88]
  PIN q[89]
    DIRECTION OUTPUT ;
    USE SIGNAL ;
    PORT
      LAYER M4 ;
        RECT  17.196 76.08 17.28 76.104 ;
    END
  END q[89]
  PIN q[8]
    DIRECTION OUTPUT ;
    USE SIGNAL ;
    PORT
      LAYER M4 ;
        RECT  17.196 90.576 17.28 90.6 ;
    END
  END q[8]
  PIN q[90]
    DIRECTION OUTPUT ;
    USE SIGNAL ;
    PORT
      LAYER M4 ;
        RECT  17.196 76.176 17.28 76.2 ;
    END
  END q[90]
  PIN q[91]
    DIRECTION OUTPUT ;
    USE SIGNAL ;
    PORT
      LAYER M4 ;
        RECT  17.196 76.272 17.28 76.296 ;
    END
  END q[91]
  PIN q[92]
    DIRECTION OUTPUT ;
    USE SIGNAL ;
    PORT
      LAYER M4 ;
        RECT  17.196 76.368 17.28 76.392 ;
    END
  END q[92]
  PIN q[93]
    DIRECTION OUTPUT ;
    USE SIGNAL ;
    PORT
      LAYER M4 ;
        RECT  17.196 76.464 17.28 76.488 ;
    END
  END q[93]
  PIN q[94]
    DIRECTION OUTPUT ;
    USE SIGNAL ;
    PORT
      LAYER M4 ;
        RECT  17.196 76.56 17.28 76.584 ;
    END
  END q[94]
  PIN q[95]
    DIRECTION OUTPUT ;
    USE SIGNAL ;
    PORT
      LAYER M4 ;
        RECT  17.196 76.656 17.28 76.68 ;
    END
  END q[95]
  PIN q[96]
    DIRECTION OUTPUT ;
    USE SIGNAL ;
    PORT
      LAYER M4 ;
        RECT  17.196 77.52 17.28 77.544 ;
    END
  END q[96]
  PIN q[97]
    DIRECTION OUTPUT ;
    USE SIGNAL ;
    PORT
      LAYER M4 ;
        RECT  17.196 77.616 17.28 77.64 ;
    END
  END q[97]
  PIN q[98]
    DIRECTION OUTPUT ;
    USE SIGNAL ;
    PORT
      LAYER M4 ;
        RECT  17.196 77.712 17.28 77.736 ;
    END
  END q[98]
  PIN q[99]
    DIRECTION OUTPUT ;
    USE SIGNAL ;
    PORT
      LAYER M4 ;
        RECT  17.196 77.808 17.28 77.832 ;
    END
  END q[99]
  PIN q[9]
    DIRECTION OUTPUT ;
    USE SIGNAL ;
    PORT
      LAYER M4 ;
        RECT  17.196 90.672 17.28 90.696 ;
    END
  END q[9]
  PIN VSS
    DIRECTION INOUT ;
    USE GROUND ;
    PORT
      LAYER M5 ;
        RECT  13.2 2.137 13.32 95.063 ;
        RECT  7.8 2.137 7.92 95.063 ;
        RECT  2.4 2.137 2.52 95.063 ;
    END
  END VSS
  PIN VDD
    DIRECTION INOUT ;
    USE POWER ;
    PORT
      LAYER M5 ;
        RECT  13.392 2.151 13.512 95.049 ;
        RECT  7.992 2.151 8.112 95.049 ;
        RECT  2.592 2.151 2.712 95.049 ;
    END
  END VDD
  # OT_OBS_CLOSED layer=M5 d_um=1.536 added=174
  OBS
    LAYER RVTN ;
     RECT  2.16 2.16 15.12 2.295 ;
     RECT  2.16 2.565 15.12 2.835 ;
     RECT  2.16 3.105 15.12 3.375 ;
     RECT  2.16 3.645 15.12 3.915 ;
     RECT  2.16 4.185 15.12 4.455 ;
     RECT  2.16 4.725 15.12 4.995 ;
     RECT  2.16 5.265 15.12 5.535 ;
     RECT  2.16 5.805 15.12 6.075 ;
     RECT  2.16 6.345 15.12 6.615 ;
     RECT  2.16 6.885 15.12 7.155 ;
     RECT  2.16 7.425 15.12 7.695 ;
     RECT  2.16 7.965 15.12 8.235 ;
     RECT  2.16 8.505 15.12 8.775 ;
     RECT  2.16 9.045 15.12 9.315 ;
     RECT  2.16 9.585 15.12 9.855 ;
     RECT  2.16 10.125 15.12 10.395 ;
     RECT  2.16 10.665 15.12 10.935 ;
     RECT  2.16 11.205 15.12 11.475 ;
     RECT  2.16 11.745 15.12 12.015 ;
     RECT  2.16 12.285 15.12 12.555 ;
     RECT  2.16 12.825 15.12 13.095 ;
     RECT  2.16 13.365 15.12 13.635 ;
     RECT  2.16 13.905 15.12 14.175 ;
     RECT  2.16 14.445 15.12 14.715 ;
     RECT  2.16 14.985 15.12 15.255 ;
     RECT  2.16 15.525 15.12 15.795 ;
     RECT  2.16 16.065 15.12 16.335 ;
     RECT  2.16 16.605 15.12 16.875 ;
     RECT  2.16 17.145 15.12 17.415 ;
     RECT  2.16 17.685 15.12 17.955 ;
     RECT  2.16 18.225 15.12 18.495 ;
     RECT  2.16 18.765 15.12 19.035 ;
     RECT  2.16 19.305 15.12 19.575 ;
     RECT  2.16 19.845 15.12 20.115 ;
     RECT  2.16 20.385 15.12 20.655 ;
     RECT  2.16 20.925 15.12 21.195 ;
     RECT  2.16 21.465 15.12 21.735 ;
     RECT  2.16 22.005 15.12 22.275 ;
     RECT  2.16 22.545 15.12 22.815 ;
     RECT  2.16 23.085 15.12 23.355 ;
     RECT  2.16 23.625 15.12 23.895 ;
     RECT  2.16 24.165 15.12 24.435 ;
     RECT  2.16 24.705 15.12 24.975 ;
     RECT  2.16 25.245 15.12 25.515 ;
     RECT  2.16 25.785 15.12 26.055 ;
     RECT  2.16 26.325 15.12 26.595 ;
     RECT  2.16 26.865 15.12 27.135 ;
     RECT  2.16 27.405 15.12 27.675 ;
     RECT  2.16 27.945 15.12 28.215 ;
     RECT  2.16 28.485 15.12 28.755 ;
     RECT  2.16 29.025 15.12 29.295 ;
     RECT  2.16 29.565 15.12 29.835 ;
     RECT  2.16 30.105 15.12 30.375 ;
     RECT  2.16 30.645 15.12 30.915 ;
     RECT  2.16 31.185 15.12 31.455 ;
     RECT  2.16 31.725 15.12 31.995 ;
     RECT  2.16 32.265 15.12 32.535 ;
     RECT  2.16 32.805 15.12 33.075 ;
     RECT  2.16 33.345 15.12 33.615 ;
     RECT  2.16 33.885 15.12 34.155 ;
     RECT  2.16 34.425 15.12 34.695 ;
     RECT  2.16 34.965 15.12 35.235 ;
     RECT  2.16 35.505 15.12 35.775 ;
     RECT  2.16 36.045 15.12 36.315 ;
     RECT  2.16 36.585 15.12 36.855 ;
     RECT  2.16 37.125 15.12 37.395 ;
     RECT  2.16 37.665 15.12 37.935 ;
     RECT  2.16 38.205 15.12 38.475 ;
     RECT  2.16 38.745 15.12 39.015 ;
     RECT  2.16 39.285 15.12 39.555 ;
     RECT  2.16 39.825 15.12 40.095 ;
     RECT  2.16 40.365 15.12 40.635 ;
     RECT  2.16 40.905 15.12 41.175 ;
     RECT  2.16 41.445 15.12 41.715 ;
     RECT  2.16 41.985 15.12 42.255 ;
     RECT  2.16 42.525 15.12 42.795 ;
     RECT  2.16 43.065 15.12 43.335 ;
     RECT  2.16 43.605 15.12 43.875 ;
     RECT  2.16 44.145 15.12 44.415 ;
     RECT  2.16 44.685 15.12 44.955 ;
     RECT  2.16 45.225 15.12 45.495 ;
     RECT  2.16 45.765 15.12 46.035 ;
     RECT  2.16 46.305 15.12 46.575 ;
     RECT  2.16 46.845 15.12 47.115 ;
     RECT  2.16 47.385 15.12 47.655 ;
     RECT  2.16 47.925 15.12 48.195 ;
     RECT  2.16 48.465 15.12 48.735 ;
     RECT  2.16 49.005 15.12 49.275 ;
     RECT  2.16 49.545 15.12 49.815 ;
     RECT  2.16 50.085 15.12 50.355 ;
     RECT  2.16 50.625 15.12 50.895 ;
     RECT  2.16 51.165 15.12 51.435 ;
     RECT  2.16 51.705 15.12 51.975 ;
     RECT  2.16 52.245 15.12 52.515 ;
     RECT  2.16 52.785 15.12 53.055 ;
     RECT  2.16 53.325 15.12 53.595 ;
     RECT  2.16 53.865 15.12 54.135 ;
     RECT  2.16 54.405 15.12 54.675 ;
     RECT  2.16 54.945 15.12 55.215 ;
     RECT  2.16 55.485 15.12 55.755 ;
     RECT  2.16 56.025 15.12 56.295 ;
     RECT  2.16 56.565 15.12 56.835 ;
     RECT  2.16 57.105 15.12 57.375 ;
     RECT  2.16 57.645 15.12 57.915 ;
     RECT  2.16 58.185 15.12 58.455 ;
     RECT  2.16 58.725 15.12 58.995 ;
     RECT  2.16 59.265 15.12 59.535 ;
     RECT  2.16 59.805 15.12 60.075 ;
     RECT  2.16 60.345 15.12 60.615 ;
     RECT  2.16 60.885 15.12 61.155 ;
     RECT  2.16 61.425 15.12 61.695 ;
     RECT  2.16 61.965 15.12 62.235 ;
     RECT  2.16 62.505 15.12 62.775 ;
     RECT  2.16 63.045 15.12 63.315 ;
     RECT  2.16 63.585 15.12 63.855 ;
     RECT  2.16 64.125 15.12 64.395 ;
     RECT  2.16 64.665 15.12 64.935 ;
     RECT  2.16 65.205 15.12 65.475 ;
     RECT  2.16 65.745 15.12 66.015 ;
     RECT  2.16 66.285 15.12 66.555 ;
     RECT  2.16 66.825 15.12 67.095 ;
     RECT  2.16 67.365 15.12 67.635 ;
     RECT  2.16 67.905 15.12 68.175 ;
     RECT  2.16 68.445 15.12 68.715 ;
     RECT  2.16 68.985 15.12 69.255 ;
     RECT  2.16 69.525 15.12 69.795 ;
     RECT  2.16 70.065 15.12 70.335 ;
     RECT  2.16 70.605 15.12 70.875 ;
     RECT  2.16 71.145 15.12 71.415 ;
     RECT  2.16 71.685 15.12 71.955 ;
     RECT  2.16 72.225 15.12 72.495 ;
     RECT  2.16 72.765 15.12 73.035 ;
     RECT  2.16 73.305 15.12 73.575 ;
     RECT  2.16 73.845 15.12 74.115 ;
     RECT  2.16 74.385 15.12 74.655 ;
     RECT  2.16 74.925 15.12 75.195 ;
     RECT  2.16 75.465 15.12 75.735 ;
     RECT  2.16 76.005 15.12 76.275 ;
     RECT  2.16 76.545 15.12 76.815 ;
     RECT  2.16 77.085 15.12 77.355 ;
     RECT  2.16 77.625 15.12 77.895 ;
     RECT  2.16 78.165 15.12 78.435 ;
     RECT  2.16 78.705 15.12 78.975 ;
     RECT  2.16 79.245 15.12 79.515 ;
     RECT  2.16 79.785 15.12 80.055 ;
     RECT  2.16 80.325 15.12 80.595 ;
     RECT  2.16 80.865 15.12 81.135 ;
     RECT  2.16 81.405 15.12 81.675 ;
     RECT  2.16 81.945 15.12 82.215 ;
     RECT  2.16 82.485 15.12 82.755 ;
     RECT  2.16 83.025 15.12 83.295 ;
     RECT  2.16 83.565 15.12 83.835 ;
     RECT  2.16 84.105 15.12 84.375 ;
     RECT  2.16 84.645 15.12 84.915 ;
     RECT  2.16 85.185 15.12 85.455 ;
     RECT  2.16 85.725 15.12 85.995 ;
     RECT  2.16 86.265 15.12 86.535 ;
     RECT  2.16 86.805 15.12 87.075 ;
     RECT  2.16 87.345 15.12 87.615 ;
     RECT  2.16 87.885 15.12 88.155 ;
     RECT  2.16 88.425 15.12 88.695 ;
     RECT  2.16 88.965 15.12 89.235 ;
     RECT  2.16 89.505 15.12 89.775 ;
     RECT  2.16 90.045 15.12 90.315 ;
     RECT  2.16 90.585 15.12 90.855 ;
     RECT  2.16 91.125 15.12 91.395 ;
     RECT  2.16 91.665 15.12 91.935 ;
     RECT  2.16 92.205 15.12 92.475 ;
     RECT  2.16 92.745 15.12 93.015 ;
     RECT  2.16 93.285 15.12 93.555 ;
     RECT  2.16 93.825 15.12 94.095 ;
     RECT  2.16 94.365 15.12 94.635 ;
     RECT  2.16 94.905 15.12 95.04 ;
    LAYER RVTP ;
     RECT  2.16 2.295 15.12 2.565 ;
     RECT  2.16 2.835 15.12 3.105 ;
     RECT  2.16 3.375 15.12 3.645 ;
     RECT  2.16 3.915 15.12 4.185 ;
     RECT  2.16 4.455 15.12 4.725 ;
     RECT  2.16 4.995 15.12 5.265 ;
     RECT  2.16 5.535 15.12 5.805 ;
     RECT  2.16 6.075 15.12 6.345 ;
     RECT  2.16 6.615 15.12 6.885 ;
     RECT  2.16 7.155 15.12 7.425 ;
     RECT  2.16 7.695 15.12 7.965 ;
     RECT  2.16 8.235 15.12 8.505 ;
     RECT  2.16 8.775 15.12 9.045 ;
     RECT  2.16 9.315 15.12 9.585 ;
     RECT  2.16 9.855 15.12 10.125 ;
     RECT  2.16 10.395 15.12 10.665 ;
     RECT  2.16 10.935 15.12 11.205 ;
     RECT  2.16 11.475 15.12 11.745 ;
     RECT  2.16 12.015 15.12 12.285 ;
     RECT  2.16 12.555 15.12 12.825 ;
     RECT  2.16 13.095 15.12 13.365 ;
     RECT  2.16 13.635 15.12 13.905 ;
     RECT  2.16 14.175 15.12 14.445 ;
     RECT  2.16 14.715 15.12 14.985 ;
     RECT  2.16 15.255 15.12 15.525 ;
     RECT  2.16 15.795 15.12 16.065 ;
     RECT  2.16 16.335 15.12 16.605 ;
     RECT  2.16 16.875 15.12 17.145 ;
     RECT  2.16 17.415 15.12 17.685 ;
     RECT  2.16 17.955 15.12 18.225 ;
     RECT  2.16 18.495 15.12 18.765 ;
     RECT  2.16 19.035 15.12 19.305 ;
     RECT  2.16 19.575 15.12 19.845 ;
     RECT  2.16 20.115 15.12 20.385 ;
     RECT  2.16 20.655 15.12 20.925 ;
     RECT  2.16 21.195 15.12 21.465 ;
     RECT  2.16 21.735 15.12 22.005 ;
     RECT  2.16 22.275 15.12 22.545 ;
     RECT  2.16 22.815 15.12 23.085 ;
     RECT  2.16 23.355 15.12 23.625 ;
     RECT  2.16 23.895 15.12 24.165 ;
     RECT  2.16 24.435 15.12 24.705 ;
     RECT  2.16 24.975 15.12 25.245 ;
     RECT  2.16 25.515 15.12 25.785 ;
     RECT  2.16 26.055 15.12 26.325 ;
     RECT  2.16 26.595 15.12 26.865 ;
     RECT  2.16 27.135 15.12 27.405 ;
     RECT  2.16 27.675 15.12 27.945 ;
     RECT  2.16 28.215 15.12 28.485 ;
     RECT  2.16 28.755 15.12 29.025 ;
     RECT  2.16 29.295 15.12 29.565 ;
     RECT  2.16 29.835 15.12 30.105 ;
     RECT  2.16 30.375 15.12 30.645 ;
     RECT  2.16 30.915 15.12 31.185 ;
     RECT  2.16 31.455 15.12 31.725 ;
     RECT  2.16 31.995 15.12 32.265 ;
     RECT  2.16 32.535 15.12 32.805 ;
     RECT  2.16 33.075 15.12 33.345 ;
     RECT  2.16 33.615 15.12 33.885 ;
     RECT  2.16 34.155 15.12 34.425 ;
     RECT  2.16 34.695 15.12 34.965 ;
     RECT  2.16 35.235 15.12 35.505 ;
     RECT  2.16 35.775 15.12 36.045 ;
     RECT  2.16 36.315 15.12 36.585 ;
     RECT  2.16 36.855 15.12 37.125 ;
     RECT  2.16 37.395 15.12 37.665 ;
     RECT  2.16 37.935 15.12 38.205 ;
     RECT  2.16 38.475 15.12 38.745 ;
     RECT  2.16 39.015 15.12 39.285 ;
     RECT  2.16 39.555 15.12 39.825 ;
     RECT  2.16 40.095 15.12 40.365 ;
     RECT  2.16 40.635 15.12 40.905 ;
     RECT  2.16 41.175 15.12 41.445 ;
     RECT  2.16 41.715 15.12 41.985 ;
     RECT  2.16 42.255 15.12 42.525 ;
     RECT  2.16 42.795 15.12 43.065 ;
     RECT  2.16 43.335 15.12 43.605 ;
     RECT  2.16 43.875 15.12 44.145 ;
     RECT  2.16 44.415 15.12 44.685 ;
     RECT  2.16 44.955 15.12 45.225 ;
     RECT  2.16 45.495 15.12 45.765 ;
     RECT  2.16 46.035 15.12 46.305 ;
     RECT  2.16 46.575 15.12 46.845 ;
     RECT  2.16 47.115 15.12 47.385 ;
     RECT  2.16 47.655 15.12 47.925 ;
     RECT  2.16 48.195 15.12 48.465 ;
     RECT  2.16 48.735 15.12 49.005 ;
     RECT  2.16 49.275 15.12 49.545 ;
     RECT  2.16 49.815 15.12 50.085 ;
     RECT  2.16 50.355 15.12 50.625 ;
     RECT  2.16 50.895 15.12 51.165 ;
     RECT  2.16 51.435 15.12 51.705 ;
     RECT  2.16 51.975 15.12 52.245 ;
     RECT  2.16 52.515 15.12 52.785 ;
     RECT  2.16 53.055 15.12 53.325 ;
     RECT  2.16 53.595 15.12 53.865 ;
     RECT  2.16 54.135 15.12 54.405 ;
     RECT  2.16 54.675 15.12 54.945 ;
     RECT  2.16 55.215 15.12 55.485 ;
     RECT  2.16 55.755 15.12 56.025 ;
     RECT  2.16 56.295 15.12 56.565 ;
     RECT  2.16 56.835 15.12 57.105 ;
     RECT  2.16 57.375 15.12 57.645 ;
     RECT  2.16 57.915 15.12 58.185 ;
     RECT  2.16 58.455 15.12 58.725 ;
     RECT  2.16 58.995 15.12 59.265 ;
     RECT  2.16 59.535 15.12 59.805 ;
     RECT  2.16 60.075 15.12 60.345 ;
     RECT  2.16 60.615 15.12 60.885 ;
     RECT  2.16 61.155 15.12 61.425 ;
     RECT  2.16 61.695 15.12 61.965 ;
     RECT  2.16 62.235 15.12 62.505 ;
     RECT  2.16 62.775 15.12 63.045 ;
     RECT  2.16 63.315 15.12 63.585 ;
     RECT  2.16 63.855 15.12 64.125 ;
     RECT  2.16 64.395 15.12 64.665 ;
     RECT  2.16 64.935 15.12 65.205 ;
     RECT  2.16 65.475 15.12 65.745 ;
     RECT  2.16 66.015 15.12 66.285 ;
     RECT  2.16 66.555 15.12 66.825 ;
     RECT  2.16 67.095 15.12 67.365 ;
     RECT  2.16 67.635 15.12 67.905 ;
     RECT  2.16 68.175 15.12 68.445 ;
     RECT  2.16 68.715 15.12 68.985 ;
     RECT  2.16 69.255 15.12 69.525 ;
     RECT  2.16 69.795 15.12 70.065 ;
     RECT  2.16 70.335 15.12 70.605 ;
     RECT  2.16 70.875 15.12 71.145 ;
     RECT  2.16 71.415 15.12 71.685 ;
     RECT  2.16 71.955 15.12 72.225 ;
     RECT  2.16 72.495 15.12 72.765 ;
     RECT  2.16 73.035 15.12 73.305 ;
     RECT  2.16 73.575 15.12 73.845 ;
     RECT  2.16 74.115 15.12 74.385 ;
     RECT  2.16 74.655 15.12 74.925 ;
     RECT  2.16 75.195 15.12 75.465 ;
     RECT  2.16 75.735 15.12 76.005 ;
     RECT  2.16 76.275 15.12 76.545 ;
     RECT  2.16 76.815 15.12 77.085 ;
     RECT  2.16 77.355 15.12 77.625 ;
     RECT  2.16 77.895 15.12 78.165 ;
     RECT  2.16 78.435 15.12 78.705 ;
     RECT  2.16 78.975 15.12 79.245 ;
     RECT  2.16 79.515 15.12 79.785 ;
     RECT  2.16 80.055 15.12 80.325 ;
     RECT  2.16 80.595 15.12 80.865 ;
     RECT  2.16 81.135 15.12 81.405 ;
     RECT  2.16 81.675 15.12 81.945 ;
     RECT  2.16 82.215 15.12 82.485 ;
     RECT  2.16 82.755 15.12 83.025 ;
     RECT  2.16 83.295 15.12 83.565 ;
     RECT  2.16 83.835 15.12 84.105 ;
     RECT  2.16 84.375 15.12 84.645 ;
     RECT  2.16 84.915 15.12 85.185 ;
     RECT  2.16 85.455 15.12 85.725 ;
     RECT  2.16 85.995 15.12 86.265 ;
     RECT  2.16 86.535 15.12 86.805 ;
     RECT  2.16 87.075 15.12 87.345 ;
     RECT  2.16 87.615 15.12 87.885 ;
     RECT  2.16 88.155 15.12 88.425 ;
     RECT  2.16 88.695 15.12 88.965 ;
     RECT  2.16 89.235 15.12 89.505 ;
     RECT  2.16 89.775 15.12 90.045 ;
     RECT  2.16 90.315 15.12 90.585 ;
     RECT  2.16 90.855 15.12 91.125 ;
     RECT  2.16 91.395 15.12 91.665 ;
     RECT  2.16 91.935 15.12 92.205 ;
     RECT  2.16 92.475 15.12 92.745 ;
     RECT  2.16 93.015 15.12 93.285 ;
     RECT  2.16 93.555 15.12 93.825 ;
     RECT  2.16 94.095 15.12 94.365 ;
     RECT  2.16 94.635 15.12 94.905 ;
    LAYER M1 ;
     RECT  2.16 2.151 15.12 95.049 ;
    LAYER M2 ;
     RECT  0.031 86.616 0.067 86.634 ;
     RECT  0.031 92.142 0.067 92.16 ;
     RECT  0.031 52.992 0.103 53.01 ;
     RECT  0.031 55.8 0.103 55.818 ;
     RECT  0.067 86.616 0.131 86.868 ;
     RECT  0.103 4.932 0.139 5.598 ;
     RECT  0.103 6.894 0.139 6.912 ;
     RECT  0.103 32.706 0.139 32.994 ;
     RECT  0.103 52.722 0.139 53.01 ;
     RECT  0.067 54.108 0.139 54.126 ;
     RECT  0.103 77.94 0.139 79.002 ;
     RECT  0.103 90.522 0.139 90.54 ;
     RECT  0.067 91.602 0.139 92.16 ;
     RECT  0.067 57.231 0.167 57.249 ;
     RECT  0.103 12.024 0.175 12.042 ;
     RECT  0.103 19.242 0.175 19.26 ;
     RECT  0.103 55.26 0.175 55.818 ;
     RECT  0.103 59.238 0.175 59.76 ;
     RECT  0.103 63.396 0.175 63.414 ;
     RECT  0.103 64.206 0.175 64.224 ;
     RECT  0.103 71.694 0.175 71.712 ;
     RECT  0.139 84.996 0.175 85.014 ;
     RECT  0.131 86.85 0.203 86.868 ;
     RECT  0.139 4.734 0.211 5.598 ;
     RECT  0.175 19.116 0.211 19.26 ;
     RECT  0.175 59.202 0.211 59.76 ;
     RECT  0.175 63.396 0.211 64.224 ;
     RECT  0.103 68.958 0.211 68.976 ;
     RECT  0.175 89.208 0.211 89.226 ;
     RECT  0.139 73.008 0.239 73.026 ;
     RECT  0.175 84.852 0.239 85.014 ;
     RECT  0.139 38.556 0.247 38.574 ;
     RECT  0.175 67.95 0.247 67.968 ;
     RECT  0.247 67.95 0.319 68.13 ;
     RECT  0.211 68.922 0.319 68.976 ;
     RECT  0.139 34.74 0.347 35.298 ;
     RECT  0.103 41.22 0.347 41.238 ;
     RECT  0.103 47.736 0.347 47.754 ;
     RECT  0.211 63.252 0.383 64.224 ;
     RECT  0.031 30.771 0.391 30.789 ;
     RECT  0.139 32.472 0.391 32.994 ;
     RECT  0.319 82.296 0.419 82.314 ;
     RECT  0.031 27.756 0.427 27.774 ;
     RECT  0.355 29.196 0.427 29.214 ;
     RECT  0.391 31.851 0.427 32.994 ;
     RECT  0.139 77.94 0.427 79.236 ;
     RECT  0.427 27.756 0.463 28.404 ;
     RECT  0.427 29.196 0.463 29.286 ;
     RECT  0.175 54.99 0.463 55.818 ;
     RECT  0.239 84.852 0.463 84.87 ;
     RECT  0.463 27.756 0.499 29.286 ;
     RECT  0.391 30.078 0.499 30.789 ;
     RECT  0.427 31.698 0.499 33.066 ;
     RECT  0.139 52.722 0.499 54.126 ;
     RECT  0.463 54.99 0.499 56.052 ;
     RECT  0.175 71.622 0.499 71.712 ;
     RECT  0.427 77.4 0.499 79.236 ;
     RECT  0.499 3.618 0.535 3.636 ;
     RECT  0.211 4.5 0.535 5.598 ;
     RECT  0.139 6.588 0.535 6.912 ;
     RECT  0.499 27.756 0.535 33.066 ;
     RECT  0.499 54.99 0.535 56.286 ;
     RECT  0.319 67.95 0.823 68.976 ;
     RECT  0.383 64.206 0.851 64.224 ;
     RECT  0.823 67.95 1.975 69.354 ;
     RECT  1.399 92.952 1.975 92.97 ;
     RECT  0.823 93.762 1.975 93.78 ;
     RECT  0.383 63.252 2.119 63.414 ;
     RECT  0.535 3.618 2.16 3.708 ;
     RECT  0.535 4.5 2.16 6.912 ;
     RECT  0.175 12.024 2.16 12.384 ;
     RECT  0.211 18.432 2.16 19.26 ;
     RECT  0.535 20.43 2.16 20.448 ;
     RECT  0.535 21.51 2.16 21.528 ;
     RECT  0.103 26.262 2.16 26.28 ;
     RECT  0.535 27.756 2.16 33.444 ;
     RECT  0.347 34.74 2.16 34.758 ;
     RECT  0.103 37.476 2.16 37.494 ;
     RECT  0.247 38.52 2.16 38.574 ;
     RECT  0.103 42.876 2.16 42.894 ;
     RECT  0.103 46.08 2.16 46.638 ;
     RECT  0.499 52.524 2.16 54.126 ;
     RECT  0.535 54.99 2.16 56.898 ;
     RECT  0.211 58.5 2.16 59.76 ;
     RECT  0.247 60.822 2.16 60.84 ;
     RECT  2.119 63.054 2.16 63.414 ;
     RECT  1.723 65.214 2.16 65.232 ;
     RECT  0.139 67.032 2.16 67.05 ;
     RECT  1.975 67.95 2.16 69.48 ;
     RECT  0.499 71.622 2.16 72.324 ;
     RECT  0.499 77.328 2.16 79.236 ;
     RECT  0.103 80.874 2.16 80.892 ;
     RECT  0.463 84.312 2.16 84.87 ;
     RECT  0.211 89.208 2.16 89.694 ;
     RECT  0.139 90.522 2.16 92.16 ;
     RECT  1.975 92.952 2.16 93.78 ;
     RECT  2.16 2.151 11.623 95.049 ;
     RECT  11.623 2.106 13.559 95.049 ;
     RECT  13.559 2.151 15.12 95.049 ;
     RECT  15.12 21.546 15.431 21.924 ;
     RECT  15.12 29.916 15.431 39.582 ;
     RECT  15.12 82.836 15.431 83.484 ;
     RECT  15.12 5.886 15.503 20.754 ;
     RECT  15.12 3.348 15.683 3.366 ;
     RECT  15.431 29.916 15.899 39.474 ;
     RECT  15.12 22.788 15.935 27.594 ;
     RECT  15.12 47.862 15.935 58.644 ;
     RECT  15.503 5.886 15.971 14.904 ;
     RECT  15.935 22.788 15.971 27.126 ;
     RECT  15.899 29.916 15.971 39.204 ;
     RECT  15.12 42.066 15.971 45.288 ;
     RECT  15.935 47.862 15.971 52.434 ;
     RECT  15.935 53.226 15.971 58.644 ;
     RECT  15.12 59.814 15.971 69.714 ;
     RECT  15.12 73.206 15.971 81.864 ;
     RECT  15.12 4.266 16.007 4.824 ;
     RECT  15.971 73.206 16.007 76.266 ;
     RECT  15.971 61.74 16.079 69.714 ;
     RECT  15.12 84.888 16.079 94.464 ;
     RECT  15.971 22.788 16.439 27.054 ;
     RECT  15.971 33.282 16.439 39.204 ;
     RECT  16.079 62.046 16.439 69.714 ;
     RECT  15.503 15.876 16.475 20.754 ;
     RECT  16.439 22.788 16.475 25.704 ;
     RECT  15.971 42.066 16.475 45.144 ;
     RECT  15.971 47.862 16.475 51.624 ;
     RECT  15.971 53.226 16.475 57.294 ;
     RECT  16.439 67.806 16.475 69.714 ;
     RECT  15.971 77.058 16.475 81.864 ;
     RECT  16.079 87.156 16.475 94.464 ;
     RECT  15.971 5.886 16.511 13.824 ;
     RECT  16.475 15.876 16.511 18.684 ;
     RECT  16.475 19.746 16.511 20.754 ;
     RECT  16.475 22.788 16.511 23.814 ;
     RECT  16.475 24.606 16.511 25.164 ;
     RECT  16.439 26.496 16.511 27.054 ;
     RECT  16.439 33.282 16.511 38.304 ;
     RECT  16.475 44.046 16.511 44.874 ;
     RECT  15.12 46.08 16.511 46.494 ;
     RECT  16.475 47.862 16.511 50.274 ;
     RECT  16.475 51.066 16.511 51.624 ;
     RECT  16.475 53.226 16.511 57.024 ;
     RECT  15.971 58.086 16.511 58.104 ;
     RECT  16.439 62.046 16.511 67.014 ;
     RECT  16.475 68.076 16.511 69.714 ;
     RECT  16.007 73.206 16.511 76.104 ;
     RECT  16.475 77.058 16.511 79.704 ;
     RECT  16.475 80.676 16.511 81.864 ;
     RECT  16.475 89.136 16.511 90.774 ;
     RECT  16.475 91.566 16.511 91.926 ;
     RECT  16.475 92.988 16.511 94.464 ;
     RECT  16.007 4.734 16.547 4.824 ;
     RECT  16.511 5.886 16.547 9.234 ;
     RECT  16.511 15.876 16.547 17.64 ;
     RECT  16.511 22.788 16.547 22.806 ;
     RECT  16.511 34.056 16.547 34.524 ;
     RECT  16.511 36.558 16.547 37.044 ;
     RECT  15.12 40.914 16.547 40.932 ;
     RECT  16.475 42.066 16.547 43.254 ;
     RECT  16.511 56.034 16.547 56.664 ;
     RECT  16.511 65.826 16.547 65.844 ;
     RECT  16.511 68.256 16.547 69.714 ;
     RECT  15.12 70.506 16.547 71.874 ;
     RECT  16.079 84.888 16.547 86.22 ;
     RECT  16.475 87.156 16.547 88.344 ;
     RECT  15.431 21.546 16.583 21.564 ;
     RECT  16.511 53.226 16.583 55.206 ;
     RECT  16.547 71.496 16.583 71.874 ;
     RECT  16.547 4.734 16.619 4.752 ;
     RECT  16.583 53.496 16.619 55.206 ;
     RECT  15.971 59.814 16.619 60.876 ;
     RECT  16.583 71.856 16.619 71.874 ;
     RECT  16.547 84.888 16.619 85.374 ;
     RECT  16.619 59.814 16.655 60.57 ;
     RECT  16.619 84.888 16.655 84.906 ;
     RECT  16.511 73.206 16.727 74.646 ;
     RECT  15.971 29.916 16.987 32.49 ;
     RECT  16.987 29.916 17.015 33.066 ;
     RECT  16.511 11.826 17.051 13.824 ;
     RECT  17.015 32.472 17.051 33.066 ;
     RECT  16.547 70.506 17.051 70.524 ;
     RECT  17.051 13.374 17.087 13.824 ;
     RECT  17.015 29.916 17.087 31.374 ;
     RECT  17.051 32.931 17.087 33.066 ;
     RECT  16.619 53.496 17.087 55.044 ;
     RECT  16.547 9.171 17.123 9.234 ;
     RECT  16.511 10.368 17.123 10.656 ;
     RECT  17.051 11.826 17.123 12.618 ;
     RECT  16.511 20.124 17.123 20.754 ;
     RECT  17.087 30.996 17.123 31.374 ;
     RECT  16.439 39.096 17.123 39.204 ;
     RECT  16.511 46.08 17.123 46.134 ;
     RECT  17.087 53.496 17.123 53.964 ;
     RECT  16.547 69.264 17.123 69.714 ;
     RECT  16.511 93.906 17.123 94.464 ;
     RECT  16.547 5.886 17.159 8.424 ;
     RECT  17.123 10.476 17.159 10.656 ;
     RECT  17.087 13.806 17.159 13.824 ;
     RECT  17.123 30.996 17.159 31.014 ;
     RECT  17.087 32.931 17.159 32.994 ;
     RECT  16.511 38.286 17.159 38.304 ;
     RECT  17.123 46.116 17.159 46.134 ;
     RECT  15.971 52.416 17.159 52.434 ;
     RECT  17.087 54.846 17.159 55.044 ;
     RECT  17.123 69.264 17.159 69.282 ;
     RECT  16.727 73.512 17.159 74.646 ;
     RECT  16.511 75.546 17.159 75.879 ;
     RECT  16.511 77.058 17.159 77.922 ;
     RECT  16.511 81.846 17.159 81.864 ;
     RECT  17.059 82.611 17.159 82.629 ;
     RECT  15.431 83.466 17.159 83.484 ;
     RECT  16.547 87.426 17.159 88.344 ;
     RECT  16.511 91.638 17.159 91.926 ;
     RECT  16.511 92.988 17.159 93.006 ;
     RECT  17.159 6.624 17.195 7.956 ;
     RECT  17.159 10.476 17.195 10.494 ;
     RECT  17.123 11.826 17.195 11.844 ;
     RECT  15.971 14.886 17.195 14.904 ;
     RECT  16.547 15.876 17.195 16.524 ;
     RECT  17.123 20.556 17.195 20.754 ;
     RECT  16.511 27.036 17.195 27.054 ;
     RECT  17.087 29.916 17.195 29.934 ;
     RECT  16.547 34.056 17.195 34.074 ;
     RECT  16.547 37.026 17.195 37.044 ;
     RECT  17.123 39.186 17.195 39.204 ;
     RECT  16.547 42.066 17.195 42.084 ;
     RECT  16.547 43.236 17.195 43.254 ;
     RECT  16.511 44.766 17.195 44.784 ;
     RECT  16.511 47.862 17.195 47.88 ;
     RECT  16.511 49.554 17.195 49.572 ;
     RECT  16.511 51.516 17.195 51.534 ;
     RECT  17.123 53.946 17.195 53.964 ;
     RECT  17.159 55.026 17.195 55.044 ;
     RECT  16.655 59.814 17.195 59.832 ;
     RECT  16.511 62.046 17.195 62.694 ;
     RECT  16.547 68.256 17.195 68.274 ;
     RECT  17.159 73.926 17.195 74.646 ;
     RECT  17.159 77.904 17.195 77.922 ;
     RECT  16.511 80.676 17.195 80.694 ;
     RECT  17.159 87.858 17.195 88.344 ;
     RECT  17.159 91.908 17.195 91.926 ;
     RECT  17.123 93.906 17.195 93.924 ;
     RECT  17.195 6.624 17.267 6.642 ;
     RECT  17.123 9.171 17.267 9.189 ;
     RECT  16.547 17.622 17.267 17.64 ;
     RECT  17.195 20.736 17.267 20.754 ;
     RECT  15.12 29.034 17.267 29.052 ;
     RECT  17.159 32.976 17.267 32.994 ;
     RECT  17.195 74.628 17.267 74.646 ;
     RECT  17.159 75.861 17.267 75.879 ;
     RECT  16.547 86.202 17.267 86.22 ;
     RECT  16.511 89.712 17.267 89.73 ;
    LAYER M3 ;
     RECT  13.536 2.101 13.554 2.143 ;
     RECT  11.628 2.101 11.646 2.227 ;
     RECT  4.176 1.723 4.194 2.263 ;
     RECT  11.628 2.227 12.366 2.263 ;
     RECT  13.215 2.143 13.554 2.263 ;
     RECT  11.628 2.263 13.554 2.371 ;
     RECT  2.415 2.143 2.505 2.413 ;
     RECT  7.815 2.143 7.905 2.413 ;
     RECT  6.84 2.371 6.858 2.461 ;
     RECT  11.628 2.371 14.742 2.461 ;
     RECT  2.415 2.413 2.697 2.569 ;
     RECT  4.176 2.263 4.59 2.569 ;
     RECT  2.415 2.569 4.59 2.605 ;
     RECT  7.815 2.413 8.097 2.605 ;
     RECT  9.108 2.497 9.162 2.605 ;
     RECT  2.415 2.605 5.022 2.641 ;
     RECT  11.088 2.461 14.742 2.641 ;
     RECT  11.088 2.641 14.958 2.731 ;
     RECT  2.415 2.641 5.202 2.767 ;
     RECT  6.12 2.461 6.858 2.767 ;
     RECT  7.815 2.605 9.162 2.767 ;
     RECT  10.26 2.731 14.958 2.839 ;
     RECT  10.008 2.839 14.958 2.911 ;
     RECT  9.972 2.911 14.958 3.037 ;
     RECT  9.9 3.037 14.958 3.181 ;
     RECT  9.9 3.181 14.994 3.343 ;
     RECT  2.415 2.767 9.162 3.371 ;
     RECT  5.4 3.371 9.162 3.541 ;
     RECT  9.9 3.343 15.678 3.541 ;
     RECT  0.504 3.613 0.522 3.685 ;
     RECT  2.415 3.371 4.662 3.955 ;
     RECT  5.4 3.541 15.678 4.109 ;
     RECT  2.34 3.955 4.662 4.225 ;
     RECT  11.196 4.109 15.678 4.261 ;
     RECT  2.304 4.225 4.662 4.387 ;
     RECT  5.4 4.109 10.242 4.387 ;
     RECT  0.504 3.685 0.558 4.495 ;
     RECT  0.216 4.495 0.558 4.651 ;
     RECT  11.196 4.261 16.002 4.729 ;
     RECT  0.144 4.651 0.558 4.927 ;
     RECT  2.304 4.387 10.242 5.027 ;
     RECT  2.34 5.027 10.242 5.161 ;
     RECT  11.196 4.729 16.614 5.161 ;
     RECT  0.108 4.927 0.558 5.357 ;
     RECT  2.34 5.161 16.614 5.459 ;
     RECT  2.34 5.459 10.35 5.639 ;
     RECT  0.108 5.357 0.486 5.741 ;
     RECT  2.34 5.639 9.594 5.803 ;
     RECT  11.16 5.459 16.614 5.881 ;
     RECT  2.304 5.803 9.594 5.899 ;
     RECT  0.144 5.741 0.486 6.079 ;
     RECT  10.332 5.639 10.35 6.349 ;
     RECT  11.16 5.881 17.154 6.349 ;
     RECT  2.268 5.899 9.594 6.539 ;
     RECT  2.304 6.539 9.594 6.583 ;
     RECT  10.332 6.349 17.154 6.583 ;
     RECT  2.304 6.583 17.154 6.619 ;
     RECT  0.144 6.079 0.558 6.667 ;
     RECT  2.304 6.619 17.262 6.845 ;
     RECT  0.108 6.667 0.558 6.917 ;
     RECT  0.144 6.917 0.558 6.989 ;
     RECT  2.304 6.845 6.966 7.531 ;
     RECT  7.704 6.845 17.262 7.565 ;
     RECT  2.268 7.531 6.966 7.655 ;
     RECT  2.304 7.655 6.966 7.663 ;
     RECT  7.704 7.565 15.03 7.663 ;
     RECT  2.304 7.663 15.03 7.889 ;
     RECT  0.144 6.989 0.162 8.107 ;
     RECT  1.152 8.251 1.17 8.347 ;
     RECT  15.984 7.565 17.262 8.395 ;
     RECT  1.152 8.347 1.278 8.477 ;
     RECT  0.144 8.107 0.342 8.587 ;
     RECT  2.304 7.889 10.17 8.671 ;
     RECT  10.944 7.889 15.03 8.671 ;
     RECT  0.144 8.587 0.45 8.765 ;
     RECT  0.144 8.765 0.378 8.813 ;
     RECT  2.304 8.671 15.03 8.851 ;
     RECT  15.948 8.395 17.262 8.851 ;
     RECT  2.304 8.851 17.262 9.194 ;
     RECT  2.304 9.194 17.19 9.485 ;
     RECT  0.144 8.813 0.342 9.739 ;
     RECT  0.108 9.739 0.342 10.157 ;
     RECT  2.304 9.485 14.778 10.219 ;
     RECT  2.268 10.219 14.778 10.291 ;
     RECT  2.268 10.291 14.85 10.315 ;
     RECT  15.948 9.485 17.19 10.315 ;
     RECT  2.268 10.315 17.19 10.427 ;
     RECT  2.268 10.427 14.922 10.697 ;
     RECT  2.268 10.697 14.85 10.931 ;
     RECT  15.948 10.427 17.19 11.179 ;
     RECT  2.304 10.931 14.85 11.201 ;
     RECT  15.912 11.179 17.19 11.275 ;
     RECT  7.632 11.201 14.85 11.443 ;
     RECT  15.876 11.275 17.19 11.443 ;
     RECT  7.632 11.443 17.19 11.501 ;
     RECT  2.304 11.201 3.582 11.975 ;
     RECT  0.108 10.157 0.198 12.047 ;
     RECT  4.32 11.201 6.894 12.055 ;
     RECT  7.632 11.501 14.922 12.055 ;
     RECT  2.34 11.975 3.582 12.091 ;
     RECT  4.32 12.055 14.922 12.091 ;
     RECT  15.876 11.501 17.19 12.235 ;
     RECT  0.18 12.047 0.198 12.389 ;
     RECT  15.84 12.235 17.19 12.479 ;
     RECT  2.34 12.091 14.922 12.793 ;
     RECT  15.84 12.479 15.966 12.793 ;
     RECT  2.34 12.793 15.966 12.845 ;
     RECT  2.34 12.845 14.994 13.163 ;
     RECT  9.18 13.163 14.994 13.559 ;
     RECT  2.34 13.163 8.406 13.579 ;
     RECT  16.992 12.479 17.19 13.703 ;
     RECT  17.136 13.703 17.19 13.829 ;
     RECT  9.18 13.559 14.886 13.865 ;
     RECT  9.18 13.865 14.814 13.909 ;
     RECT  15.84 12.845 15.966 13.937 ;
     RECT  15.876 13.937 15.966 14.009 ;
     RECT  2.304 13.579 8.406 14.099 ;
     RECT  0.144 13.963 0.162 14.141 ;
     RECT  2.304 14.099 8.262 14.155 ;
     RECT  15.948 14.009 15.966 14.243 ;
     RECT  2.196 14.155 8.262 14.513 ;
     RECT  2.304 14.513 8.262 14.549 ;
     RECT  9.144 13.909 14.814 14.639 ;
     RECT  17.172 13.829 17.19 14.909 ;
     RECT  9.144 14.639 14.778 15.025 ;
     RECT  0.288 14.539 0.306 15.115 ;
     RECT  0.288 15.115 0.342 15.211 ;
     RECT  0.108 15.211 0.342 15.245 ;
     RECT  2.304 14.549 2.934 15.331 ;
     RECT  3.708 14.549 8.262 15.421 ;
     RECT  9.072 15.025 14.778 15.421 ;
     RECT  3.708 15.421 14.778 15.493 ;
     RECT  2.304 15.331 2.97 15.529 ;
     RECT  3.708 15.493 15.498 15.529 ;
     RECT  17.172 15.871 17.19 16.141 ;
     RECT  2.304 15.529 15.498 16.231 ;
     RECT  16.488 16.141 17.19 16.231 ;
     RECT  0.108 15.245 0.198 16.267 ;
     RECT  2.304 16.231 17.19 16.685 ;
     RECT  2.304 16.685 16.542 16.835 ;
     RECT  2.34 16.835 16.542 17.549 ;
     RECT  15.912 17.549 16.542 17.608 ;
     RECT  15.912 17.608 17.19 17.617 ;
     RECT  15.912 17.617 17.262 17.645 ;
     RECT  15.912 17.645 16.506 18.059 ;
     RECT  0.108 16.267 0.234 18.455 ;
     RECT  15.948 18.059 16.506 18.563 ;
     RECT  16.416 18.563 16.506 18.571 ;
     RECT  17.244 17.645 17.262 18.571 ;
     RECT  2.34 17.549 14.922 18.811 ;
     RECT  2.304 18.811 14.922 18.859 ;
     RECT  16.416 18.571 17.262 18.869 ;
     RECT  2.304 18.859 15.39 18.995 ;
     RECT  0.108 18.455 0.198 19.139 ;
     RECT  16.452 18.869 17.262 19.229 ;
     RECT  0.108 19.139 0.126 19.265 ;
     RECT  2.415 18.995 15.39 19.301 ;
     RECT  6.084 19.301 15.39 19.571 ;
     RECT  16.488 19.229 17.262 19.769 ;
     RECT  2.415 19.301 5.274 19.805 ;
     RECT  2.415 19.805 4.194 20.039 ;
     RECT  5.112 19.805 5.274 20.039 ;
     RECT  6.084 19.571 15.354 20.075 ;
     RECT  17.1 19.769 17.262 20.147 ;
     RECT  5.112 20.039 5.13 20.189 ;
     RECT  6.084 20.075 9.738 20.191 ;
     RECT  6.048 20.191 9.738 20.309 ;
     RECT  0.108 20.395 0.126 20.425 ;
     RECT  0.108 20.425 0.558 20.525 ;
     RECT  17.172 20.147 17.262 20.579 ;
     RECT  0.54 20.525 0.558 20.621 ;
     RECT  2.415 20.039 3.474 20.683 ;
     RECT  10.476 20.075 15.354 20.687 ;
     RECT  17.244 20.579 17.262 20.759 ;
     RECT  2.304 20.683 3.474 20.821 ;
     RECT  6.516 20.309 9.738 21.001 ;
     RECT  10.476 20.687 14.994 21.001 ;
     RECT  5.544 20.821 5.562 21.104 ;
     RECT  6.516 21.001 14.994 21.119 ;
     RECT  2.304 20.821 3.618 21.127 ;
     RECT  6.516 21.119 14.814 21.127 ;
     RECT  2.304 21.127 3.834 21.199 ;
     RECT  2.304 21.199 4.41 21.259 ;
     RECT  5.292 21.104 5.562 21.259 ;
     RECT  2.304 21.259 5.562 21.271 ;
     RECT  2.304 21.271 5.598 21.397 ;
     RECT  6.336 21.127 14.814 21.397 ;
     RECT  0.144 21.403 0.162 21.505 ;
     RECT  0.144 21.505 0.558 21.581 ;
     RECT  2.304 21.397 14.814 21.643 ;
     RECT  2.268 21.643 14.814 21.901 ;
     RECT  2.268 21.901 15.426 22.109 ;
     RECT  0.54 21.581 0.558 22.157 ;
     RECT  2.268 22.109 9.234 22.235 ;
     RECT  16.56 21.541 16.578 22.783 ;
     RECT  2.268 22.235 9.198 23.045 ;
     RECT  2.304 23.045 9.198 23.125 ;
     RECT  10.188 22.109 15.426 23.125 ;
     RECT  0.144 22.555 0.162 23.179 ;
     RECT  16.524 22.783 16.578 23.179 ;
     RECT  0.144 23.179 0.342 23.275 ;
     RECT  16.488 23.179 16.578 23.275 ;
     RECT  2.304 23.125 15.426 23.279 ;
     RECT  0.108 23.275 0.342 23.309 ;
     RECT  2.304 23.279 4.302 23.315 ;
     RECT  5.04 23.279 15.426 23.371 ;
     RECT  16.452 23.275 16.578 23.371 ;
     RECT  5.04 23.371 16.578 23.549 ;
     RECT  5.04 23.549 10.314 23.729 ;
     RECT  11.088 23.549 16.578 23.789 ;
     RECT  5.04 23.729 10.134 23.819 ;
     RECT  11.088 23.789 16.506 24.331 ;
     RECT  5.04 23.819 9.774 24.475 ;
     RECT  10.872 24.331 16.506 24.475 ;
     RECT  2.304 23.315 4.158 24.511 ;
     RECT  4.932 24.475 9.774 24.511 ;
     RECT  10.656 24.475 16.506 24.557 ;
     RECT  10.656 24.557 15.462 24.745 ;
     RECT  10.584 24.745 15.462 24.749 ;
     RECT  2.304 24.511 9.774 24.781 ;
     RECT  16.452 24.557 16.506 24.811 ;
     RECT  2.304 24.781 9.81 24.899 ;
     RECT  10.584 24.749 15.39 24.899 ;
     RECT  2.304 24.899 6.786 24.935 ;
     RECT  11.736 24.899 15.39 25.241 ;
     RECT  11.736 25.241 14.922 25.439 ;
     RECT  16.452 24.811 17.19 25.483 ;
     RECT  16.416 25.483 17.19 25.579 ;
     RECT  2.34 24.935 6.786 25.681 ;
     RECT  7.56 24.899 9.81 25.681 ;
     RECT  10.584 24.899 10.602 25.681 ;
     RECT  11.736 25.439 14.814 25.681 ;
     RECT  2.34 25.681 14.814 26.015 ;
     RECT  15.876 25.579 17.19 26.051 ;
     RECT  2.415 26.015 14.814 26.249 ;
     RECT  0.108 23.309 0.126 26.285 ;
     RECT  8.964 26.249 14.814 26.429 ;
     RECT  2.415 26.249 4.734 26.519 ;
     RECT  5.508 26.249 8.154 26.519 ;
     RECT  9.756 26.429 14.814 26.519 ;
     RECT  11.304 26.519 14.814 26.555 ;
     RECT  2.415 26.519 3.834 26.669 ;
     RECT  6.084 26.519 6.21 26.669 ;
     RECT  2.415 26.669 3.006 26.789 ;
     RECT  3.816 26.669 3.834 26.789 ;
     RECT  15.912 26.051 17.19 26.789 ;
     RECT  2.415 26.789 2.862 26.825 ;
     RECT  17.172 26.789 17.19 27.059 ;
     RECT  15.912 26.789 15.966 27.131 ;
     RECT  8.964 26.429 8.982 27.211 ;
     RECT  9.756 26.519 10.458 27.211 ;
     RECT  11.34 26.555 14.814 27.211 ;
     RECT  7.128 26.519 8.154 27.301 ;
     RECT  8.964 27.211 10.458 27.301 ;
     RECT  8.964 27.301 10.566 27.337 ;
     RECT  11.34 27.211 14.922 27.337 ;
     RECT  8.964 27.337 14.922 27.401 ;
     RECT  4.644 26.519 4.662 27.409 ;
     RECT  6.732 27.301 8.226 27.409 ;
     RECT  8.964 27.401 9.918 27.409 ;
     RECT  4.644 27.409 5.166 27.481 ;
     RECT  3.888 27.409 3.906 27.571 ;
     RECT  15.912 27.131 15.93 27.599 ;
     RECT  2.415 26.825 2.697 27.679 ;
     RECT  4.644 27.481 5.742 27.715 ;
     RECT  10.692 27.401 14.922 27.715 ;
     RECT  2.415 27.679 2.862 27.751 ;
     RECT  3.636 27.571 3.906 27.751 ;
     RECT  4.644 27.715 5.994 27.751 ;
     RECT  6.732 27.409 9.918 27.751 ;
     RECT  10.692 27.715 14.994 27.869 ;
     RECT  2.415 27.751 9.918 28.123 ;
     RECT  10.692 27.869 14.706 28.123 ;
     RECT  2.415 28.123 14.706 28.183 ;
     RECT  2.376 28.183 14.706 28.255 ;
     RECT  0.036 27.751 0.054 28.381 ;
     RECT  2.34 28.255 14.706 28.409 ;
     RECT  0.036 28.381 0.45 28.453 ;
     RECT  7.056 28.409 14.706 28.541 ;
     RECT  0.036 28.453 0.486 28.795 ;
     RECT  7.092 28.541 14.706 28.831 ;
     RECT  7.092 28.831 14.85 28.957 ;
     RECT  7.092 28.957 14.886 29.027 ;
     RECT  0.036 28.795 0.522 29.569 ;
     RECT  7.308 29.027 14.886 29.569 ;
     RECT  2.34 28.409 6.318 29.605 ;
     RECT  7.308 29.569 14.958 29.605 ;
     RECT  2.34 29.605 6.498 29.641 ;
     RECT  2.304 29.641 6.498 29.741 ;
     RECT  2.34 29.741 6.498 29.803 ;
     RECT  7.308 29.605 14.994 29.803 ;
     RECT  2.34 29.803 14.994 29.903 ;
     RECT  17.244 29.029 17.262 29.911 ;
     RECT  0.036 29.569 0.558 30.317 ;
     RECT  17.172 29.911 17.262 30.343 ;
     RECT  2.34 29.903 9.198 30.509 ;
     RECT  9.936 29.903 14.994 30.721 ;
     RECT  0.036 30.317 0.486 30.794 ;
     RECT  0.108 30.794 0.486 30.797 ;
     RECT  2.376 30.509 9.198 30.811 ;
     RECT  9.936 30.721 15.03 30.811 ;
     RECT  0.144 30.797 0.486 31.117 ;
     RECT  2.376 30.811 15.03 31.243 ;
     RECT  17.064 30.343 17.262 31.261 ;
     RECT  2.304 31.243 15.03 31.289 ;
     RECT  0.144 31.117 0.522 31.387 ;
     RECT  16.632 31.261 17.262 31.495 ;
     RECT  0.144 31.387 0.558 31.661 ;
     RECT  16.452 31.495 17.262 31.693 ;
     RECT  2.415 31.289 15.03 32.011 ;
     RECT  0.396 31.661 0.558 32.467 ;
     RECT  0.144 32.467 0.558 32.683 ;
     RECT  15.984 31.693 17.262 32.779 ;
     RECT  15.948 32.779 17.262 32.837 ;
     RECT  0.108 32.683 0.558 32.971 ;
     RECT  16.488 32.837 17.262 32.999 ;
     RECT  16.488 32.999 17.19 33.008 ;
     RECT  0.108 32.971 0.594 33.071 ;
     RECT  2.304 32.011 15.03 33.071 ;
     RECT  0.108 33.071 0.558 33.293 ;
     RECT  16.488 33.008 17.154 33.781 ;
     RECT  2.304 33.071 14.958 33.889 ;
     RECT  15.984 33.781 17.154 33.889 ;
     RECT  2.304 33.889 17.154 34.051 ;
     RECT  0.54 33.293 0.558 34.219 ;
     RECT  2.304 34.051 17.19 34.253 ;
     RECT  0.144 34.219 0.558 34.349 ;
     RECT  0.144 34.349 0.162 34.603 ;
     RECT  2.304 34.253 16.542 34.987 ;
     RECT  0.108 34.603 0.162 35.083 ;
     RECT  2.268 34.987 16.542 35.195 ;
     RECT  2.304 35.195 16.542 35.213 ;
     RECT  0.108 35.083 0.342 35.309 ;
     RECT  2.304 35.213 16.506 36.139 ;
     RECT  2.304 36.139 16.542 36.815 ;
     RECT  2.34 36.815 16.542 37.021 ;
     RECT  2.34 37.021 17.19 37.085 ;
     RECT  0.108 35.309 0.27 37.499 ;
     RECT  2.376 37.085 17.19 37.625 ;
     RECT  0.144 37.499 0.27 38.543 ;
     RECT  0.144 38.543 0.162 38.579 ;
     RECT  2.415 37.625 17.19 38.849 ;
     RECT  2.415 38.849 15.966 39.047 ;
     RECT  2.415 39.047 15.894 39.091 ;
     RECT  17.1 38.849 17.19 39.119 ;
     RECT  17.172 39.119 17.19 39.209 ;
     RECT  2.376 39.091 15.894 39.245 ;
     RECT  9.036 39.245 15.894 39.479 ;
     RECT  9.036 39.479 15.426 39.587 ;
     RECT  2.376 39.245 8.19 39.883 ;
     RECT  2.304 39.883 8.19 40.171 ;
     RECT  9.036 39.587 14.922 40.171 ;
     RECT  2.304 40.171 14.922 40.559 ;
     RECT  0.324 41.035 0.342 41.131 ;
     RECT  0.108 41.131 0.342 41.261 ;
     RECT  0.108 41.261 0.234 41.501 ;
     RECT  2.304 40.559 14.886 41.521 ;
     RECT  2.304 41.521 14.994 41.611 ;
     RECT  2.268 41.611 14.994 41.648 ;
     RECT  16.524 40.909 16.542 42.061 ;
     RECT  2.304 41.648 14.994 42.215 ;
     RECT  2.34 42.215 14.994 42.323 ;
     RECT  16.524 42.061 17.19 42.413 ;
     RECT  16.524 42.413 16.542 42.475 ;
     RECT  16.488 42.475 16.542 42.667 ;
     RECT  0.108 41.501 0.162 42.701 ;
     RECT  16.452 42.667 16.542 42.871 ;
     RECT  0.108 42.701 0.126 42.899 ;
     RECT  15.984 42.871 16.542 42.955 ;
     RECT  15.948 42.955 16.542 43.051 ;
     RECT  2.34 42.323 9.126 43.069 ;
     RECT  9.9 42.323 14.994 43.069 ;
     RECT  2.34 43.069 14.994 43.141 ;
     RECT  15.912 43.051 16.542 43.141 ;
     RECT  2.34 43.141 16.542 43.231 ;
     RECT  2.34 43.231 17.19 43.295 ;
     RECT  2.376 43.295 17.19 43.469 ;
     RECT  2.376 43.469 16.506 43.853 ;
     RECT  2.376 43.853 14.958 44.105 ;
     RECT  15.84 43.853 16.506 44.237 ;
     RECT  2.415 44.105 14.958 44.339 ;
     RECT  15.876 44.237 16.506 44.395 ;
     RECT  5.004 44.339 14.958 44.447 ;
     RECT  2.415 44.339 4.194 44.609 ;
     RECT  6.624 44.447 14.958 44.621 ;
     RECT  5.652 44.447 5.67 44.645 ;
     RECT  15.876 44.395 17.19 44.681 ;
     RECT  6.624 44.621 14.922 44.753 ;
     RECT  3.96 44.609 4.194 44.789 ;
     RECT  15.948 44.681 17.19 44.789 ;
     RECT  3.96 44.789 4.086 44.879 ;
     RECT  6.732 44.753 14.922 44.879 ;
     RECT  6.732 44.879 14.778 45.005 ;
     RECT  4.068 44.879 4.086 45.149 ;
     RECT  9 45.005 14.778 45.257 ;
     RECT  15.948 44.789 17.154 45.293 ;
     RECT  5.796 45.229 5.814 45.301 ;
     RECT  9 45.257 9.342 45.419 ;
     RECT  5.796 45.301 5.85 45.427 ;
     RECT  5.292 45.427 5.85 45.571 ;
     RECT  6.732 45.005 8.154 45.571 ;
     RECT  5.292 45.571 8.154 45.661 ;
     RECT  2.415 44.609 3.15 45.805 ;
     RECT  9 45.419 9.198 45.841 ;
     RECT  10.116 45.257 14.778 45.841 ;
     RECT  4.464 45.661 8.154 45.931 ;
     RECT  8.892 45.841 9.198 45.931 ;
     RECT  2.304 45.805 3.15 46.027 ;
     RECT  4.464 45.931 9.198 46.069 ;
     RECT  2.304 46.027 3.33 46.111 ;
     RECT  4.356 46.069 9.198 46.111 ;
     RECT  16.488 45.293 17.154 46.139 ;
     RECT  10.116 45.841 14.994 46.229 ;
     RECT  2.304 46.111 9.198 46.237 ;
     RECT  10.116 46.229 14.814 46.237 ;
     RECT  1.152 46.267 1.17 46.411 ;
     RECT  16.488 46.139 16.506 46.499 ;
     RECT  1.152 46.411 1.386 46.541 ;
     RECT  0.108 46.075 0.126 46.543 ;
     RECT  1.152 46.541 1.17 46.637 ;
     RECT  0.108 46.543 0.198 46.829 ;
     RECT  2.304 46.237 14.814 47.039 ;
     RECT  9.468 47.039 14.814 47.191 ;
     RECT  0.18 46.829 0.198 47.563 ;
     RECT  0.18 47.563 0.342 47.659 ;
     RECT  0.108 47.659 0.342 47.759 ;
     RECT  9.468 47.191 14.994 47.899 ;
     RECT  2.304 47.039 8.37 48.001 ;
     RECT  9.36 47.899 14.994 48.001 ;
     RECT  0.18 47.759 0.342 48.173 ;
     RECT  15.984 48.091 16.002 48.271 ;
     RECT  17.172 47.857 17.19 48.271 ;
     RECT  15.984 48.271 17.19 48.365 ;
     RECT  0.36 48.523 0.45 48.701 ;
     RECT  2.304 48.001 14.994 48.739 ;
     RECT  15.984 48.365 16.506 48.739 ;
     RECT  0.36 48.701 0.378 48.749 ;
     RECT  2.304 48.739 16.506 48.941 ;
     RECT  15.948 48.941 16.506 49.549 ;
     RECT  15.948 49.549 17.19 49.709 ;
     RECT  2.304 48.941 14.994 49.771 ;
     RECT  15.948 49.709 16.506 49.771 ;
     RECT  2.304 49.771 16.506 49.847 ;
     RECT  2.304 49.847 14.994 49.901 ;
     RECT  2.304 49.901 14.922 50.189 ;
     RECT  2.304 50.189 5.562 50.549 ;
     RECT  6.48 50.189 14.922 50.549 ;
     RECT  2.304 50.549 5.382 50.585 ;
     RECT  6.84 50.549 14.922 50.731 ;
     RECT  15.876 49.847 16.506 50.731 ;
     RECT  6.84 50.731 16.506 50.891 ;
     RECT  7.632 50.891 16.506 51.115 ;
     RECT  7.632 51.115 17.19 51.161 ;
     RECT  2.415 50.585 5.382 51.233 ;
     RECT  2.415 51.233 5.31 51.359 ;
     RECT  7.632 51.161 8.766 51.359 ;
     RECT  7.632 51.359 8.586 51.395 ;
     RECT  9.504 51.161 17.19 51.539 ;
     RECT  9.504 51.539 16.506 51.629 ;
     RECT  6.768 51.307 6.786 51.781 ;
     RECT  7.632 51.395 8.154 51.781 ;
     RECT  9.504 51.629 15.966 51.899 ;
     RECT  3.42 51.359 5.31 52.051 ;
     RECT  6.768 51.781 8.154 52.051 ;
     RECT  9.504 51.899 15.93 52.079 ;
     RECT  9.504 52.079 14.814 52.169 ;
     RECT  9.504 52.169 14.778 52.213 ;
     RECT  3.42 52.051 8.154 52.321 ;
     RECT  9.432 52.213 14.778 52.349 ;
     RECT  3.42 52.321 8.406 52.447 ;
     RECT  9.432 52.349 14.67 52.447 ;
     RECT  2.415 51.359 2.697 52.459 ;
     RECT  3.42 52.447 14.67 52.459 ;
     RECT  15.912 52.079 15.93 52.709 ;
     RECT  0.504 52.519 0.522 52.717 ;
     RECT  0.108 52.717 0.522 52.825 ;
     RECT  0.108 52.825 0.558 52.987 ;
     RECT  17.136 52.411 17.154 53.221 ;
     RECT  2.415 52.459 14.67 53.401 ;
     RECT  2.415 53.401 14.886 53.519 ;
     RECT  2.415 53.519 8.262 53.555 ;
     RECT  9.18 53.519 14.886 53.563 ;
     RECT  9.18 53.563 14.994 53.699 ;
     RECT  9.612 53.699 14.994 53.789 ;
     RECT  2.415 53.555 8.19 53.825 ;
     RECT  2.415 53.825 4.014 53.905 ;
     RECT  16.56 53.221 17.154 53.941 ;
     RECT  4.932 53.825 8.19 54.301 ;
     RECT  9.612 53.789 9.63 54.445 ;
     RECT  4.932 54.301 8.622 54.481 ;
     RECT  9.36 54.445 9.63 54.481 ;
     RECT  16.56 53.941 17.19 54.481 ;
     RECT  2.304 53.905 4.014 54.679 ;
     RECT  4.932 54.481 9.63 54.715 ;
     RECT  10.476 53.789 14.994 54.715 ;
     RECT  4.932 54.715 14.994 54.893 ;
     RECT  2.304 54.679 4.158 54.913 ;
     RECT  4.932 54.893 14.85 54.913 ;
     RECT  15.984 54.481 17.19 54.913 ;
     RECT  15.948 54.913 17.19 55.181 ;
     RECT  16.488 55.181 17.19 55.469 ;
     RECT  16.488 55.469 17.154 55.661 ;
     RECT  2.304 54.913 14.85 55.679 ;
     RECT  2.304 55.679 4.806 55.751 ;
     RECT  0.036 52.987 0.558 55.823 ;
     RECT  5.58 55.679 14.85 55.823 ;
     RECT  16.488 55.661 17.082 55.915 ;
     RECT  9.72 55.823 14.85 55.985 ;
     RECT  16.452 55.915 17.082 56.011 ;
     RECT  15.876 56.011 17.082 56.621 ;
     RECT  2.304 55.751 4.698 56.641 ;
     RECT  5.58 55.823 8.982 56.641 ;
     RECT  15.876 56.621 16.542 56.669 ;
     RECT  9.72 55.985 14.742 56.767 ;
     RECT  2.304 56.641 8.982 56.803 ;
     RECT  9.72 56.767 14.778 56.803 ;
     RECT  2.304 56.803 14.778 57.064 ;
     RECT  15.876 56.669 16.506 57.064 ;
     RECT  2.304 57.064 16.506 57.101 ;
     RECT  0.072 55.823 0.558 57.254 ;
     RECT  0.144 57.254 0.558 57.293 ;
     RECT  2.304 57.101 14.922 57.479 ;
     RECT  3.708 57.479 14.922 57.569 ;
     RECT  0.468 57.293 0.558 57.581 ;
     RECT  3.708 57.569 9.81 57.605 ;
     RECT  9.792 57.605 9.81 57.677 ;
     RECT  5.58 57.605 8.874 57.713 ;
     RECT  2.304 57.479 2.826 57.875 ;
     RECT  0.54 57.581 0.558 57.965 ;
     RECT  15.912 57.101 16.506 58.109 ;
     RECT  2.34 57.875 2.826 58.225 ;
     RECT  3.708 57.605 4.77 58.351 ;
     RECT  5.58 57.713 8.838 58.351 ;
     RECT  10.656 57.569 14.922 58.351 ;
     RECT  2.34 58.225 2.934 58.363 ;
     RECT  3.708 58.351 8.838 58.363 ;
     RECT  15.912 58.109 15.966 58.379 ;
     RECT  10.584 58.351 14.922 58.423 ;
     RECT  10.44 58.423 14.922 58.531 ;
     RECT  2.34 58.363 8.838 58.621 ;
     RECT  9.684 58.531 9.702 58.621 ;
     RECT  15.948 58.379 15.966 58.649 ;
     RECT  2.34 58.621 9.702 58.765 ;
     RECT  10.44 58.531 14.958 58.765 ;
     RECT  2.34 58.765 14.958 58.891 ;
     RECT  2.304 58.891 14.958 59.027 ;
     RECT  2.34 59.027 14.958 59.072 ;
     RECT  0.216 58.495 0.234 59.083 ;
     RECT  2.34 59.072 9.594 59.189 ;
     RECT  10.368 59.072 14.958 59.189 ;
     RECT  0.216 59.083 0.342 59.197 ;
     RECT  0.18 59.197 0.342 59.233 ;
     RECT  0.108 59.233 0.342 59.405 ;
     RECT  0.108 59.405 0.234 59.789 ;
     RECT  0.108 59.789 0.162 59.885 ;
     RECT  2.34 59.189 9.558 59.947 ;
     RECT  2.304 59.947 9.558 60.151 ;
     RECT  10.404 59.189 14.958 60.151 ;
     RECT  0.144 59.885 0.162 60.173 ;
     RECT  17.172 59.809 17.19 60.313 ;
     RECT  2.304 60.151 14.958 60.619 ;
     RECT  0.252 60.523 0.342 60.653 ;
     RECT  0.252 60.653 0.27 61.003 ;
     RECT  2.304 60.619 15.462 61.393 ;
     RECT  16.524 60.313 17.19 61.393 ;
     RECT  2.304 61.393 17.19 61.483 ;
     RECT  0.144 61.003 0.27 61.579 ;
     RECT  0.144 61.579 0.342 61.709 ;
     RECT  2.268 61.483 17.19 61.925 ;
     RECT  2.268 61.925 5.526 61.963 ;
     RECT  0.144 61.709 0.162 62.059 ;
     RECT  6.3 61.925 17.19 62.381 ;
     RECT  2.124 61.963 5.526 62.671 ;
     RECT  6.3 62.381 14.994 62.671 ;
     RECT  0.108 62.059 0.162 63.019 ;
     RECT  1.152 62.971 1.17 63.149 ;
     RECT  2.124 62.671 14.994 63.307 ;
     RECT  0.108 63.019 0.234 63.403 ;
     RECT  0.108 63.403 0.342 63.419 ;
     RECT  1.728 63.307 14.994 63.883 ;
     RECT  15.768 62.381 17.19 63.883 ;
     RECT  1.728 63.883 17.19 63.959 ;
     RECT  1.728 63.959 14.922 64.075 ;
     RECT  0.144 63.419 0.342 64.093 ;
     RECT  0.144 64.093 0.378 64.171 ;
     RECT  0.108 64.171 0.378 64.201 ;
     RECT  1.368 64.075 14.922 64.201 ;
     RECT  15.804 63.959 17.19 64.301 ;
     RECT  0.108 64.201 14.922 64.319 ;
     RECT  0.108 64.319 5.598 64.355 ;
     RECT  6.624 64.319 14.922 64.463 ;
     RECT  6.696 64.463 14.922 65.011 ;
     RECT  15.804 64.301 16.506 65.011 ;
     RECT  6.696 65.011 16.506 65.069 ;
     RECT  0.108 64.355 5.49 65.245 ;
     RECT  0.108 65.245 5.706 65.281 ;
     RECT  6.696 65.069 14.886 65.281 ;
     RECT  0.108 65.281 14.886 65.471 ;
     RECT  15.768 65.069 16.506 65.707 ;
     RECT  15.768 65.707 16.542 65.849 ;
     RECT  15.768 65.849 16.506 66.085 ;
     RECT  15.408 66.085 16.506 66.125 ;
     RECT  0.108 65.471 14.598 66.217 ;
     RECT  0.108 66.217 14.994 66.389 ;
     RECT  0.108 66.389 14.922 66.479 ;
     RECT  15.768 66.125 16.506 66.623 ;
     RECT  15.84 66.623 16.506 66.667 ;
     RECT  9.036 66.479 14.922 67.019 ;
     RECT  0.108 66.479 6.894 67.261 ;
     RECT  7.704 66.479 8.097 67.261 ;
     RECT  9.036 67.019 14.85 67.289 ;
     RECT  0.108 67.261 8.097 67.297 ;
     RECT  9.036 67.289 14.814 67.297 ;
     RECT  15.84 66.667 17.19 67.433 ;
     RECT  15.912 67.433 17.19 68.279 ;
     RECT  15.912 68.279 17.154 68.369 ;
     RECT  0.108 67.297 14.814 68.381 ;
     RECT  16.524 68.369 17.154 68.711 ;
     RECT  9.864 68.381 14.814 68.791 ;
     RECT  0.108 68.381 9.054 68.981 ;
     RECT  9.864 68.791 14.994 69.017 ;
     RECT  0.828 68.981 9.054 69.187 ;
     RECT  9.864 69.017 14.922 69.187 ;
     RECT  17.028 68.711 17.154 69.287 ;
     RECT  0.828 69.187 14.922 69.323 ;
     RECT  0.828 69.323 0.846 69.359 ;
     RECT  1.98 69.323 14.922 69.449 ;
     RECT  1.98 69.449 14.85 69.485 ;
     RECT  17.028 69.287 17.118 69.719 ;
     RECT  2.415 69.485 14.85 69.755 ;
     RECT  2.415 69.755 5.418 69.989 ;
     RECT  7.704 69.755 14.814 69.989 ;
     RECT  3.924 69.989 4.23 70.061 ;
     RECT  17.028 69.719 17.046 70.529 ;
     RECT  4.212 70.061 4.23 70.807 ;
     RECT  6.3 69.755 6.966 70.807 ;
     RECT  7.704 69.989 9.27 70.807 ;
     RECT  6.156 70.807 9.27 70.915 ;
     RECT  10.008 69.989 14.814 70.915 ;
     RECT  5.328 70.915 5.346 70.951 ;
     RECT  6.156 70.915 14.814 70.951 ;
     RECT  5.328 70.951 14.958 70.973 ;
     RECT  2.415 69.989 2.697 71.113 ;
     RECT  3.456 71.077 3.474 71.113 ;
     RECT  4.212 70.807 4.554 71.113 ;
     RECT  2.415 71.113 4.554 71.275 ;
     RECT  16.524 71.221 16.542 71.491 ;
     RECT  0.324 71.371 0.342 71.617 ;
     RECT  0.18 71.617 0.342 71.689 ;
     RECT  2.304 71.275 4.554 71.725 ;
     RECT  5.364 70.973 14.958 71.725 ;
     RECT  2.304 71.725 14.958 71.752 ;
     RECT  16.524 71.491 16.578 71.851 ;
     RECT  0.108 71.689 0.342 71.981 ;
     RECT  2.268 71.752 14.958 72.031 ;
     RECT  0.18 71.981 0.342 72.193 ;
     RECT  2.268 72.031 15.03 72.365 ;
     RECT  2.304 72.365 15.03 72.527 ;
     RECT  0.18 72.193 0.558 72.557 ;
     RECT  0.18 72.557 0.522 72.653 ;
     RECT  0.18 72.653 0.342 72.763 ;
     RECT  2.304 72.527 8.298 72.833 ;
     RECT  9.072 72.527 15.03 72.931 ;
     RECT  16.524 71.851 16.614 73.201 ;
     RECT  0.144 72.763 0.342 73.325 ;
     RECT  6.228 72.833 8.298 73.345 ;
     RECT  9.072 72.931 15.066 73.345 ;
     RECT  2.304 72.833 5.418 73.381 ;
     RECT  16.524 73.201 16.722 73.507 ;
     RECT  2.268 73.381 5.418 73.651 ;
     RECT  6.228 73.345 15.066 73.651 ;
     RECT  16.524 73.507 17.154 73.771 ;
     RECT  0.324 73.325 0.342 73.901 ;
     RECT  16.524 73.771 17.19 74.011 ;
     RECT  2.268 73.651 15.066 74.039 ;
     RECT  2.268 74.039 8.298 74.045 ;
     RECT  2.268 74.045 8.262 74.111 ;
     RECT  2.268 74.111 8.154 74.417 ;
     RECT  15.984 74.011 17.19 74.623 ;
     RECT  15.984 74.623 17.262 74.635 ;
     RECT  9.144 74.039 15.066 74.821 ;
     RECT  15.948 74.635 17.262 74.821 ;
     RECT  2.304 74.417 8.154 75.191 ;
     RECT  9.144 74.821 17.262 75.235 ;
     RECT  9.036 75.235 17.262 75.437 ;
     RECT  4.572 75.191 8.154 75.469 ;
     RECT  9.036 75.437 14.778 75.541 ;
     RECT  15.948 75.437 17.262 75.884 ;
     RECT  4.572 75.469 8.19 75.901 ;
     RECT  8.964 75.541 14.778 75.901 ;
     RECT  4.572 75.901 14.778 75.929 ;
     RECT  2.304 75.191 3.762 76.045 ;
     RECT  2.304 76.045 3.834 76.081 ;
     RECT  4.572 75.929 5.238 76.081 ;
     RECT  15.948 75.884 17.19 76.109 ;
     RECT  15.948 76.109 16.074 76.205 ;
     RECT  2.304 76.081 5.238 76.235 ;
     RECT  6.012 75.929 14.778 76.351 ;
     RECT  15.948 76.205 16.002 76.397 ;
     RECT  15.948 76.397 15.966 76.459 ;
     RECT  6.012 76.351 14.922 76.469 ;
     RECT  15.912 76.459 15.966 76.651 ;
     RECT  6.012 76.469 14.742 76.775 ;
     RECT  6.624 76.775 14.742 76.847 ;
     RECT  2.415 76.235 5.238 76.855 ;
     RECT  2.415 76.855 5.814 76.883 ;
     RECT  15.876 76.651 15.966 76.919 ;
     RECT  2.415 76.883 4.842 77.279 ;
     RECT  6.624 76.847 8.514 77.279 ;
     RECT  17.136 76.109 17.19 77.359 ;
     RECT  0.504 77.323 0.522 77.395 ;
     RECT  9.252 76.847 14.742 77.431 ;
     RECT  6.732 77.279 8.514 77.593 ;
     RECT  9.252 77.431 14.85 77.593 ;
     RECT  5.616 76.883 5.814 77.701 ;
     RECT  6.732 77.593 14.85 77.701 ;
     RECT  15.984 77.359 17.19 77.701 ;
     RECT  4.068 77.279 4.842 77.827 ;
     RECT  5.616 77.701 5.958 77.827 ;
     RECT  6.732 77.701 17.19 77.927 ;
     RECT  0.432 77.395 0.522 77.935 ;
     RECT  4.068 77.827 5.958 78.133 ;
     RECT  6.732 77.927 16.506 78.133 ;
     RECT  2.415 77.279 2.97 78.169 ;
     RECT  2.304 78.169 3.006 78.241 ;
     RECT  4.068 78.133 16.506 78.241 ;
     RECT  0.108 77.935 0.522 78.601 ;
     RECT  2.304 78.241 16.506 78.935 ;
     RECT  0.108 78.601 0.558 79.003 ;
     RECT  2.415 78.935 16.506 79.051 ;
     RECT  0.108 79.003 0.63 79.079 ;
     RECT  2.415 79.051 17.19 79.079 ;
     RECT  0.108 79.079 0.558 79.088 ;
     RECT  2.415 79.079 8.514 79.169 ;
     RECT  0.108 79.088 0.522 79.181 ;
     RECT  0.108 79.181 0.162 79.373 ;
     RECT  0.144 79.373 0.162 79.469 ;
     RECT  2.415 79.169 8.478 79.583 ;
     RECT  9.252 79.079 17.19 79.619 ;
     RECT  5.328 79.583 8.478 79.709 ;
     RECT  9.252 79.619 15.426 79.709 ;
     RECT  2.415 79.583 4.518 79.819 ;
     RECT  2.304 79.819 4.518 79.861 ;
     RECT  2.268 79.861 4.518 79.949 ;
     RECT  16.38 79.619 17.19 80.395 ;
     RECT  2.304 79.949 4.518 80.401 ;
     RECT  2.304 80.401 4.59 80.491 ;
     RECT  5.328 79.709 8.37 80.491 ;
     RECT  2.304 80.491 8.37 80.563 ;
     RECT  9.288 79.709 15.426 80.563 ;
     RECT  0.324 80.491 0.342 80.587 ;
     RECT  16.344 80.395 17.19 80.699 ;
     RECT  2.304 80.563 15.426 80.779 ;
     RECT  16.344 80.699 17.154 80.789 ;
     RECT  2.268 80.779 15.426 80.825 ;
     RECT  0.216 80.587 0.342 80.869 ;
     RECT  0.108 80.869 0.342 81.005 ;
     RECT  2.304 80.825 15.426 81.059 ;
     RECT  16.416 80.789 17.154 81.059 ;
     RECT  16.488 81.059 17.154 81.329 ;
     RECT  0.144 81.005 0.342 81.389 ;
     RECT  2.304 81.059 9.774 81.841 ;
     RECT  10.512 81.059 15.426 81.841 ;
     RECT  17.064 81.329 17.154 81.869 ;
     RECT  2.304 81.841 15.426 82.021 ;
     RECT  2.268 82.021 15.426 82.061 ;
     RECT  0.18 81.389 0.342 82.267 ;
     RECT  0.18 82.267 0.414 82.319 ;
     RECT  0.18 82.319 0.342 82.349 ;
     RECT  17.064 81.869 17.082 82.606 ;
     RECT  17.064 82.606 17.154 82.634 ;
     RECT  0.144 82.459 0.162 82.637 ;
     RECT  2.304 82.061 15.426 82.859 ;
     RECT  9.792 82.859 14.994 83.102 ;
     RECT  0.288 83.371 0.306 83.467 ;
     RECT  17.136 82.634 17.154 83.489 ;
     RECT  0.216 83.467 0.306 83.548 ;
     RECT  2.304 82.859 8.91 83.605 ;
     RECT  9.792 83.102 9.81 83.605 ;
     RECT  10.548 83.102 14.994 83.759 ;
     RECT  2.304 83.605 9.81 83.851 ;
     RECT  0.108 83.548 0.306 83.947 ;
     RECT  0.108 83.947 0.846 84.139 ;
     RECT  1.98 83.851 9.81 84.139 ;
     RECT  0.108 84.139 9.81 84.181 ;
     RECT  10.548 83.759 14.958 84.181 ;
     RECT  0.108 84.181 14.958 84.883 ;
     RECT  0.108 84.883 15.066 84.983 ;
     RECT  16.632 84.883 16.65 84.991 ;
     RECT  0.108 84.983 14.958 85.379 ;
     RECT  16.56 84.991 16.65 85.801 ;
     RECT  9.108 85.379 14.958 85.891 ;
     RECT  9.108 85.891 15.354 85.999 ;
     RECT  16.524 85.801 16.65 85.999 ;
     RECT  0.108 85.379 8.226 86.063 ;
     RECT  7.815 86.063 8.226 86.161 ;
     RECT  9.108 85.999 16.65 86.161 ;
     RECT  7.815 86.161 16.65 86.197 ;
     RECT  0.108 86.063 7.038 86.611 ;
     RECT  7.815 86.197 17.262 86.765 ;
     RECT  0.036 86.611 7.038 86.881 ;
     RECT  7.815 86.765 9.594 86.881 ;
     RECT  0.036 86.881 9.594 87.511 ;
     RECT  10.332 86.765 17.262 87.511 ;
     RECT  0.036 87.511 17.262 87.821 ;
     RECT  16.488 87.821 17.262 88.651 ;
     RECT  0.036 87.821 15.426 88.771 ;
     RECT  16.452 88.651 17.262 88.771 ;
     RECT  0.036 88.771 17.262 89.735 ;
     RECT  0.036 89.735 17.19 89.744 ;
     RECT  0.036 89.744 16.506 89.879 ;
     RECT  6.552 89.879 16.506 90.239 ;
     RECT  0.036 89.879 5.706 91.085 ;
     RECT  0.828 91.085 5.706 91.319 ;
     RECT  4.68 91.319 5.706 91.429 ;
     RECT  6.588 90.239 16.506 91.435 ;
     RECT  4.68 91.429 5.778 91.471 ;
     RECT  6.588 91.435 17.19 91.471 ;
     RECT  0.036 91.085 0.09 91.625 ;
     RECT  4.68 91.471 17.19 91.625 ;
     RECT  0.828 91.319 3.834 91.661 ;
     RECT  4.68 91.625 9.81 91.769 ;
     RECT  10.548 91.625 17.19 91.976 ;
     RECT  0.828 91.661 3.798 92.039 ;
     RECT  4.68 91.769 6.822 92.039 ;
     RECT  7.56 91.769 9.81 92.129 ;
     RECT  0.036 91.625 0.054 92.165 ;
     RECT  7.56 92.129 9.666 92.165 ;
     RECT  10.584 91.976 17.19 92.309 ;
     RECT  7.56 92.165 9.594 92.399 ;
     RECT  4.68 92.039 6.786 92.821 ;
     RECT  0.828 92.039 3.618 92.911 ;
     RECT  4.68 92.821 6.822 92.911 ;
     RECT  0.828 92.911 6.822 92.975 ;
     RECT  1.98 92.975 6.822 93.047 ;
     RECT  10.728 92.309 17.19 93.055 ;
     RECT  10.44 93.055 17.19 93.119 ;
     RECT  7.704 92.399 9.594 93.181 ;
     RECT  10.44 93.119 14.922 93.181 ;
     RECT  3.78 93.047 6.822 93.217 ;
     RECT  3.78 93.217 6.93 93.253 ;
     RECT  7.704 93.181 14.922 93.253 ;
     RECT  15.912 93.119 17.19 93.281 ;
     RECT  15.948 93.281 17.19 93.389 ;
     RECT  3.78 93.253 14.922 93.479 ;
     RECT  3.78 93.479 14.886 93.485 ;
     RECT  1.98 93.047 2.97 93.587 ;
     RECT  3.78 93.485 14.814 93.749 ;
     RECT  0.828 92.975 0.846 93.785 ;
     RECT  2.415 93.587 2.97 93.793 ;
     RECT  3.78 93.749 14.778 93.793 ;
     RECT  2.415 93.793 14.778 93.929 ;
     RECT  16.38 93.389 17.19 93.929 ;
     RECT  3.744 93.929 14.778 94.019 ;
     RECT  16.38 93.929 17.118 94.019 ;
     RECT  3.852 94.019 14.778 94.109 ;
     RECT  6.876 94.109 14.778 94.199 ;
     RECT  3.852 94.109 5.742 94.289 ;
     RECT  7.056 94.199 14.778 94.289 ;
     RECT  3.852 94.289 4.23 94.325 ;
     RECT  7.056 94.289 14.742 94.325 ;
     RECT  4.068 94.325 4.23 94.361 ;
     RECT  9 94.325 14.742 94.361 ;
     RECT  9.72 94.361 14.742 94.397 ;
     RECT  2.415 93.929 2.862 94.433 ;
     RECT  7.056 94.325 8.262 94.433 ;
     RECT  10.152 94.397 14.742 94.469 ;
     RECT  17.1 94.019 17.118 94.469 ;
     RECT  4.968 94.289 4.986 94.559 ;
     RECT  5.724 94.289 5.742 94.559 ;
     RECT  7.092 94.433 8.262 94.559 ;
     RECT  10.152 94.469 10.458 94.559 ;
     RECT  11.268 94.469 14.742 94.559 ;
     RECT  4.212 94.361 4.23 94.595 ;
     RECT  10.152 94.559 10.17 94.595 ;
     RECT  2.415 94.433 2.697 94.787 ;
     RECT  7.815 94.559 8.097 94.787 ;
     RECT  11.448 94.559 14.706 94.829 ;
     RECT  11.448 94.829 11.574 94.865 ;
     RECT  14.364 94.829 14.382 94.865 ;
     RECT  12.312 94.829 12.474 94.901 ;
     RECT  13.215 94.829 13.374 94.901 ;
     RECT  11.556 94.865 11.574 94.937 ;
     RECT  12.312 94.901 12.33 95.009 ;
     RECT  2.415 94.787 2.505 95.057 ;
     RECT  7.815 94.787 7.905 95.057 ;
     RECT  13.215 94.901 13.305 95.057 ;
    LAYER M4 ;
     RECT  0.06 20.496 0.097 23.496 ;
     RECT  0.06 13.584 0.133 16.584 ;
     RECT  0.06 45.84 0.133 48.84 ;
     RECT  0.06 39.696 0.173 42.696 ;
     RECT  0.06 78.096 0.245 87.24 ;
     RECT  0.06 55.056 0.281 64.968 ;
     RECT  0.281 55.056 0.353 64.584 ;
     RECT  0.245 78.096 0.533 87.096 ;
     RECT  0.353 55.056 0.569 64.488 ;
     RECT  0.133 13.584 2.293 16.68 ;
     RECT  0.133 45.84 2.293 48.888 ;
     RECT  0.173 39.696 2.365 42.6 ;
     RECT  0.06 4.368 2.408 10.44 ;
     RECT  2.293 13.104 2.408 16.68 ;
     RECT  2.293 18.816 2.408 18.84 ;
     RECT  0.097 20.4 2.408 23.496 ;
     RECT  2.285 25.68 2.408 25.704 ;
     RECT  0.06 29.712 2.408 35.784 ;
     RECT  2.365 39.216 2.408 42.6 ;
     RECT  2.293 45.744 2.408 48.888 ;
     RECT  0.569 55.536 2.408 64.488 ;
     RECT  2.401 65.664 2.408 65.688 ;
     RECT  2.293 67.824 2.408 67.848 ;
     RECT  0.06 71.184 2.408 74.184 ;
     RECT  0.533 78.192 2.408 87.096 ;
     RECT  2.408 2.148 2.512 95.052 ;
     RECT  2.512 2.418 2.704 94.782 ;
     RECT  2.704 65.664 2.819 66.744 ;
     RECT  2.704 71.184 2.819 87.912 ;
     RECT  2.704 91.2 2.819 91.992 ;
     RECT  2.704 39.216 2.837 42.792 ;
     RECT  2.819 77.136 2.837 87.912 ;
     RECT  2.704 29.184 2.867 35.4 ;
     RECT  2.704 36.528 2.867 36.552 ;
     RECT  2.819 71.184 2.867 75.576 ;
     RECT  2.704 90 2.867 90.12 ;
     RECT  2.819 91.2 2.867 91.224 ;
     RECT  2.704 20.4 2.873 26.808 ;
     RECT  2.704 45.744 2.873 49.704 ;
     RECT  2.867 90 2.873 90.024 ;
     RECT  2.704 4.656 2.915 11.304 ;
     RECT  2.837 39.216 2.915 39.24 ;
     RECT  2.873 47.712 2.915 49.704 ;
     RECT  2.873 21.264 2.917 26.808 ;
     RECT  2.837 77.136 2.917 87.816 ;
     RECT  2.915 4.656 2.953 10.776 ;
     RECT  2.704 12.528 2.956 16.968 ;
     RECT  2.704 50.688 2.956 51.384 ;
     RECT  2.837 40.368 2.981 42.792 ;
     RECT  2.917 77.136 2.981 87.192 ;
     RECT  2.704 93.312 2.981 93.336 ;
     RECT  2.704 67.824 3.004 70.056 ;
     RECT  2.867 71.184 3.017 74.136 ;
     RECT  2.867 29.184 3.053 35.304 ;
     RECT  3.017 71.184 3.053 73.896 ;
     RECT  2.704 28.128 3.089 28.152 ;
     RECT  2.981 78.192 3.161 87.192 ;
     RECT  3.004 68.928 3.305 70.056 ;
     RECT  3.053 71.184 3.305 73.32 ;
     RECT  2.704 38.016 3.341 38.04 ;
     RECT  2.917 21.264 3.347 26.664 ;
     RECT  2.704 43.872 3.443 44.472 ;
     RECT  2.704 52.464 3.443 64.392 ;
     RECT  3.053 30.048 3.449 35.304 ;
     RECT  3.443 55.68 3.449 64.392 ;
     RECT  3.347 25.152 3.521 26.664 ;
     RECT  2.981 77.136 3.587 77.16 ;
     RECT  2.953 4.656 3.593 10.152 ;
     RECT  2.956 51.36 3.665 51.384 ;
     RECT  2.956 12.528 3.697 12.984 ;
     RECT  2.704 2.784 3.737 3.48 ;
     RECT  2.981 40.368 3.877 42.552 ;
     RECT  2.873 45.744 3.913 46.632 ;
     RECT  2.915 47.712 3.913 49.272 ;
     RECT  3.305 69.312 3.953 70.056 ;
     RECT  3.877 40.032 3.973 42.552 ;
     RECT  3.877 93.984 3.973 94.008 ;
     RECT  3.973 40.032 3.985 42.744 ;
     RECT  3.449 30.096 3.989 35.304 ;
     RECT  3.443 52.464 3.989 54.504 ;
     RECT  3.449 55.68 3.989 64.344 ;
     RECT  3.973 93.984 4.019 94.248 ;
     RECT  2.956 14.112 4.093 16.968 ;
     RECT  3.004 67.824 4.093 67.848 ;
     RECT  2.704 18 4.097 18.936 ;
     RECT  3.985 39.36 4.115 42.744 ;
     RECT  3.989 58.848 4.169 64.344 ;
     RECT  3.443 43.872 4.201 43.896 ;
     RECT  4.069 1.728 4.205 1.752 ;
     RECT  3.989 55.68 4.205 57.864 ;
     RECT  3.161 78.192 4.205 87.048 ;
     RECT  4.019 94.224 4.241 94.248 ;
     RECT  3.737 2.832 4.261 3.48 ;
     RECT  3.593 4.656 4.261 9.96 ;
     RECT  3.305 71.184 4.273 73.128 ;
     RECT  4.261 2.832 4.307 9.96 ;
     RECT  3.913 45.744 4.313 49.272 ;
     RECT  3.697 12.384 4.345 12.984 ;
     RECT  3.989 30.144 4.345 35.304 ;
     RECT  3.989 52.464 4.345 54.12 ;
     RECT  4.273 71.184 4.345 73.992 ;
     RECT  4.307 2.832 4.348 5.016 ;
     RECT  4.348 2.832 4.357 3.432 ;
     RECT  4.345 70.944 4.381 73.992 ;
     RECT  4.205 81.408 4.385 87.048 ;
     RECT  4.316 36.384 4.403 36.408 ;
     RECT  3.913 28.992 4.417 29.016 ;
     RECT  3.985 91.2 4.417 91.224 ;
     RECT  4.093 13.968 4.453 16.968 ;
     RECT  4.205 55.68 4.489 57.48 ;
     RECT  3.521 25.152 4.493 25.56 ;
     RECT  4.345 30.144 4.493 35.352 ;
     RECT  4.313 45.744 4.493 48.84 ;
     RECT  4.345 11.472 4.499 12.984 ;
     RECT  4.417 90.816 4.508 91.224 ;
     RECT  3.521 26.64 4.525 26.664 ;
     RECT  4.489 55.296 4.529 57.48 ;
     RECT  4.385 81.408 4.529 85.896 ;
     RECT  4.508 89.904 4.595 91.224 ;
     RECT  4.417 28.704 4.597 29.016 ;
     RECT  2.867 75.552 4.601 75.576 ;
     RECT  4.097 18.24 4.604 18.936 ;
     RECT  4.205 78.192 4.633 79.56 ;
     RECT  4.493 46.224 4.637 48.84 ;
     RECT  4.529 56.304 4.637 57.48 ;
     RECT  3.953 69.312 4.637 69.336 ;
     RECT  4.604 18.24 4.645 19.272 ;
     RECT  4.525 25.824 4.673 26.664 ;
     RECT  4.645 18.24 4.691 20.184 ;
     RECT  4.525 24.624 4.693 24.648 ;
     RECT  4.345 51.84 4.709 54.12 ;
     RECT  4.381 70.944 4.709 74.04 ;
     RECT  4.673 25.824 4.739 26.28 ;
     RECT  4.093 37.632 4.741 37.656 ;
     RECT  4.115 39.36 4.741 42.216 ;
     RECT  4.637 46.224 4.745 48.408 ;
     RECT  4.169 58.848 4.781 64.2 ;
     RECT  4.741 37.632 4.787 42.216 ;
     RECT  4.549 88.896 4.813 88.92 ;
     RECT  4.633 77.712 4.817 79.56 ;
     RECT  4.787 37.632 4.828 38.568 ;
     RECT  4.385 86.928 4.849 87.048 ;
     RECT  4.813 88.224 4.849 88.92 ;
     RECT  4.493 30.72 4.853 35.352 ;
     RECT  4.745 48.384 4.853 48.408 ;
     RECT  4.499 11.952 4.885 12.984 ;
     RECT  4.453 13.968 4.885 17.064 ;
     RECT  3.347 21.264 4.961 22.776 ;
     RECT  4.817 77.712 4.961 79.032 ;
     RECT  4.885 11.952 4.979 17.064 ;
     RECT  4.979 12.48 5.02 12.504 ;
     RECT  4.357 2.832 5.033 3.144 ;
     RECT  4.691 18.24 5.033 18.84 ;
     RECT  4.853 30.72 5.033 33.288 ;
     RECT  4.529 55.296 5.033 55.32 ;
     RECT  4.961 78.864 5.033 79.032 ;
     RECT  4.849 86.928 5.033 88.92 ;
     RECT  4.979 13.584 5.069 17.064 ;
     RECT  4.201 43.392 5.069 43.896 ;
     RECT  5.069 16.368 5.077 17.064 ;
     RECT  5.033 18.24 5.077 18.792 ;
     RECT  5.036 76.368 5.077 76.392 ;
     RECT  4.961 77.712 5.077 77.736 ;
     RECT  5.077 76.368 5.123 77.736 ;
     RECT  4.529 81.408 5.123 85.848 ;
     RECT  4.691 20.16 5.125 20.184 ;
     RECT  4.348 4.656 5.141 5.016 ;
     RECT  4.787 39.744 5.141 42.216 ;
     RECT  5.123 81.408 5.164 85.224 ;
     RECT  3.973 92.928 5.164 92.952 ;
     RECT  5.077 16.368 5.177 18.792 ;
     RECT  5.141 39.744 5.177 40.44 ;
     RECT  5.033 86.928 5.177 88.248 ;
     RECT  4.597 28.608 5.209 29.016 ;
     RECT  4.637 56.784 5.209 57.48 ;
     RECT  4.709 52.752 5.213 54.12 ;
     RECT  4.307 6 5.237 9.96 ;
     RECT  4.693 24.48 5.237 24.648 ;
     RECT  4.781 59.088 5.245 64.2 ;
     RECT  5.237 23.952 5.249 24.648 ;
     RECT  4.709 72.432 5.249 74.04 ;
     RECT  5.125 20.16 5.267 21.144 ;
     RECT  5.209 56.784 5.281 57.528 ;
     RECT  2.819 65.712 5.317 66.744 ;
     RECT  4.093 67.824 5.317 68.088 ;
     RECT  5.237 6 5.321 10.872 ;
     RECT  5.267 21.12 5.321 21.144 ;
     RECT  5.249 23.952 5.321 23.976 ;
     RECT  5.164 81.408 5.353 83.208 ;
     RECT  4.961 22.128 5.356 22.776 ;
     RECT  5.213 52.752 5.393 52.776 ;
     RECT  5.141 4.848 5.425 5.016 ;
     RECT  5.321 6 5.425 10.2 ;
     RECT  5.249 74.016 5.425 74.04 ;
     RECT  4.847 75.024 5.425 75.144 ;
     RECT  5.033 31.104 5.429 33.288 ;
     RECT  4.595 90.576 5.429 91.224 ;
     RECT  4.739 25.824 5.461 26.136 ;
     RECT  4.853 34.32 5.497 35.352 ;
     RECT  5.069 43.392 5.497 43.512 ;
     RECT  5.101 93.984 5.497 94.008 ;
     RECT  5.425 74.016 5.537 75.144 ;
     RECT  5.353 80.976 5.557 83.208 ;
     RECT  5.123 77.136 5.645 77.736 ;
     RECT  5.429 32.16 5.699 33.288 ;
     RECT  5.281 69.552 5.699 69.576 ;
     RECT  5.141 41.424 5.701 42.216 ;
     RECT  5.497 43.344 5.701 43.512 ;
     RECT  5.177 86.928 5.713 87.576 ;
     RECT  5.209 28.608 5.749 29.64 ;
     RECT  5.497 34.32 5.749 36.216 ;
     RECT  4.828 37.632 5.749 37.656 ;
     RECT  5.317 65.712 5.753 68.088 ;
     RECT  5.645 77.712 5.753 77.736 ;
     RECT  5.537 74.064 5.789 75.144 ;
     RECT  5.749 34.32 5.795 37.656 ;
     RECT  5.245 59.088 5.825 64.392 ;
     RECT  5.795 37.008 5.833 37.656 ;
     RECT  5.789 74.64 5.861 75.144 ;
     RECT  5.033 2.976 5.965 3.144 ;
     RECT  5.749 27.984 5.965 29.64 ;
     RECT  5.281 56.784 5.989 57.576 ;
     RECT  5.825 59.088 5.989 60.984 ;
     RECT  5.989 56.784 5.996 60.984 ;
     RECT  5.213 53.904 6.001 54.12 ;
     RECT  5.425 4.848 6.005 10.2 ;
     RECT  5.069 13.584 6.037 14.808 ;
     RECT  5.753 67.872 6.037 68.088 ;
     RECT  5.461 25.056 6.073 26.136 ;
     RECT  5.996 56.64 6.076 60.984 ;
     RECT  6.076 56.64 6.083 57.336 ;
     RECT  5.965 2.976 6.109 3.864 ;
     RECT  6.005 4.848 6.109 5.112 ;
     RECT  5.177 17.04 6.145 17.88 ;
     RECT  6.001 53.904 6.145 55.032 ;
     RECT  4.709 70.944 6.145 71.064 ;
     RECT  5.249 72.432 6.145 72.984 ;
     RECT  6.109 2.976 6.149 5.112 ;
     RECT  6.145 53.904 6.181 55.272 ;
     RECT  4.745 46.224 6.185 47.208 ;
     RECT  5.389 49.872 6.217 49.896 ;
     RECT  5.033 78.864 6.217 78.888 ;
     RECT  5.164 84.672 6.217 85.224 ;
     RECT  5.701 41.424 6.221 43.512 ;
     RECT  6.073 25.056 6.227 26.664 ;
     RECT  6.109 12.336 6.229 12.36 ;
     RECT  6.037 13.584 6.229 14.904 ;
     RECT  5.177 39.744 6.229 40.056 ;
     RECT  6.221 41.424 6.229 41.976 ;
     RECT  5.753 65.712 6.253 66.792 ;
     RECT  6.217 78.768 6.253 78.888 ;
     RECT  5.557 80.256 6.253 83.208 ;
     RECT  5.497 93.6 6.253 94.008 ;
     RECT  6.145 17.04 6.257 18.168 ;
     RECT  6.076 58.368 6.257 60.984 ;
     RECT  6.229 12.336 6.275 14.904 ;
     RECT  6.229 39.744 6.275 41.976 ;
     RECT  5.699 32.832 6.277 33.288 ;
     RECT  6.227 25.056 6.289 26.136 ;
     RECT  5.833 37.008 6.293 37.032 ;
     RECT  6.253 93.6 6.293 94.104 ;
     RECT  5.749 91.344 6.323 91.464 ;
     RECT  6.289 24.528 6.329 26.136 ;
     RECT  6.275 40.704 6.329 41.976 ;
     RECT  6.217 49.872 6.329 50.184 ;
     RECT  6.257 59.856 6.329 60.984 ;
     RECT  6.253 78.768 6.329 83.208 ;
     RECT  6.005 6.24 6.361 10.2 ;
     RECT  5.795 34.992 6.365 35.256 ;
     RECT  6.361 6.24 6.401 10.92 ;
     RECT  6.275 12.336 6.401 14.808 ;
     RECT  6.365 34.992 6.401 35.016 ;
     RECT  5.965 27.744 6.437 29.64 ;
     RECT  5.356 22.176 6.469 22.776 ;
     RECT  6.329 24.528 6.469 25.752 ;
     RECT  6.217 84.672 6.505 85.32 ;
     RECT  6.469 22.176 6.509 25.752 ;
     RECT  6.509 22.176 6.515 24.552 ;
     RECT  6.145 70.944 6.517 72.984 ;
     RECT  5.713 86.64 6.517 87.576 ;
     RECT  6.401 12.336 6.545 14.76 ;
     RECT  6.329 82.368 6.572 83.208 ;
     RECT  6.505 84.576 6.572 85.32 ;
     RECT  6.073 48.384 6.577 48.408 ;
     RECT  6.401 9.072 6.581 10.92 ;
     RECT  6.277 32.832 6.581 33.816 ;
     RECT  6.572 82.368 6.611 85.32 ;
     RECT  5.429 31.104 6.613 31.128 ;
     RECT  5.825 62.16 6.613 64.392 ;
     RECT  6.253 65.52 6.613 66.792 ;
     RECT  6.329 78.768 6.613 81.048 ;
     RECT  6.611 83.76 6.613 85.32 ;
     RECT  6.517 86.64 6.613 87.816 ;
     RECT  6.581 9.936 6.649 10.92 ;
     RECT  6.613 83.76 6.649 87.816 ;
     RECT  6.649 83.76 6.653 88.104 ;
     RECT  6.329 60.96 6.659 60.984 ;
     RECT  6.653 83.76 6.659 86.04 ;
     RECT  6.613 62.16 6.7 66.792 ;
     RECT  6.649 9.936 6.721 11.16 ;
     RECT  6.545 12.336 6.721 13.656 ;
     RECT  6.437 27.744 6.721 29.016 ;
     RECT  6.323 91.344 6.721 91.368 ;
     RECT  6.7 63.072 6.757 66.792 ;
     RECT  6.037 67.872 6.757 68.904 ;
     RECT  6.613 78.384 6.757 81.048 ;
     RECT  6.181 53.568 6.793 55.272 ;
     RECT  6.515 22.176 6.803 24.504 ;
     RECT  6.653 87.216 6.805 88.104 ;
     RECT  5.929 89.424 6.805 89.448 ;
     RECT  6.329 50.064 6.829 50.184 ;
     RECT  6.757 51.312 6.829 51.336 ;
     RECT  5.861 74.64 6.829 74.664 ;
     RECT  6.217 75.936 6.829 75.96 ;
     RECT  6.613 31.104 6.853 31.656 ;
     RECT  6.581 32.832 6.853 33.624 ;
     RECT  6.757 52.416 6.853 52.44 ;
     RECT  6.793 53.568 6.853 55.992 ;
     RECT  6.757 78.336 6.853 81.048 ;
     RECT  6.257 17.712 6.901 18.168 ;
     RECT  6.253 19.968 6.901 19.992 ;
     RECT  6.853 78.288 6.901 81.048 ;
     RECT  6.149 3.072 6.973 5.112 ;
     RECT  6.901 19.968 7.093 20.568 ;
     RECT  6.221 43.488 7.117 43.512 ;
     RECT  6.829 44.592 7.117 44.616 ;
     RECT  7.093 19.728 7.189 20.568 ;
     RECT  6.803 22.176 7.189 22.296 ;
     RECT  7.004 38.592 7.225 38.616 ;
     RECT  6.757 63.072 7.297 68.904 ;
     RECT  6.185 46.896 7.333 47.208 ;
     RECT  6.401 6.24 7.369 7.944 ;
     RECT  6.577 16.464 7.369 16.584 ;
     RECT  6.853 30.768 7.369 33.624 ;
     RECT  6.901 34.896 7.381 34.92 ;
     RECT  7.117 43.488 7.441 44.616 ;
     RECT  6.853 52.416 7.525 55.992 ;
     RECT  6.083 57.312 7.525 57.336 ;
     RECT  6.257 58.368 7.525 58.632 ;
     RECT  7.297 63.072 7.525 69.432 ;
     RECT  6.517 70.464 7.525 72.984 ;
     RECT  6.829 50.064 7.549 51.336 ;
     RECT  7.525 52.416 7.549 57.336 ;
     RECT  6.329 59.856 7.549 59.88 ;
     RECT  7.405 37.056 7.585 37.08 ;
     RECT  7.225 38.16 7.585 38.616 ;
     RECT  6.611 82.368 7.621 82.632 ;
     RECT  7.549 59.808 7.657 59.88 ;
     RECT  7.525 63.072 7.693 72.984 ;
     RECT  7.621 45.744 7.729 45.768 ;
     RECT  6.973 3.072 7.808 5.16 ;
     RECT  7.369 6.24 7.808 8.52 ;
     RECT  6.721 9.936 7.808 13.656 ;
     RECT  7.369 14.88 7.808 16.584 ;
     RECT  6.901 17.712 7.808 18.6 ;
     RECT  7.189 19.728 7.808 22.296 ;
     RECT  6.803 23.376 7.808 24.504 ;
     RECT  6.509 25.728 7.808 25.752 ;
     RECT  6.721 27.312 7.808 29.016 ;
     RECT  7.369 30.144 7.808 33.624 ;
     RECT  7.381 34.752 7.808 34.92 ;
     RECT  7.585 36.096 7.808 38.616 ;
     RECT  7.004 39.6 7.808 39.624 ;
     RECT  6.329 40.848 7.808 41.976 ;
     RECT  7.441 43.296 7.808 44.616 ;
     RECT  7.729 45.696 7.808 45.768 ;
     RECT  7.333 46.896 7.808 47.304 ;
     RECT  6.577 48.384 7.808 48.984 ;
     RECT  7.549 50.064 7.808 57.336 ;
     RECT  7.525 58.368 7.808 58.776 ;
     RECT  7.657 59.808 7.808 60.312 ;
     RECT  7.693 63.072 7.808 73.272 ;
     RECT  6.829 74.64 7.808 75.96 ;
     RECT  6.853 76.944 7.808 76.968 ;
     RECT  6.901 78.048 7.808 81.048 ;
     RECT  7.621 82.272 7.808 82.632 ;
     RECT  6.659 84.576 7.808 86.04 ;
     RECT  6.805 87.216 7.808 89.448 ;
     RECT  6.721 90.72 7.808 91.368 ;
     RECT  5.497 92.544 7.808 92.568 ;
     RECT  6.293 93.792 7.808 94.104 ;
     RECT  7.808 2.148 7.912 95.052 ;
     RECT  7.912 2.418 8.104 94.782 ;
     RECT  8.104 40.464 8.201 42.168 ;
     RECT  8.104 57.312 8.201 57.336 ;
     RECT  8.104 15.456 8.237 15.528 ;
     RECT  8.104 72.432 8.237 72.456 ;
     RECT  8.104 80.016 8.237 80.904 ;
     RECT  8.104 8.688 8.243 8.712 ;
     RECT  8.104 49.488 8.243 55.272 ;
     RECT  8.104 75.648 8.243 76.152 ;
     RECT  8.201 42.144 8.245 42.168 ;
     RECT  8.104 73.632 8.273 74.04 ;
     RECT  8.104 24.24 8.281 28.296 ;
     RECT  8.104 62.16 8.281 66.216 ;
     RECT  8.104 43.152 8.291 45.72 ;
     RECT  8.104 46.8 8.291 46.824 ;
     RECT  8.104 10.848 8.309 13.128 ;
     RECT  8.273 74.016 8.309 74.04 ;
     RECT  8.104 77.232 8.345 77.256 ;
     RECT  8.104 84.912 8.381 85.176 ;
     RECT  8.104 82.272 8.453 83.736 ;
     RECT  8.281 27.6 8.489 28.296 ;
     RECT  8.243 52.512 8.525 55.272 ;
     RECT  8.104 59.808 8.525 60.84 ;
     RECT  8.104 3.12 8.531 7.032 ;
     RECT  8.309 11.376 8.531 13.128 ;
     RECT  8.531 11.376 8.572 12.552 ;
     RECT  8.104 69.024 8.597 69.816 ;
     RECT  8.104 88.752 8.633 90.264 ;
     RECT  8.281 24.24 8.705 26.424 ;
     RECT  8.489 27.696 8.705 28.296 ;
     RECT  8.104 30.288 8.705 32.904 ;
     RECT  8.243 49.488 8.705 50.184 ;
     RECT  8.453 82.272 8.813 83.64 ;
     RECT  8.104 93.312 8.813 94.056 ;
     RECT  8.531 3.264 8.819 7.032 ;
     RECT  8.104 39.216 8.819 39.24 ;
     RECT  8.201 40.464 8.921 40.968 ;
     RECT  8.104 21.168 8.957 21.192 ;
     RECT  8.921 40.464 8.957 40.92 ;
     RECT  8.525 59.856 8.957 60.84 ;
     RECT  8.525 52.512 8.993 53.592 ;
     RECT  8.281 62.16 8.993 65.928 ;
     RECT  8.633 88.752 8.993 88.776 ;
     RECT  8.104 35.28 9.011 38.232 ;
     RECT  8.705 24.24 9.065 25.224 ;
     RECT  8.104 22.176 9.097 23.16 ;
     RECT  9.011 35.856 9.107 38.232 ;
     RECT  8.633 89.856 9.107 90.264 ;
     RECT  8.104 19.92 9.109 19.944 ;
     RECT  9.097 22.176 9.137 23.64 ;
     RECT  8.705 30.288 9.137 30.312 ;
     RECT  8.993 62.784 9.137 65.928 ;
     RECT  8.104 86.544 9.137 87.72 ;
     RECT  9.109 19.92 9.155 20.568 ;
     RECT  9.107 35.856 9.173 38.184 ;
     RECT  8.291 43.152 9.173 43.176 ;
     RECT  8.104 58.656 9.205 58.68 ;
     RECT  8.243 75.648 9.205 75.672 ;
     RECT  9.137 23.328 9.209 23.64 ;
     RECT  9.137 62.784 9.209 63.24 ;
     RECT  8.237 80.784 9.233 80.904 ;
     RECT  8.819 6.672 9.245 7.032 ;
     RECT  9.137 22.176 9.245 22.2 ;
     RECT  9.137 64.368 9.245 65.928 ;
     RECT  8.813 82.272 9.253 82.296 ;
     RECT  8.705 26.4 9.281 26.424 ;
     RECT  8.705 50.16 9.281 50.184 ;
     RECT  8.104 78.432 9.313 78.456 ;
     RECT  9.233 80.352 9.317 80.904 ;
     RECT  8.104 48.432 9.349 48.456 ;
     RECT  9.137 87.168 9.349 87.72 ;
     RECT  8.705 28.128 9.353 28.296 ;
     RECT  8.525 55.104 9.397 55.272 ;
     RECT  8.104 56.256 9.397 56.28 ;
     RECT  8.381 84.912 9.397 84.936 ;
     RECT  9.155 20.544 9.425 20.568 ;
     RECT  9.245 65.136 9.425 65.928 ;
     RECT  9.349 47.904 9.443 48.456 ;
     RECT  9.397 84.912 9.443 85.704 ;
     RECT  9.169 74.592 9.457 74.616 ;
     RECT  9.205 75.648 9.457 76.392 ;
     RECT  9.173 35.856 9.461 37.032 ;
     RECT  8.291 44.16 9.493 45.576 ;
     RECT  9.313 78.336 9.493 78.456 ;
     RECT  8.237 15.456 9.497 15.48 ;
     RECT  9.065 24.624 9.497 25.224 ;
     RECT  8.243 51.36 9.529 51.384 ;
     RECT  9.397 55.104 9.529 56.28 ;
     RECT  9.205 58.656 9.529 58.728 ;
     RECT  8.957 59.856 9.529 60.648 ;
     RECT  9.107 89.952 9.529 90.264 ;
     RECT  8.104 91.248 9.529 91.8 ;
     RECT  8.813 93.312 9.529 93.336 ;
     RECT  8.819 3.264 9.533 5.4 ;
     RECT  9.533 3.264 9.569 4.056 ;
     RECT  9.529 51.264 9.569 51.384 ;
     RECT  9.529 54.624 9.589 56.28 ;
     RECT  9.167 57.264 9.589 57.288 ;
     RECT  9.529 89.952 9.596 91.8 ;
     RECT  8.572 12.336 9.601 12.552 ;
     RECT  8.597 69.552 9.605 69.816 ;
     RECT  9.457 74.592 9.605 76.392 ;
     RECT  9.589 54.624 9.635 57.288 ;
     RECT  9.601 11.952 9.645 12.552 ;
     RECT  8.705 31.872 9.673 32.904 ;
     RECT  9.497 24.624 9.677 24.648 ;
     RECT  9.605 74.64 9.683 76.392 ;
     RECT  9.596 89.952 9.683 92.136 ;
     RECT  8.104 16.512 9.685 16.536 ;
     RECT  9.443 47.904 9.685 47.928 ;
     RECT  9.353 28.128 9.701 28.152 ;
     RECT  8.957 40.896 9.713 40.92 ;
     RECT  8.993 53.04 9.713 53.592 ;
     RECT  9.493 78.336 9.713 79.272 ;
     RECT  9.601 14.592 9.731 14.616 ;
     RECT  9.685 47.28 9.731 47.928 ;
     RECT  9.701 27.984 9.733 28.152 ;
     RECT  9.713 78.336 9.733 78.504 ;
     RECT  9.317 80.64 9.745 80.904 ;
     RECT  9.253 82.08 9.745 82.296 ;
     RECT  9.493 71.616 9.749 72.984 ;
     RECT  9.731 47.28 9.772 47.304 ;
     RECT  9.683 74.688 9.779 76.392 ;
     RECT  9.683 89.952 9.779 91.944 ;
     RECT  9.745 80.64 9.781 82.296 ;
     RECT  8.813 83.472 9.781 83.64 ;
     RECT  9.733 27.216 9.82 28.152 ;
     RECT  9.461 36.432 9.821 37.032 ;
     RECT  9.673 31.488 9.893 32.904 ;
     RECT  9.425 65.52 9.961 65.928 ;
     RECT  9.685 66.912 9.961 66.936 ;
     RECT  9.893 32.64 9.965 32.904 ;
     RECT  9.685 15.984 10.001 16.536 ;
     RECT  9.82 28.128 10.001 28.152 ;
     RECT  9.749 71.616 10.001 72.456 ;
     RECT  9.209 23.616 10.033 23.64 ;
     RECT  9.569 3.264 10.037 3.864 ;
     RECT  9.529 58.656 10.069 60.648 ;
     RECT  9.779 89.952 10.069 90.024 ;
     RECT  9.169 68.352 10.076 68.376 ;
     RECT  9.605 69.552 10.076 69.576 ;
     RECT  10.069 39.888 10.105 39.912 ;
     RECT  9.529 48.96 10.109 48.984 ;
     RECT  9.529 93.216 10.141 93.336 ;
     RECT  9.965 32.88 10.177 32.904 ;
     RECT  9.493 43.776 10.213 45.576 ;
     RECT  9.853 46.704 10.213 46.728 ;
     RECT  9.961 65.52 10.213 66.936 ;
     RECT  10.076 68.352 10.213 69.576 ;
     RECT  10.037 3.264 10.217 3.336 ;
     RECT  10.069 18.816 10.249 19.272 ;
     RECT  9.779 74.688 10.253 75.672 ;
     RECT  10.249 18.528 10.261 19.272 ;
     RECT  9.713 53.04 10.261 53.496 ;
     RECT  9.645 11.952 10.285 13.272 ;
     RECT  8.104 17.52 10.285 17.544 ;
     RECT  10.261 18.528 10.285 19.944 ;
     RECT  9.173 38.16 10.289 38.184 ;
     RECT  10.213 65.52 10.289 69.576 ;
     RECT  10.285 17.52 10.307 19.944 ;
     RECT  10.141 93.216 10.307 94.248 ;
     RECT  10.217 3.264 10.325 3.288 ;
     RECT  10.033 23.616 10.325 23.688 ;
     RECT  10.213 43.776 10.325 46.728 ;
     RECT  9.781 80.64 10.355 84.36 ;
     RECT  10.249 21.504 10.357 21.528 ;
     RECT  9.443 85.68 10.357 85.704 ;
     RECT  9.349 87.168 10.357 88.296 ;
     RECT  9.533 5.376 10.361 5.4 ;
     RECT  9.277 7.392 10.361 7.416 ;
     RECT  10.289 68.928 10.361 69.576 ;
     RECT  10.261 52.32 10.433 53.496 ;
     RECT  10.253 74.688 10.451 75.576 ;
     RECT  9.209 62.784 10.453 63 ;
     RECT  9.569 51.264 10.497 51.288 ;
     RECT  10.453 62.784 10.501 63.768 ;
     RECT  10.289 65.52 10.501 67.464 ;
     RECT  9.493 42.192 10.505 42.264 ;
     RECT  10.325 44.208 10.505 45.192 ;
     RECT  9.733 77.808 10.537 78.504 ;
     RECT  10.501 62.736 10.54 63.768 ;
     RECT  10.307 17.52 10.547 18.84 ;
     RECT  9.635 54.72 10.549 57.288 ;
     RECT  10.069 58.656 10.549 60.84 ;
     RECT  10.105 39.264 10.577 39.912 ;
     RECT  10.355 80.64 10.597 81.528 ;
     RECT  9.893 31.488 10.649 31.512 ;
     RECT  10.001 71.856 10.649 72.456 ;
     RECT  10.177 32.88 10.681 33.864 ;
     RECT  10.549 54.72 10.693 60.84 ;
     RECT  10.681 32.88 10.717 34.344 ;
     RECT  10.681 35.328 10.717 35.352 ;
     RECT  9.821 36.432 10.717 36.504 ;
     RECT  10.285 50.112 10.717 50.136 ;
     RECT  10.537 77.088 10.741 78.504 ;
     RECT  9.781 8.496 10.789 8.52 ;
     RECT  9.997 9.936 10.789 9.96 ;
     RECT  10.285 11.952 10.789 14.232 ;
     RECT  10.069 41.136 10.789 41.16 ;
     RECT  10.357 85.68 10.789 88.296 ;
     RECT  10.069 89.28 10.789 90.024 ;
     RECT  10.717 50.112 10.825 51 ;
     RECT  10.789 85.68 10.825 90.024 ;
     RECT  9.779 91.104 10.825 91.944 ;
     RECT  10.307 93.216 10.825 93.384 ;
     RECT  10.693 54.72 10.829 61.608 ;
     RECT  10.748 23.184 10.835 23.208 ;
     RECT  10.501 64.848 10.835 67.464 ;
     RECT  10.355 82.8 10.861 84.36 ;
     RECT  10.001 16.512 10.865 16.536 ;
     RECT  10.825 49.824 10.937 51 ;
     RECT  10.829 54.72 10.973 56.472 ;
     RECT  10.825 85.68 10.973 93.384 ;
     RECT  10.861 82.8 10.979 84.648 ;
     RECT  10.748 24.528 11.005 24.552 ;
     RECT  10.829 57.6 11.005 61.608 ;
     RECT  10.54 62.736 11.005 63.24 ;
     RECT  10.547 17.52 11.027 18.216 ;
     RECT  10.789 11.904 11.041 14.232 ;
     RECT  10.433 52.512 11.041 53.496 ;
     RECT  10.973 54.72 11.041 56.376 ;
     RECT  10.979 82.8 11.045 83.592 ;
     RECT  10.717 32.88 11.075 36.504 ;
     RECT  10.789 8.496 11.077 9.96 ;
     RECT  10.741 76.704 11.077 78.504 ;
     RECT  10.597 79.584 11.077 81.528 ;
     RECT  10.973 91.104 11.081 93.384 ;
     RECT  11.077 8.496 11.113 10.008 ;
     RECT  10.979 84.624 11.113 84.648 ;
     RECT  10.973 85.68 11.113 89.976 ;
     RECT  10.835 64.848 11.153 66.408 ;
     RECT  11.113 8.496 11.173 10.584 ;
     RECT  11.041 11.712 11.173 14.232 ;
     RECT  10.325 46.176 11.185 46.728 ;
     RECT  11.153 64.848 11.189 66.12 ;
     RECT  11.113 84.624 11.189 89.976 ;
     RECT  11.173 8.496 11.219 14.232 ;
     RECT  10.577 39.792 11.225 39.912 ;
     RECT  10.861 28.464 11.228 28.488 ;
     RECT  11.029 38.784 11.257 38.808 ;
     RECT  10.141 25.968 11.269 25.992 ;
     RECT  10.789 41.136 11.293 41.736 ;
     RECT  11.081 91.92 11.293 93.384 ;
     RECT  11.189 84.864 11.297 89.976 ;
     RECT  10.825 6.768 11.329 6.792 ;
     RECT  10.835 67.44 11.329 67.464 ;
     RECT  10.361 68.928 11.329 68.952 ;
     RECT  11.041 73.344 11.329 73.368 ;
     RECT  11.293 91.92 11.333 94.104 ;
     RECT  11.269 25.968 11.356 26.28 ;
     RECT  11.257 38.112 11.365 38.808 ;
     RECT  10.505 44.208 11.365 44.232 ;
     RECT  11.005 57.6 11.369 63.24 ;
     RECT  11.219 8.496 11.405 10.008 ;
     RECT  10.789 15.408 11.405 15.432 ;
     RECT  11.075 32.88 11.405 35.976 ;
     RECT  11.329 6.576 11.42 6.792 ;
     RECT  10.307 19.872 11.437 19.944 ;
     RECT  11.219 13.152 11.441 14.232 ;
     RECT  11.027 18.192 11.441 18.216 ;
     RECT  11.333 92.688 11.459 94.104 ;
     RECT  11.42 6.24 11.461 6.792 ;
     RECT  11.041 52.512 11.469 56.376 ;
     RECT  10.451 74.928 11.473 75.576 ;
     RECT  11.077 76.704 11.473 81.528 ;
     RECT  11.365 44.112 11.477 44.232 ;
     RECT  11.473 74.928 11.477 81.528 ;
     RECT  11.461 6.24 11.507 7.464 ;
     RECT  11.477 76.368 11.507 81.528 ;
     RECT  11.441 13.248 11.509 14.232 ;
     RECT  11.405 32.88 11.509 33.48 ;
     RECT  11.459 92.976 11.509 94.104 ;
     RECT  11.369 57.6 11.513 61.752 ;
     RECT  11.507 76.368 11.513 79.272 ;
     RECT  11.507 80.736 11.549 81.528 ;
     RECT  11.509 92.976 11.549 94.152 ;
     RECT  11.221 42.768 11.557 42.984 ;
     RECT  11.437 19.872 11.564 20.04 ;
     RECT  11.564 18.384 11.581 20.04 ;
     RECT  11.297 87.792 11.585 89.976 ;
     RECT  11.557 42.72 11.603 42.984 ;
     RECT  11.221 4.56 11.605 4.584 ;
     RECT  11.189 64.848 11.617 65.832 ;
     RECT  11.585 87.792 11.621 89.304 ;
     RECT  11.605 4.56 11.653 5.112 ;
     RECT  11.405 8.496 11.653 9.672 ;
     RECT  11.581 18.384 11.653 20.376 ;
     RECT  10.357 21.504 11.653 21.672 ;
     RECT  11.005 24.528 11.653 24.888 ;
     RECT  11.369 62.736 11.653 63.24 ;
     RECT  11.469 52.512 11.689 55.896 ;
     RECT  11.329 73.344 11.689 73.56 ;
     RECT  11.653 3.024 11.692 5.112 ;
     RECT  11.219 11.088 11.693 11.928 ;
     RECT  11.509 32.64 11.693 33.48 ;
     RECT  11.653 8.448 11.699 9.672 ;
     RECT  11.653 18.384 11.699 21.672 ;
     RECT  11.513 76.368 11.699 78.504 ;
     RECT  11.293 40.512 11.725 41.736 ;
     RECT  11.603 42.72 11.725 42.744 ;
     RECT  11.699 18.384 11.729 20.76 ;
     RECT  11.689 52.368 11.729 55.896 ;
     RECT  11.729 19.92 11.74 20.76 ;
     RECT  11.729 18.384 11.747 18.408 ;
     RECT  11.699 77.04 11.747 78.504 ;
     RECT  11.699 8.448 11.765 9.144 ;
     RECT  11.729 52.368 11.765 54.264 ;
     RECT  11.405 35.04 11.801 35.976 ;
     RECT  11.549 93.12 11.801 94.152 ;
     RECT  11.329 67.44 11.833 69 ;
     RECT  11.507 6.576 11.837 7.464 ;
     RECT  11.765 8.448 11.837 8.472 ;
     RECT  11.617 22.752 11.852 22.776 ;
     RECT  11.653 24.048 11.869 24.888 ;
     RECT  11.356 25.968 11.869 25.992 ;
     RECT  11.801 35.04 11.873 35.928 ;
     RECT  11.516 44.016 11.873 44.04 ;
     RECT  11.185 46.176 11.873 47.064 ;
     RECT  11.852 22.752 11.893 22.968 ;
     RECT  11.041 71.616 11.905 71.64 ;
     RECT  11.873 35.04 11.909 35.208 ;
     RECT  11.617 64.8 11.909 65.832 ;
     RECT  11.893 22.176 11.939 22.968 ;
     RECT  11.869 24.048 11.939 25.992 ;
     RECT  11.692 3.024 11.941 4.584 ;
     RECT  11.689 73.248 11.945 73.56 ;
     RECT  11.477 74.928 11.945 74.952 ;
     RECT  11.939 25.104 11.953 25.992 ;
     RECT  11.228 27.6 11.977 28.488 ;
     RECT  11.939 22.176 11.98 22.776 ;
     RECT  11.837 6.768 11.981 7.464 ;
     RECT  11.621 88.08 11.981 88.68 ;
     RECT  11.765 52.368 11.987 53.784 ;
     RECT  11.513 57.6 11.987 61.656 ;
     RECT  11.977 27.312 11.989 28.488 ;
     RECT  11.365 37.2 11.989 38.808 ;
     RECT  11.077 31.296 12.013 31.32 ;
     RECT  11.701 82.656 12.013 82.68 ;
     RECT  11.981 6.816 12.017 7.464 ;
     RECT  11.725 40.512 12.017 42.744 ;
     RECT  11.987 57.6 12.017 58.152 ;
     RECT  11.909 64.944 12.017 65.832 ;
     RECT  11.747 77.04 12.017 78.168 ;
     RECT  11.693 32.976 12.035 33.48 ;
     RECT  12.017 40.512 12.035 42.216 ;
     RECT  11.509 13.248 12.053 14.424 ;
     RECT  11.74 19.92 12.053 20.376 ;
     RECT  11.909 35.184 12.053 35.208 ;
     RECT  11.987 53.328 12.053 53.784 ;
     RECT  11.987 59.616 12.053 61.656 ;
     RECT  11.989 27.312 12.061 28.632 ;
     RECT  12.053 53.328 12.089 53.352 ;
     RECT  11.653 62.736 12.089 63.288 ;
     RECT  11.833 67.44 12.089 69.528 ;
     RECT  11.989 37.2 12.125 38.904 ;
     RECT  11.725 48.96 12.125 48.984 ;
     RECT  12.053 59.616 12.125 61.032 ;
     RECT  11.801 93.216 12.125 94.152 ;
     RECT  11.98 22.56 12.161 22.776 ;
     RECT  11.873 46.176 12.161 46.2 ;
     RECT  12.053 13.584 12.197 13.656 ;
     RECT  12.161 22.56 12.197 22.584 ;
     RECT  12.017 77.04 12.197 77.88 ;
     RECT  12.125 93.36 12.197 93.384 ;
     RECT  12.035 40.512 12.233 41.352 ;
     RECT  12.017 65.808 12.233 65.832 ;
     RECT  12.089 67.44 12.233 68.28 ;
     RECT  12.013 81.792 12.337 82.68 ;
     RECT  12.061 27.888 12.373 28.632 ;
     RECT  12.013 30.576 12.517 31.368 ;
     RECT  11.297 84.864 12.589 86.712 ;
     RECT  11.905 71.616 12.661 71.88 ;
     RECT  12.553 90.288 12.697 90.312 ;
     RECT  12.337 81.792 12.709 83.208 ;
     RECT  12.589 84.864 13.021 86.76 ;
     RECT  11.981 88.08 13.021 88.44 ;
     RECT  12.805 9.024 13.057 9.048 ;
     RECT  12.373 27.888 13.057 29.064 ;
     RECT  12.035 32.976 13.093 33 ;
     RECT  13.021 34.224 13.093 34.248 ;
     RECT  12.125 37.2 13.093 38.808 ;
     RECT  12.877 62.208 13.093 62.232 ;
     RECT  12.089 63.264 13.093 63.288 ;
     RECT  12.661 71.568 13.129 71.88 ;
     RECT  11.945 73.248 13.129 73.272 ;
     RECT  12.697 89.52 13.129 90.312 ;
     RECT  13.093 62.208 13.165 63.288 ;
     RECT  11.941 2.304 13.208 4.584 ;
     RECT  12.017 6.816 13.208 7.416 ;
     RECT  13.057 9.024 13.208 9.096 ;
     RECT  12.913 10.656 13.208 10.68 ;
     RECT  11.693 11.904 13.208 11.928 ;
     RECT  12.197 13.584 13.208 13.608 ;
     RECT  12.445 15.264 13.208 15.288 ;
     RECT  12.053 20.352 13.208 20.376 ;
     RECT  11.953 25.968 13.208 25.992 ;
     RECT  13.057 27.36 13.208 29.064 ;
     RECT  12.517 30.096 13.208 31.368 ;
     RECT  13.093 32.976 13.208 34.248 ;
     RECT  13.129 35.232 13.208 35.256 ;
     RECT  13.093 36.624 13.208 38.808 ;
     RECT  12.233 40.512 13.208 40.584 ;
     RECT  13.129 41.712 13.208 41.736 ;
     RECT  10.937 50.448 13.208 51 ;
     RECT  13.057 55.248 13.208 55.272 ;
     RECT  12.017 57.888 13.208 58.152 ;
     RECT  12.125 59.616 13.208 59.64 ;
     RECT  12.125 61.008 13.208 61.032 ;
     RECT  13.165 62.208 13.208 63.816 ;
     RECT  12.233 67.44 13.208 68.088 ;
     RECT  12.089 69.504 13.208 69.528 ;
     RECT  13.129 71.568 13.208 73.272 ;
     RECT  12.197 77.088 13.208 77.88 ;
     RECT  11.549 80.784 13.208 80.808 ;
     RECT  12.709 81.792 13.208 83.784 ;
     RECT  13.021 84.864 13.208 88.44 ;
     RECT  13.129 89.52 13.208 90.36 ;
     RECT  13.208 2.148 13.312 95.052 ;
     RECT  13.312 2.418 13.504 94.782 ;
     RECT  13.504 85.968 13.601 86.664 ;
     RECT  13.504 4.848 13.619 5.784 ;
     RECT  13.504 34.368 13.619 35.256 ;
     RECT  13.504 37.872 13.619 38.808 ;
     RECT  13.504 54.432 13.619 55.272 ;
     RECT  13.504 64.848 13.619 66.072 ;
     RECT  13.504 67.392 13.619 67.56 ;
     RECT  13.504 80.64 13.619 80.664 ;
     RECT  13.504 9.12 13.637 9.144 ;
     RECT  13.504 49.488 13.637 49.512 ;
     RECT  13.504 88.416 13.637 88.44 ;
     RECT  13.619 34.368 13.645 34.824 ;
     RECT  13.504 62.88 13.645 63.816 ;
     RECT  13.645 62.976 13.66 63.816 ;
     RECT  13.504 82.608 13.66 82.632 ;
     RECT  13.619 5.04 13.667 5.784 ;
     RECT  13.504 29.52 13.667 29.64 ;
     RECT  13.645 34.368 13.667 34.392 ;
     RECT  13.504 74.688 13.667 74.712 ;
     RECT  13.504 10.368 13.673 10.776 ;
     RECT  13.619 55.152 13.673 55.272 ;
     RECT  13.504 68.784 13.673 70.152 ;
     RECT  13.504 71.616 13.673 71.688 ;
     RECT  13.504 72.816 13.673 72.84 ;
     RECT  13.504 90.336 13.673 90.36 ;
     RECT  13.504 3.024 13.709 3.048 ;
     RECT  13.504 6.816 13.745 7.464 ;
     RECT  13.667 29.52 13.745 29.544 ;
     RECT  13.504 12.624 13.781 12.648 ;
     RECT  13.504 42.192 13.781 42.696 ;
     RECT  13.673 71.616 13.853 71.64 ;
     RECT  13.619 64.848 13.95 65.496 ;
     RECT  13.673 69.552 13.997 70.152 ;
     RECT  13.997 70.128 14.069 70.152 ;
     RECT  13.619 38.784 14.321 38.808 ;
     RECT  13.601 86.64 14.501 86.664 ;
     RECT  13.504 60.288 14.537 60.312 ;
     RECT  13.673 10.368 14.569 10.632 ;
     RECT  13.504 23.856 14.569 23.88 ;
     RECT  13.504 56.4 14.605 56.52 ;
     RECT  13.504 30.672 14.645 30.696 ;
     RECT  13.781 42.192 14.785 42.216 ;
     RECT  13.673 55.152 14.825 55.176 ;
     RECT  14.641 89.232 14.857 89.256 ;
     RECT  13.504 93.456 14.857 93.48 ;
     RECT  14.677 17.904 14.893 17.928 ;
     RECT  14.569 23.856 14.893 24.456 ;
     RECT  14.785 33.072 14.893 33.096 ;
     RECT  14.641 87.84 14.893 87.864 ;
     RECT  14.857 92.688 14.897 93.48 ;
     RECT  13.504 16.176 14.929 16.2 ;
     RECT  14.893 44.496 14.929 44.52 ;
     RECT  14.857 89.232 14.929 89.928 ;
     RECT  14.569 10.032 14.965 10.632 ;
     RECT  14.893 23.856 14.965 25.416 ;
     RECT  14.785 42.192 14.965 42.6 ;
     RECT  14.785 48.624 14.965 48.648 ;
     RECT  14.893 50.256 14.965 50.28 ;
     RECT  13.66 63.792 14.965 63.816 ;
     RECT  15.001 73.68 15.037 73.704 ;
     RECT  14.893 17.904 15.325 18.12 ;
     RECT  14.965 49.872 15.325 50.28 ;
     RECT  13.745 7.248 15.361 7.464 ;
     RECT  15.325 35.376 15.361 35.976 ;
     RECT  15.325 49.872 15.361 51.24 ;
     RECT  14.605 56.208 15.361 56.52 ;
     RECT  14.533 61.392 15.361 61.416 ;
     RECT  15.325 79.44 15.361 79.464 ;
     RECT  14.893 87.024 15.361 87.864 ;
     RECT  14.929 89.232 15.361 90.024 ;
     RECT  14.893 91.152 15.361 91.176 ;
     RECT  14.965 9.264 15.397 10.632 ;
     RECT  14.929 16.176 15.397 16.872 ;
     RECT  15.325 17.904 15.397 18.984 ;
     RECT  14.965 23.472 15.397 25.416 ;
     RECT  15.361 35.28 15.397 35.976 ;
     RECT  14.857 37.008 15.397 37.032 ;
     RECT  14.965 42.192 15.397 42.792 ;
     RECT  14.929 44.496 15.397 44.616 ;
     RECT  14.965 48.528 15.397 48.648 ;
     RECT  15.361 49.776 15.397 51.24 ;
     RECT  15.361 61.392 15.397 62.088 ;
     RECT  14.965 63.6 15.397 63.816 ;
     RECT  13.95 64.848 15.397 65.448 ;
     RECT  15.037 73.68 15.397 74.376 ;
     RECT  13.504 75.696 15.397 75.72 ;
     RECT  15.361 77.904 15.397 79.464 ;
     RECT  15.361 87.024 15.397 88.008 ;
     RECT  15.361 89.232 15.397 91.176 ;
     RECT  15.397 34.8 15.433 37.032 ;
     RECT  15.361 7.248 15.649 7.56 ;
     RECT  15.397 61.392 15.757 62.376 ;
     RECT  15.397 63.6 15.757 66.12 ;
     RECT  15.397 8.976 15.829 11.496 ;
     RECT  15.397 12.816 15.829 12.84 ;
     RECT  15.757 61.392 15.829 66.504 ;
     RECT  15.397 23.088 15.865 25.416 ;
     RECT  15.433 34.8 15.865 37.608 ;
     RECT  15.361 56.208 15.865 57.096 ;
     RECT  15.397 73.68 15.865 75.72 ;
     RECT  15.865 23.088 15.901 25.608 ;
     RECT  14.893 32.496 15.901 33.096 ;
     RECT  15.865 34.8 15.901 38.184 ;
     RECT  15.865 56.016 15.901 57.096 ;
     RECT  14.897 92.688 15.901 92.808 ;
     RECT  15.649 6.864 15.937 7.56 ;
     RECT  15.829 8.976 15.937 12.84 ;
     RECT  15.397 42.192 15.937 44.616 ;
     RECT  14.857 54.768 15.937 54.888 ;
     RECT  15.901 56.016 15.937 57.288 ;
     RECT  15.901 92.4 15.937 92.808 ;
     RECT  15.937 54.768 15.973 57.48 ;
     RECT  15.397 87.024 15.973 91.176 ;
     RECT  15.397 77.808 16.333 80.04 ;
     RECT  15.973 86.736 16.369 91.176 ;
     RECT  15.937 92.304 16.369 92.808 ;
     RECT  15.901 23.088 16.405 25.896 ;
     RECT  15.397 16.08 16.441 18.984 ;
     RECT  15.901 32.496 16.441 38.184 ;
     RECT  15.829 61.392 16.441 67.176 ;
     RECT  16.441 32.4 16.477 38.184 ;
     RECT  15.937 42.192 16.477 45 ;
     RECT  15.397 48.528 16.477 51.24 ;
     RECT  15.865 73.68 16.477 76.68 ;
     RECT  16.333 77.808 16.477 80.424 ;
     RECT  16.405 23.088 16.513 25.992 ;
     RECT  16.441 61.392 17.017 67.368 ;
     RECT  16.477 73.68 17.053 80.424 ;
     RECT  16.477 32.208 17.089 38.184 ;
     RECT  16.477 48.432 17.161 51.336 ;
     RECT  15.973 54.576 17.161 57.48 ;
     RECT  15.937 6.864 17.244 12.936 ;
     RECT  16.441 16.08 17.244 19.08 ;
     RECT  16.513 22.992 17.244 25.992 ;
     RECT  17.089 32.208 17.244 38.28 ;
     RECT  16.477 42.192 17.244 45.192 ;
     RECT  17.161 48.336 17.244 51.336 ;
     RECT  17.161 54.48 17.244 57.48 ;
     RECT  17.017 61.392 17.244 67.464 ;
     RECT  17.053 73.68 17.244 80.52 ;
     RECT  16.369 86.736 17.244 92.808 ;
    LAYER M5 ;
     RECT  3.984 0.016 4.104 1.763 ;
     RECT  2.4 2.137 2.52 2.151 ;
     RECT  7.8 2.137 7.92 2.151 ;
     RECT  13.2 2.137 13.32 2.151 ;
     RECT  2.4 2.151 2.712 2.773 ;
     RECT  3.984 1.763 4.008 2.773 ;
     RECT  2.4 2.773 4.008 2.821 ;
     RECT  11.952 2.293 11.976 3.059 ;
     RECT  7.8 2.151 8.112 3.109 ;
     RECT  2.4 2.821 4.344 3.443 ;
     RECT  7.8 3.109 8.52 3.829 ;
     RECT  13.2 2.151 13.512 4.837 ;
     RECT  13.2 4.837 13.608 5.029 ;
     RECT  3.984 3.443 4.296 5.123 ;
     RECT  6.864 3.829 8.52 5.123 ;
     RECT  11.616 4.549 11.64 5.123 ;
     RECT  7.8 5.123 8.52 5.365 ;
     RECT  13.2 5.029 13.656 5.795 ;
     RECT  7.8 5.365 8.808 6.035 ;
     RECT  2.4 3.443 2.712 6.085 ;
     RECT  3.984 5.123 4.104 6.229 ;
     RECT  7.8 6.035 8.52 6.229 ;
     RECT  7.392 6.229 8.52 6.899 ;
     RECT  7.8 6.899 8.52 7.043 ;
     RECT  2.4 6.085 2.808 7.475 ;
     RECT  11.472 6.229 11.496 7.475 ;
     RECT  11.664 8.437 11.688 8.485 ;
     RECT  13.2 5.795 13.608 9.155 ;
     RECT  3.984 6.229 4.728 9.589 ;
     RECT  7.8 7.043 8.232 9.925 ;
     RECT  0.144 8.197 0.168 10.163 ;
     RECT  2.4 7.475 2.712 10.309 ;
     RECT  2.304 10.309 2.712 10.741 ;
     RECT  3.984 9.589 5.304 10.883 ;
     RECT  7.152 9.925 8.232 10.981 ;
     RECT  6.864 10.981 8.232 11.365 ;
     RECT  3.984 10.883 4.728 11.941 ;
     RECT  6.864 11.365 8.52 12.325 ;
     RECT  6.24 12.325 8.52 12.899 ;
     RECT  2.304 10.741 2.904 13.139 ;
     RECT  7.44 12.899 8.52 13.139 ;
     RECT  9.984 11.941 10.008 13.237 ;
     RECT  9.696 13.237 10.008 13.283 ;
     RECT  11.088 8.485 11.688 13.573 ;
     RECT  11.088 13.573 11.736 13.621 ;
     RECT  2.4 13.139 2.904 14.197 ;
     RECT  6.24 12.899 6.264 14.915 ;
     RECT  3.984 11.941 4.968 15.491 ;
     RECT  2.4 14.197 3 15.685 ;
     RECT  7.44 13.139 8.112 16.019 ;
     RECT  9.696 13.283 9.72 16.019 ;
     RECT  2.304 15.685 3 16.595 ;
     RECT  3.984 15.491 4.248 17.029 ;
     RECT  7.8 16.019 8.112 17.509 ;
     RECT  10.992 13.621 11.736 17.555 ;
     RECT  7.8 17.509 8.808 18.133 ;
     RECT  3.984 17.029 5.112 18.275 ;
     RECT  11.712 17.555 11.736 18.419 ;
     RECT  2.304 16.595 2.712 18.851 ;
     RECT  10.512 18.181 10.536 18.851 ;
     RECT  3.984 18.275 4.248 19.237 ;
     RECT  7.104 18.133 8.808 19.909 ;
     RECT  10.272 19.237 10.296 19.955 ;
     RECT  11.616 19.093 11.64 19.955 ;
     RECT  3.984 19.237 4.68 20.149 ;
     RECT  3.984 20.149 5.256 20.291 ;
     RECT  7.104 19.909 9.144 20.579 ;
     RECT  3.984 20.291 5.16 21.155 ;
     RECT  11.664 20.725 11.688 21.637 ;
     RECT  10.8 21.637 11.688 21.683 ;
     RECT  2.4 18.851 2.712 22.741 ;
     RECT  3.984 21.155 4.248 22.741 ;
     RECT  2.4 22.741 4.248 23.077 ;
     RECT  6.768 22.741 6.792 23.317 ;
     RECT  5.28 22.117 5.304 23.987 ;
     RECT  6.48 23.317 6.792 24.323 ;
     RECT  2.304 23.077 4.248 24.469 ;
     RECT  7.8 20.579 8.808 24.469 ;
     RECT  2.304 24.469 4.728 24.515 ;
     RECT  6.48 24.323 6.504 24.563 ;
     RECT  10.8 21.683 10.824 24.563 ;
     RECT  11.904 22.165 11.928 24.853 ;
     RECT  7.632 24.469 8.808 25.045 ;
     RECT  11.28 24.853 11.928 25.139 ;
     RECT  6 25.093 6.024 25.667 ;
     RECT  2.304 24.515 2.856 25.715 ;
     RECT  7.632 25.045 9.096 25.717 ;
     RECT  3.984 24.515 4.728 26.291 ;
     RECT  2.4 25.715 2.856 26.629 ;
     RECT  6.864 25.717 9.096 26.629 ;
     RECT  6.192 26.629 9.096 27.205 ;
     RECT  11.28 25.139 11.304 27.301 ;
     RECT  11.28 27.301 12.024 27.635 ;
     RECT  6.192 27.205 9.768 28.019 ;
     RECT  6.192 28.019 9.096 28.547 ;
     RECT  12 27.635 12.024 28.643 ;
     RECT  2.4 26.629 2.904 29.219 ;
     RECT  13.2 9.155 13.512 29.509 ;
     RECT  6.192 28.547 6.216 29.605 ;
     RECT  13.2 29.509 13.608 29.605 ;
     RECT  5.424 29.605 6.216 29.651 ;
     RECT  13.2 29.605 13.656 30.469 ;
     RECT  13.104 30.469 13.656 30.565 ;
     RECT  3.984 26.291 4.248 30.709 ;
     RECT  5.424 29.651 5.448 30.709 ;
     RECT  7.632 28.547 9.096 30.757 ;
     RECT  12.288 30.565 13.656 31.379 ;
     RECT  2.4 29.219 2.712 31.813 ;
     RECT  3.984 30.709 5.448 31.813 ;
     RECT  2.4 31.813 5.448 32.149 ;
     RECT  6.864 30.757 9.096 32.483 ;
     RECT  2.4 32.149 5.688 32.771 ;
     RECT  5.664 32.771 5.688 32.965 ;
     RECT  5.664 32.965 6.312 33.299 ;
     RECT  11.088 31.285 11.112 33.445 ;
     RECT  11.088 33.445 12.024 33.635 ;
     RECT  5.76 33.299 6.312 33.827 ;
     RECT  13.056 31.379 13.656 34.259 ;
     RECT  13.2 34.259 13.656 34.403 ;
     RECT  2.4 32.771 2.712 34.501 ;
     RECT  3.984 32.771 4.536 34.835 ;
     RECT  7.392 32.483 9.096 34.931 ;
     RECT  0.192 34.933 0.216 35.315 ;
     RECT  4.08 34.835 4.536 35.363 ;
     RECT  11.232 33.635 12.024 35.363 ;
     RECT  12 35.363 12.024 36.421 ;
     RECT  2.4 34.501 2.856 36.563 ;
     RECT  13.2 34.403 13.608 36.613 ;
     RECT  13.104 36.613 13.608 37.187 ;
     RECT  5.76 33.827 5.784 37.667 ;
     RECT  13.2 37.187 13.608 37.907 ;
     RECT  2.4 36.563 2.712 38.005 ;
     RECT  7.632 34.931 9.096 38.243 ;
     RECT  4.08 35.363 4.488 38.533 ;
     RECT  7.632 38.243 8.112 38.581 ;
     RECT  11.04 36.421 12.024 38.819 ;
     RECT  7.056 38.581 8.112 39.205 ;
     RECT  4.08 38.533 4.776 39.395 ;
     RECT  7.056 39.205 8.808 39.733 ;
     RECT  6.24 39.733 8.808 40.499 ;
     RECT  4.08 39.395 4.488 40.693 ;
     RECT  6.24 40.499 8.112 40.883 ;
     RECT  2.4 38.005 2.904 41.123 ;
     RECT  0.192 41.221 0.216 41.411 ;
     RECT  6.24 40.883 6.264 41.651 ;
     RECT  4.08 40.693 4.584 42.083 ;
     RECT  7.632 40.883 8.112 42.133 ;
     RECT  12 38.819 12.024 42.227 ;
     RECT  4.08 42.083 4.104 42.709 ;
     RECT  3.984 42.709 4.104 42.755 ;
     RECT  7.632 42.133 8.232 43.477 ;
     RECT  5.712 42.709 5.736 43.523 ;
     RECT  6.864 43.477 8.232 43.813 ;
     RECT  2.4 41.123 2.712 43.861 ;
     RECT  3.984 42.755 4.008 43.861 ;
     RECT  11.568 42.709 11.592 44.051 ;
     RECT  2.4 43.861 4.008 44.483 ;
     RECT  6.864 43.813 8.28 44.627 ;
     RECT  2.4 44.483 2.712 45.733 ;
     RECT  2.304 45.733 2.712 45.875 ;
     RECT  1.248 46.501 1.272 46.643 ;
     RECT  10.224 44.965 10.248 46.739 ;
     RECT  7.632 44.627 8.28 46.835 ;
     RECT  3.984 44.483 4.008 46.931 ;
     RECT  0.192 47.701 0.216 47.891 ;
     RECT  9.696 47.269 9.72 47.939 ;
     RECT  6.528 47.173 6.552 48.419 ;
     RECT  0.144 48.709 0.168 48.899 ;
     RECT  2.4 45.875 2.712 48.949 ;
     RECT  7.632 46.835 8.112 49.477 ;
     RECT  9.408 48.421 9.432 49.477 ;
     RECT  7.632 49.477 9.432 50.437 ;
     RECT  6.864 50.437 9.432 50.819 ;
     RECT  10.416 50.101 10.44 51.299 ;
     RECT  6.96 50.819 9.432 51.347 ;
     RECT  2.4 48.949 2.904 51.395 ;
     RECT  7.632 51.347 9.432 52.309 ;
     RECT  7.632 52.309 10.296 52.405 ;
     RECT  6.864 52.405 10.296 53.267 ;
     RECT  11.952 52.357 11.976 53.555 ;
     RECT  6.864 53.267 8.232 53.603 ;
     RECT  7.632 53.603 8.232 54.325 ;
     RECT  13.2 37.907 13.512 54.421 ;
     RECT  2.4 51.395 2.712 54.469 ;
     RECT  7.632 54.325 8.328 54.661 ;
     RECT  7.2 54.661 8.328 55.139 ;
     RECT  9.408 53.267 10.296 55.139 ;
     RECT  2.4 54.469 2.904 55.237 ;
     RECT  7.2 55.139 8.112 55.283 ;
     RECT  9.408 55.139 9.624 55.331 ;
     RECT  2.4 55.237 3.432 55.669 ;
     RECT  7.632 55.283 8.112 56.245 ;
     RECT  13.2 54.421 13.608 56.531 ;
     RECT  11.424 56.341 11.448 56.773 ;
     RECT  6.048 54.085 6.072 57.013 ;
     RECT  2.4 55.669 3.912 57.059 ;
     RECT  9.552 55.331 9.624 57.253 ;
     RECT  9.216 57.253 9.624 57.299 ;
     RECT  10.704 56.773 11.448 57.635 ;
     RECT  10.704 57.635 10.728 57.877 ;
     RECT  2.4 57.059 3.48 58.117 ;
     RECT  9.216 57.299 9.576 58.739 ;
     RECT  11.952 58.117 11.976 58.739 ;
     RECT  7.536 56.245 8.112 58.787 ;
     RECT  10.56 57.877 10.728 58.835 ;
     RECT  6 57.013 6.072 59.077 ;
     RECT  10.704 58.835 10.728 59.173 ;
     RECT  0.144 59.029 0.168 59.219 ;
     RECT  9.552 58.739 9.576 59.315 ;
     RECT  10.704 59.173 10.824 59.605 ;
     RECT  10.704 59.605 11.688 59.797 ;
     RECT  5.76 59.077 6.072 59.845 ;
     RECT  7.632 58.787 8.112 60.277 ;
     RECT  2.4 58.117 3.96 60.853 ;
     RECT  0.144 60.613 0.168 60.899 ;
     RECT  5.664 59.845 6.072 60.949 ;
     RECT  2.4 60.853 4.296 61.331 ;
     RECT  7.632 60.277 8.904 62.195 ;
     RECT  13.2 56.531 13.512 62.533 ;
     RECT  4.272 61.331 4.296 62.723 ;
     RECT  2.4 61.331 2.808 62.821 ;
     RECT  13.104 62.533 13.512 62.869 ;
     RECT  13.104 62.869 13.608 62.963 ;
     RECT  13.2 62.963 13.608 63.011 ;
     RECT  5.664 60.949 6.648 63.205 ;
     RECT  10.128 59.797 11.688 63.251 ;
     RECT  0.144 63.253 0.168 63.539 ;
     RECT  10.128 63.251 10.488 63.779 ;
     RECT  7.632 62.195 8.112 63.781 ;
     RECT  7.632 63.781 8.376 64.165 ;
     RECT  5.568 63.205 6.648 64.355 ;
     RECT  1.248 64.165 1.272 64.403 ;
     RECT  6.048 64.355 6.648 64.549 ;
     RECT  7.632 64.165 9.096 64.549 ;
     RECT  13.2 63.011 13.512 65.365 ;
     RECT  6.048 64.549 9.096 65.509 ;
     RECT  10.128 63.779 10.152 65.509 ;
     RECT  11.664 63.251 11.688 65.509 ;
     RECT  2.304 62.821 2.808 65.699 ;
     RECT  6.048 65.509 11.688 65.939 ;
     RECT  6.048 65.939 8.232 66.227 ;
     RECT  6.048 66.227 8.112 66.661 ;
     RECT  9.984 65.939 11.688 66.901 ;
     RECT  5.328 66.661 8.112 67.235 ;
     RECT  9.696 66.901 11.688 67.283 ;
     RECT  11.664 67.283 11.688 67.571 ;
     RECT  2.304 65.699 2.712 67.859 ;
     RECT  2.4 67.859 2.712 67.957 ;
     RECT  5.664 67.235 8.112 68.003 ;
     RECT  2.4 67.957 2.952 69.301 ;
     RECT  5.664 68.003 6.552 69.587 ;
     RECT  9.696 67.283 10.152 69.587 ;
     RECT  13.2 65.365 13.992 70.163 ;
     RECT  6.528 69.587 6.552 70.499 ;
     RECT  7.536 68.003 8.112 70.645 ;
     RECT  0.144 71.461 0.168 71.651 ;
     RECT  13.2 70.163 13.512 71.653 ;
     RECT  2.4 69.301 3.432 71.699 ;
     RECT  6.576 70.645 8.112 71.987 ;
     RECT  4.416 71.653 4.44 72.947 ;
     RECT  0.144 73.717 0.168 73.907 ;
     RECT  4.896 73.477 4.92 73.909 ;
     RECT  7.8 71.987 8.112 74.005 ;
     RECT  2.4 71.699 2.712 74.101 ;
     RECT  10.128 69.587 10.152 74.629 ;
     RECT  9.648 74.629 10.152 74.677 ;
     RECT  13.2 71.653 13.656 74.723 ;
     RECT  4.512 73.909 4.92 75.013 ;
     RECT  9.648 74.677 10.44 75.013 ;
     RECT  2.4 74.101 2.856 75.541 ;
     RECT  4.512 75.013 5.112 75.541 ;
     RECT  2.4 75.541 5.112 75.587 ;
     RECT  6.576 71.987 6.6 75.781 ;
     RECT  7.8 74.005 8.232 75.781 ;
     RECT  9.648 75.013 10.776 75.827 ;
     RECT  9.744 75.827 10.776 76.357 ;
     RECT  6.576 75.781 8.232 76.979 ;
     RECT  9.744 76.357 11.688 77.123 ;
     RECT  5.088 75.587 5.112 77.125 ;
     RECT  5.088 77.125 5.592 77.171 ;
     RECT  7.8 76.979 8.232 77.267 ;
     RECT  6.576 76.979 6.6 78.037 ;
     RECT  7.8 77.267 8.112 78.037 ;
     RECT  11.664 77.123 11.688 78.131 ;
     RECT  9.744 77.123 10.296 78.371 ;
     RECT  10.272 78.371 10.296 78.469 ;
     RECT  2.4 75.587 3.576 78.707 ;
     RECT  5.568 77.171 5.592 79.765 ;
     RECT  6.576 78.037 8.112 79.765 ;
     RECT  10.272 78.469 10.632 79.765 ;
     RECT  11.712 78.469 11.736 79.765 ;
     RECT  5.568 79.765 8.112 80.291 ;
     RECT  13.2 74.723 13.512 80.629 ;
     RECT  10.272 79.765 11.736 80.771 ;
     RECT  13.2 80.629 13.608 80.773 ;
     RECT  10.272 80.771 10.632 81.347 ;
     RECT  5.712 80.291 8.112 81.779 ;
     RECT  11.712 80.771 11.736 81.781 ;
     RECT  13.104 80.773 13.608 81.781 ;
     RECT  2.4 78.707 2.712 82.021 ;
     RECT  9.264 80.341 9.288 82.115 ;
     RECT  0.144 81.637 0.168 82.403 ;
     RECT  6.576 81.779 8.112 82.403 ;
     RECT  10.272 81.347 10.344 82.643 ;
     RECT  11.712 81.781 13.608 82.643 ;
     RECT  2.4 82.021 3.432 82.691 ;
     RECT  11.712 82.643 13.512 82.691 ;
     RECT  6.576 82.403 6.648 83.173 ;
     RECT  10.272 82.643 10.296 83.701 ;
     RECT  2.4 82.691 2.712 84.325 ;
     RECT  10.272 83.701 10.968 84.659 ;
     RECT  6.432 83.173 6.648 84.899 ;
     RECT  10.272 84.659 10.44 84.901 ;
     RECT  2.4 84.325 2.904 84.947 ;
     RECT  9.408 84.901 10.44 85.669 ;
     RECT  9.408 85.669 10.536 85.715 ;
     RECT  12.576 82.691 13.512 85.765 ;
     RECT  0.144 85.717 0.168 86.003 ;
     RECT  6.528 84.899 6.648 86.005 ;
     RECT  7.8 82.403 8.112 86.005 ;
     RECT  6.528 86.005 8.112 86.581 ;
     RECT  9.408 85.715 9.432 86.581 ;
     RECT  10.416 85.715 10.536 86.675 ;
     RECT  11.808 85.765 13.512 86.675 ;
     RECT  5.088 83.749 5.112 86.963 ;
     RECT  2.4 84.947 2.712 87.157 ;
     RECT  6.528 86.581 9.432 87.203 ;
     RECT  10.416 86.675 10.44 87.251 ;
     RECT  2.4 87.157 2.904 87.827 ;
     RECT  6.528 87.203 8.808 87.827 ;
     RECT  6.816 87.827 8.808 88.787 ;
     RECT  6.816 88.787 8.112 89.845 ;
     RECT  4.56 88.885 4.584 89.939 ;
     RECT  6.816 89.845 9.096 89.989 ;
     RECT  2.4 87.827 2.712 90.085 ;
     RECT  12.576 86.675 13.512 90.323 ;
     RECT  6.816 89.989 9.768 90.755 ;
     RECT  2.4 90.085 2.856 91.235 ;
     RECT  7.8 90.755 9.768 91.283 ;
     RECT  9.648 91.283 9.768 91.619 ;
     RECT  6.288 91.333 6.312 92.579 ;
     RECT  5.088 91.189 5.112 92.963 ;
     RECT  11.424 92.677 11.448 93.155 ;
     RECT  9.648 91.619 9.672 93.205 ;
     RECT  9.648 93.205 10.296 93.251 ;
     RECT  2.4 91.235 2.808 93.347 ;
     RECT  3.984 92.917 4.008 94.259 ;
     RECT  10.272 93.251 10.296 94.259 ;
     RECT  2.4 93.347 2.712 95.049 ;
     RECT  7.8 91.283 8.112 95.049 ;
     RECT  13.2 90.323 13.512 95.049 ;
     RECT  2.4 95.049 2.52 95.063 ;
     RECT  7.8 95.049 7.92 95.063 ;
     RECT  13.2 95.049 13.32 95.063 ;
     RECT  4.008 1.763 4.104 2.821 ;
     RECT  2.52 2.137 3.984 2.151 ;
     RECT  2.712 2.151 3.984 2.773 ;
     RECT  11.976 2.293 13.2 3.059 ;
     RECT  2.712 3.443 3.984 6.085 ;
     RECT  4.104 5.123 4.296 6.229 ;
     RECT  7.392 5.123 7.8 6.229 ;
     RECT  2.808 6.085 3.984 7.475 ;
     RECT  2.712 7.475 3.984 10.741 ;
     RECT  11.472 7.475 11.496 8.437 ;
     RECT  11.472 8.437 11.664 8.485 ;
     RECT  11.688 8.437 13.2 13.573 ;
     RECT  2.904 10.741 3.984 14.197 ;
     RECT  4.728 10.883 5.304 11.941 ;
     RECT  4.968 11.941 5.304 12.325 ;
     RECT  8.52 11.941 9.984 13.139 ;
     RECT  10.008 11.941 11.088 13.283 ;
     RECT  4.968 12.325 6.24 14.915 ;
     RECT  6.264 12.899 7.44 14.915 ;
     RECT  9.696 13.139 9.984 13.237 ;
     RECT  9.72 13.283 11.088 13.621 ;
     RECT  11.736 13.573 13.2 18.419 ;
     RECT  9.72 13.621 10.992 16.019 ;
     RECT  3 14.197 3.984 16.595 ;
     RECT  2.712 16.595 3.984 22.741 ;
     RECT  10.992 17.555 11.712 18.181 ;
     RECT  10.536 18.181 11.712 18.419 ;
     RECT  4.248 18.275 4.68 19.237 ;
     RECT  10.536 18.419 11.64 18.851 ;
     RECT  10.512 18.851 11.64 19.093 ;
     RECT  10.512 19.093 11.616 19.237 ;
     RECT  8.808 19.237 10.272 19.909 ;
     RECT  10.296 19.237 11.616 19.955 ;
     RECT  9.144 19.909 10.272 19.955 ;
     RECT  11.688 20.725 13.2 21.683 ;
     RECT  4.248 21.155 5.16 22.117 ;
     RECT  10.824 21.683 13.2 22.165 ;
     RECT  4.248 22.117 5.28 23.987 ;
     RECT  10.824 22.165 11.904 24.563 ;
     RECT  11.928 22.165 13.2 25.139 ;
     RECT  5.304 22.741 6.768 23.317 ;
     RECT  6.792 22.741 7.8 24.323 ;
     RECT  5.304 23.317 6.48 23.987 ;
     RECT  4.248 23.987 6.48 24.469 ;
     RECT  6.504 24.323 7.8 24.469 ;
     RECT  4.728 24.469 6.48 24.563 ;
     RECT  6.504 24.469 7.632 24.563 ;
     RECT  2.856 24.515 3.984 26.629 ;
     RECT  4.728 24.563 7.632 25.093 ;
     RECT  11.28 24.563 11.904 24.853 ;
     RECT  4.728 25.093 6 25.667 ;
     RECT  6.024 25.093 7.632 25.667 ;
     RECT  4.728 25.667 7.632 25.717 ;
     RECT  4.728 25.717 6.864 26.291 ;
     RECT  6.192 26.291 6.864 26.629 ;
     RECT  2.904 26.629 3.984 29.219 ;
     RECT  9.768 27.205 11.28 27.635 ;
     RECT  12.024 27.301 13.2 28.643 ;
     RECT  6.216 28.547 7.632 29.651 ;
     RECT  2.712 29.219 3.984 31.813 ;
     RECT  4.248 29.605 5.424 30.709 ;
     RECT  5.448 29.651 7.632 30.757 ;
     RECT  5.448 30.757 6.864 32.149 ;
     RECT  11.112 31.285 12.288 31.379 ;
     RECT  5.688 32.149 6.864 32.483 ;
     RECT  5.688 32.483 7.392 32.965 ;
     RECT  2.712 32.771 3.984 34.501 ;
     RECT  4.536 32.771 5.664 33.299 ;
     RECT  6.312 32.965 7.392 33.827 ;
     RECT  4.536 33.299 5.76 35.363 ;
     RECT  12.024 33.445 13.056 34.259 ;
     RECT  12.024 34.259 13.2 36.613 ;
     RECT  2.856 34.501 3.984 34.835 ;
     RECT  2.856 34.835 4.08 36.563 ;
     RECT  4.488 35.363 5.76 37.667 ;
     RECT  11.232 35.363 12 36.421 ;
     RECT  2.712 36.563 4.08 38.005 ;
     RECT  12.024 36.613 13.104 37.187 ;
     RECT  12.024 37.187 13.2 42.227 ;
     RECT  4.488 37.667 4.776 38.533 ;
     RECT  2.904 38.005 4.08 41.123 ;
     RECT  8.112 38.243 8.808 39.205 ;
     RECT  4.488 39.395 4.584 40.693 ;
     RECT  6.264 40.883 7.632 41.651 ;
     RECT  2.712 41.123 4.08 42.709 ;
     RECT  2.712 42.709 3.984 43.861 ;
     RECT  5.736 43.477 6.864 43.523 ;
     RECT  2.712 44.483 3.984 46.931 ;
     RECT  2.304 45.875 2.4 46.501 ;
     RECT  1.272 46.501 2.4 46.643 ;
     RECT  6.552 47.173 7.632 48.419 ;
     RECT  8.112 48.421 9.408 49.477 ;
     RECT  9.432 50.101 10.416 51.299 ;
     RECT  9.432 51.299 10.296 52.309 ;
     RECT  6.96 51.347 7.632 52.405 ;
     RECT  11.976 52.357 13.2 53.555 ;
     RECT  8.232 53.267 9.408 54.325 ;
     RECT  6.864 53.603 7.632 54.085 ;
     RECT  6.072 54.085 7.632 54.661 ;
     RECT  8.328 54.325 9.408 55.139 ;
     RECT  6.072 54.661 7.2 55.283 ;
     RECT  8.112 55.139 9.408 55.331 ;
     RECT  6.072 55.283 7.632 56.245 ;
     RECT  8.112 55.331 9.552 57.253 ;
     RECT  6.072 56.245 7.536 58.787 ;
     RECT  9.624 56.773 10.704 57.299 ;
     RECT  3.48 57.059 3.912 58.117 ;
     RECT  8.112 57.253 9.216 58.739 ;
     RECT  9.576 57.299 10.704 57.877 ;
     RECT  10.728 57.635 11.448 58.117 ;
     RECT  9.576 57.877 10.56 58.835 ;
     RECT  10.728 58.117 11.952 58.739 ;
     RECT  11.976 58.117 13.2 58.739 ;
     RECT  8.112 58.739 9.552 59.315 ;
     RECT  10.728 58.739 13.2 59.173 ;
     RECT  9.576 58.835 10.704 59.315 ;
     RECT  10.824 59.173 13.2 59.605 ;
     RECT  0.144 59.219 0.168 60.613 ;
     RECT  8.112 59.315 10.704 59.797 ;
     RECT  11.688 59.605 13.2 62.533 ;
     RECT  8.112 59.797 10.128 60.277 ;
     RECT  8.904 60.277 10.128 62.195 ;
     RECT  4.296 60.853 5.664 62.723 ;
     RECT  6.648 60.949 7.632 64.549 ;
     RECT  2.808 61.331 4.272 62.723 ;
     RECT  11.688 62.533 13.104 62.963 ;
     RECT  5.568 62.723 5.664 63.205 ;
     RECT  11.688 62.963 13.2 67.571 ;
     RECT  10.488 63.251 11.664 63.779 ;
     RECT  10.152 63.779 11.664 65.509 ;
     RECT  1.272 64.165 2.304 64.403 ;
     RECT  9.096 64.165 10.128 65.509 ;
     RECT  8.232 65.939 9.984 66.227 ;
     RECT  9.696 66.227 9.984 66.901 ;
     RECT  10.152 67.283 11.664 67.571 ;
     RECT  6.552 68.003 7.536 70.499 ;
     RECT  13.512 70.163 13.656 71.653 ;
     RECT  6.576 70.499 7.536 70.645 ;
     RECT  3.432 71.653 4.416 71.699 ;
     RECT  6.6 71.987 7.8 75.781 ;
     RECT  8.232 74.629 9.648 75.827 ;
     RECT  5.112 75.013 6.576 77.125 ;
     RECT  3.576 75.587 5.088 77.171 ;
     RECT  8.232 75.827 9.744 77.267 ;
     RECT  11.688 76.357 13.2 78.131 ;
     RECT  6.6 76.979 7.8 78.037 ;
     RECT  10.296 77.123 11.664 78.131 ;
     RECT  5.592 77.125 6.576 79.765 ;
     RECT  10.296 78.131 13.2 78.469 ;
     RECT  10.632 78.469 11.712 79.765 ;
     RECT  11.736 78.469 13.2 80.773 ;
     RECT  8.112 80.341 9.264 82.115 ;
     RECT  9.288 80.341 10.272 82.115 ;
     RECT  10.632 80.771 11.712 81.347 ;
     RECT  11.736 80.773 13.104 81.781 ;
     RECT  10.344 81.347 11.712 82.643 ;
     RECT  6.432 81.779 6.576 83.173 ;
     RECT  6.648 82.403 7.8 86.005 ;
     RECT  10.296 82.643 11.712 82.691 ;
     RECT  10.296 82.691 10.968 83.701 ;
     RECT  5.112 83.749 6.432 84.899 ;
     RECT  10.44 84.659 10.968 85.669 ;
     RECT  5.112 84.899 6.528 86.963 ;
     RECT  8.112 84.901 9.408 86.581 ;
     RECT  10.536 85.669 10.968 85.765 ;
     RECT  9.432 85.715 10.416 87.203 ;
     RECT  10.536 85.765 11.808 86.675 ;
     RECT  8.112 88.787 8.808 89.845 ;
     RECT  6.816 90.755 7.8 91.333 ;
     RECT  5.112 91.333 6.288 92.579 ;
     RECT  6.312 91.333 7.8 92.579 ;
     RECT  2.808 92.917 3.984 93.347 ;
     RECT  4.008 92.917 5.088 92.963 ;
     RECT  2.712 93.347 3.984 94.259 ;
  END
END ot_qfd_vm_xpad2_t
END LIBRARY
